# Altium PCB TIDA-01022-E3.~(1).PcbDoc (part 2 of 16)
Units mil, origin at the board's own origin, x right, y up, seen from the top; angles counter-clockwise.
Board outline 6929.13 x 11614.17 mil, 12 copper layers (L1_Top Layer, L2_GND, L3_GND, L4_Signal Layer 1, L5_GND, L6_PWR, L7_GND/PWR, L8_PWR, L9_GND/PWR, L10_Signal Layer 2, L11_GND, L12_Bottom Layer), stack 64.6 mil thick; 1733 components, 993 nets, 5987 pads, 3555 vias.

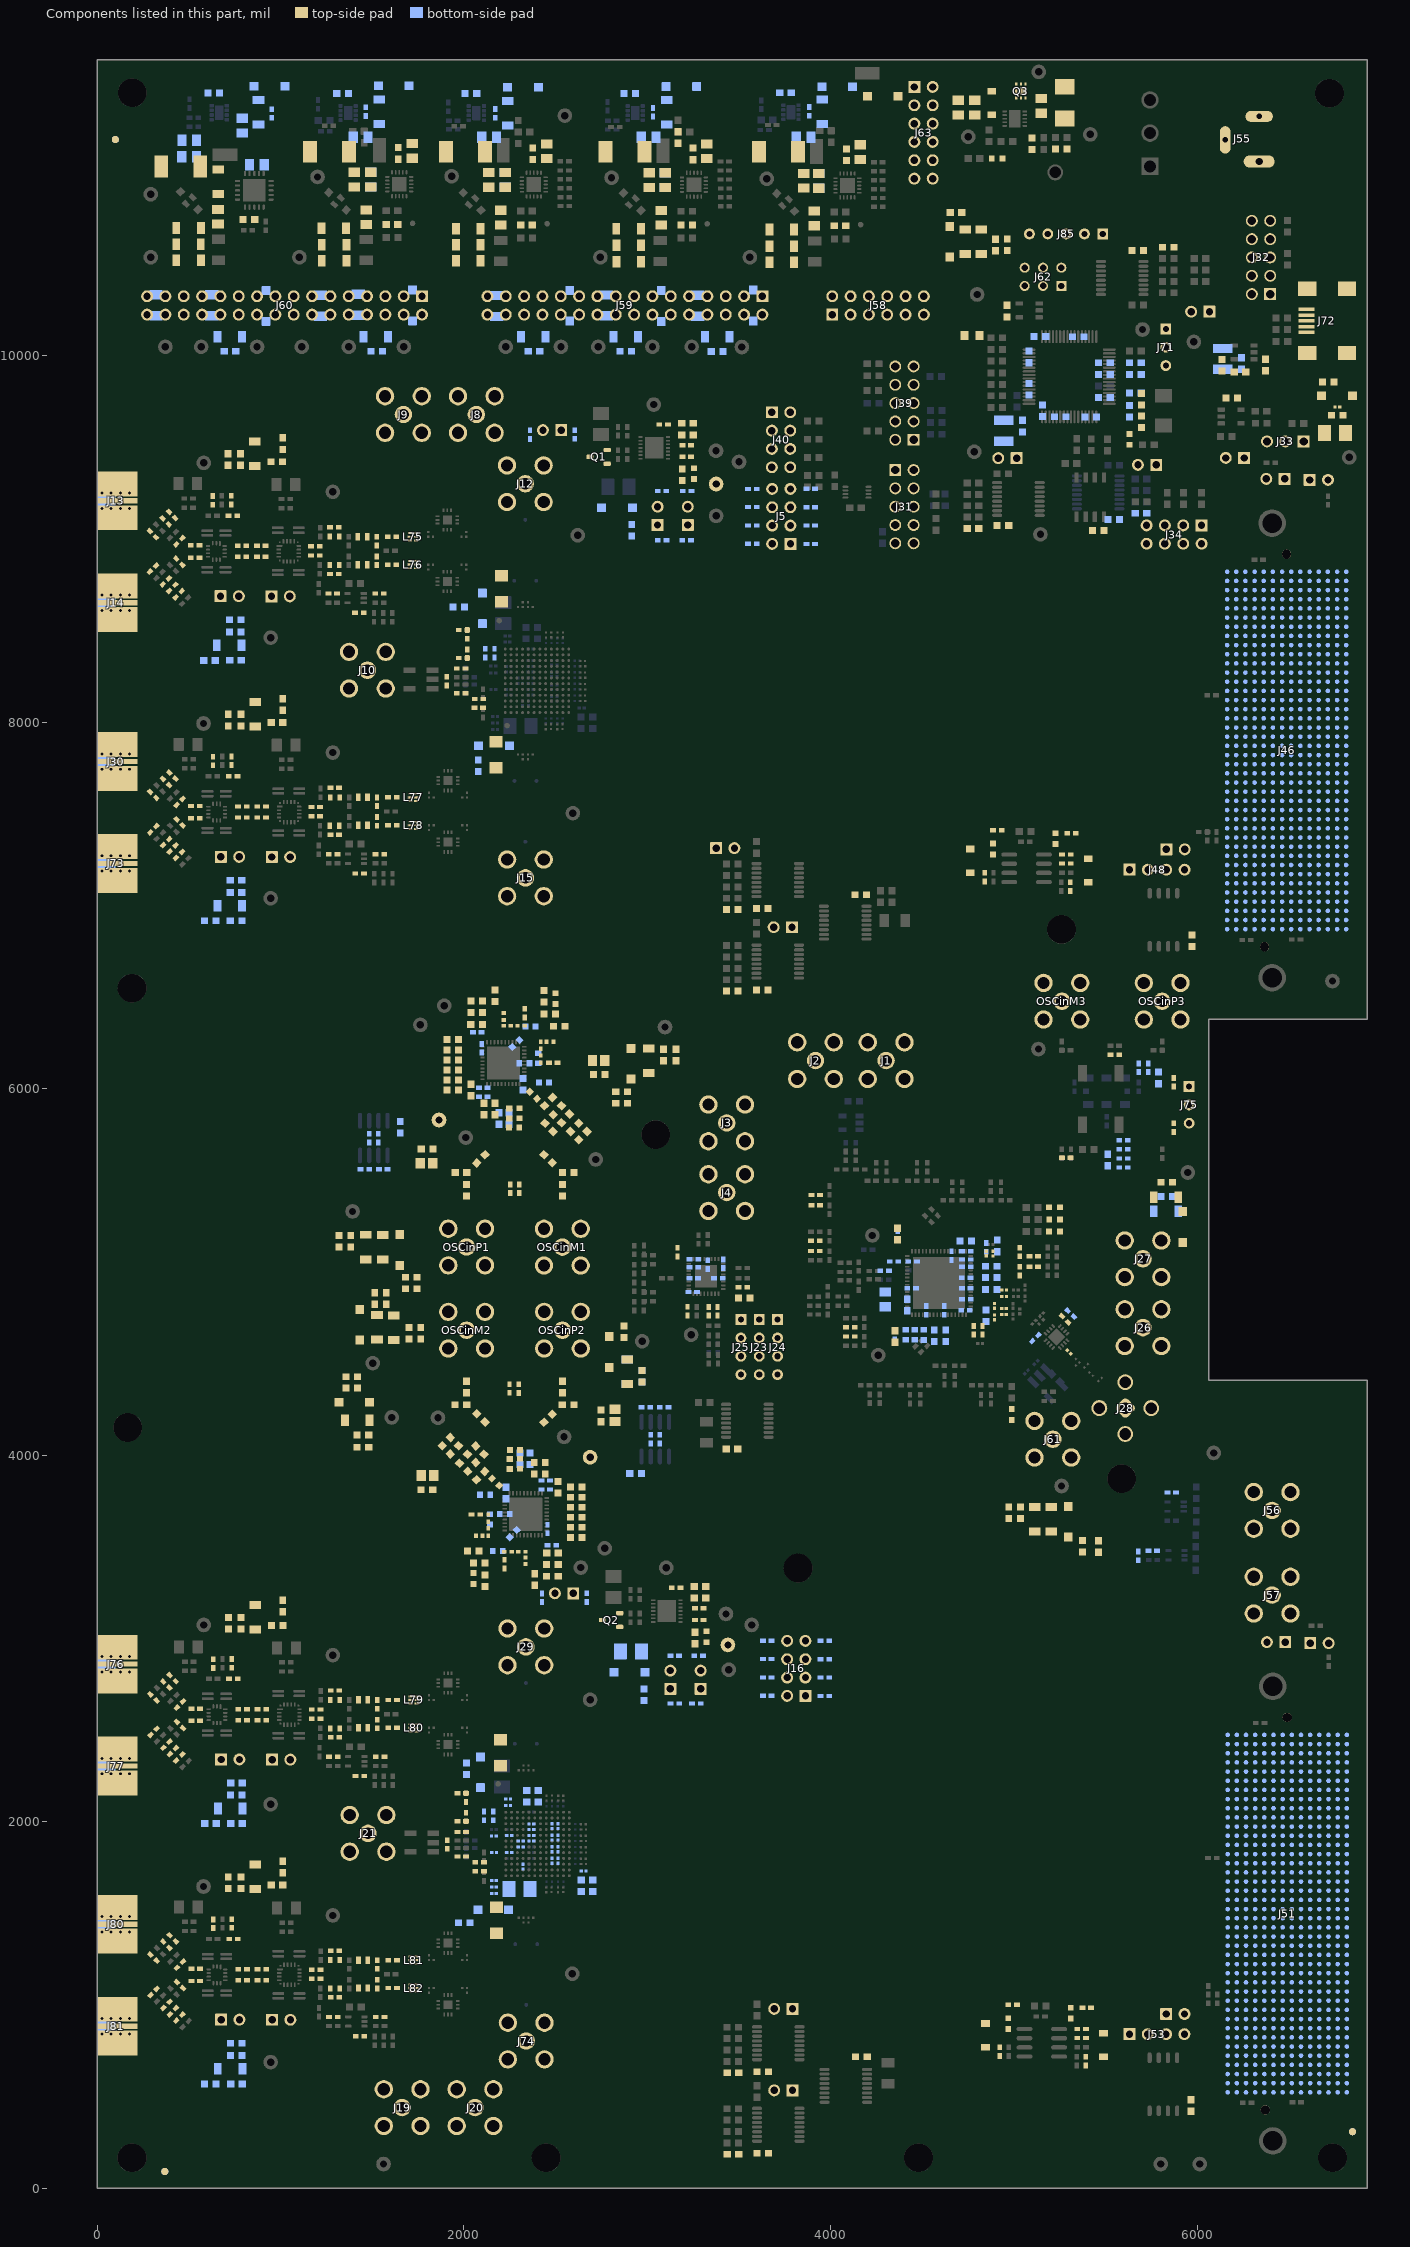
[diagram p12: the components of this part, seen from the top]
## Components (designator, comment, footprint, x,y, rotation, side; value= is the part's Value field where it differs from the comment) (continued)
C288 "GRM033C71A104KE14D" 0201#1 2367.24,1894.85 r0 bottom
C289 "GRM033C71A104KE14D" 0201#1 2367.24,1926.34 r0 bottom
C290 "GRM033C71A104KE14D" 0201#1 2367.24,1957.84 r0 bottom
C291 "GRM033C71A104KE14D" 0201#1 2367.24,1989.33 r0 bottom
C292 "C1608X5R1A105K080AC" 0603 2373.6,2108.56 r0 bottom
C293 "C1608X5R1A105K080AC" 0603 2373.6,2170.56 r0 bottom
C294 "293D106X0010B2TE3" 3528-21 2302.86,1632.5 r0 bottom
C295 "GRM033C71A104KE14D" 0201#1 2322.76,1755.87 r270 bottom
C296 "GRM033C71A104KE14D" 0201#1 2246.77,1926.34 r180 bottom
C297 "GRM033C71A104KE14D" 0201#1 2246.77,1831.85 r180 bottom
C298 "GRM033C71A104KE14D" 0201#1 2309.76,1894.85 r180 bottom
C299 "GRM033C71A104KE14D" 0201#1 2309.76,1863.35 r180 bottom
C300 "GRM033C71A104KE14D" 0201#1 2240.6,2124.56 r180 bottom
C301 "GRM033C71A104KE14D" 0201#1 2164.15,1831.8 r180 bottom
C302 "GRM033C71A104KE14D" 0201#1 2163.15,1921.8 r180 bottom
C303 "GRM033C71A104KE14D" 0201#1 2163.6,1680.56 r180 bottom
C304 "GRM033C71A104KE14D" 0201#1 2163.6,1644.56 r180 bottom
C305 "GRM033C71A104KE14D" 0201#1 2163.6,1609.56 r180 bottom
C306 "GRM033C71A104KE14D" 0201#1 2240.6,2089.56 r180 bottom
C307 "GRM033R60J104KE19D" 0201_033 5301,4563 r135 top
C308 "C1005X7R1E104M050BB" 0402#1 5310.3,4772.7 r135 bottom
C309 "293D106X0010B2TE3" 3528-21 2910.79,2930.24 r0 bottom
C310 "GRM033C71A104KE14D" 0201#1 2511.73,1787.37 r90 bottom
C311 "GRM033C71A104KE14D" 0201#1 2480.24,1787.37 r90 bottom
C312 "GRM033C71A104KE14D" 0201#1 2480.24,1850.36 r90 bottom
C313 "GRM033C71A104KE14D" 0201#1 2511.73,1850.36 r90 bottom
C314 "GRM033C71A104KE14D" 0201#1 2652.77,1731.37 r0 bottom
C315 "GRM033C71A104KE14D" 0201#1 2480.24,1913.35 r270 bottom
C316 "GRM033C71A104KE14D" 0201#1 2511.73,1913.35 r270 bottom
C317 "GRM033C71A104KE14D" 0201#1 2480.24,1976.34 r270 bottom
C318 "GRM033C71A104KE14D" 0201#1 2511.73,1976.34 r270 bottom
C319 "C1608X5R1A105K080AC" 0603 2671.54,1682.24 r0 bottom
C320 "C1608X5R1A105K080AC" 0603 2671.54,1619.24 r0 bottom
C321 "C1005X7R1E104M050BB" 0402#1 2081.89,8126.19 r0 top
C322 "520L103KT16T" 0402_065 2331.07,6411.77 r270 top
C323 "C1608X7R1C105K080AC" 0603 2191.16,5836.72 r90 bottom
C324 "C1608X7R1C105K080AC" 0603L 2378.66,5963.82 r135 top
C325 "C1005X7R1E104M050BB" 0402#1 2080.51,8077.19 r0 top
C326 "C1608X7R1C105K080AC" 0603L 2329.56,6138.82 r180 bottom
C327 "0603YC104JAT2A" 0603L 2283.06,6246.02 r45 bottom
C328 "0603YC104JAT2A" 0603 1798.77,5670.52 r0 top
C329 "C0805C106K8PACTU" 0805 1795.77,5592.72 r0 top
C330 "C0805C106K8PACTU" 0805 2734.77,6153.85 r0 top
C331 "0603YC104JAT2A" 0603 2737.77,6078.05 r0 top
C332 "C1608X7R1C105K080AC" 0603 2069.28,6414.92 r0 top
C333 "C1608X7R1C105K080AC" 0603 1938.66,6047.12 r0 top
C334 "C1005X7R1E104M050BB" 0402#1 2085.22,1780.19 r0 top
C335 "GRM1885C1H182JA01D" 0603 1938.66,6156.42 r0 top
C336 "GRM1885C2A301JA01D" 0603 2603.66,5743.82 r315 top
C337 "C0603C563J4RACTU" 0603 2553.66,5883.82 r315 top
C338 "520L103KT16T" 0402_065 2486.81,6141.72 r180 top
C339 "06031C152JAT2A" 0603 2460.85,5928.95 r225 top
C340 "C1608X7R1C105K080AC" 0603 2322,6024.32 r270 bottom
C341 "C1005X7R1E104M050BB" 0402#1 2085.22,1731.19 r0 top
C342 "C1608X5R1A106M080AC" 0603 1938.66,6102.02 r180 top
C343 "C1608X7R1C105K080AC" 0603 2038.16,5992.72 r90 top
C344 "C1608X5R1A106M080AC" 0603 1938.66,6267.52 r180 top
C345 "C1608X5R1A106M080AC" 0603 2168.66,5888.82 r270 top
C346 "C1608X5R1A106M080AC" 0603 2068.87,6350.82 r0 top
C347 "C1608X5R1A106M080AC" 0603 1938.66,6211.12 r0 top
C348 "0603YC104JAT2A" 0603L 2246.86,5864.22 r90 top
C349 "0603YC104JAT2A" 0603L 2302.04,5865.92 r90 top
C350 "0603YC104JAT2A" 0603 1651.97,5788.77 r90 bottom
C351 "GRM033R60J104KE19D" 0201_033 4894.89,4752 r90 top
C352 "520L103KT16T" 0402_065 2220.55,3406.2 r90 top
C353 "C1608X7R1C105K080AC" 0603 2360.46,3981.26 r270 bottom
C354 "C1608X7R1C105K080AC" 0603L 2172.96,3854.16 r315 top
C355 "GRM1555C1H471JA01D" 0402#1 3031,11327 r270 bottom
C356 "C1608X7R1C105K080AC" 0603L 2222.06,3679.16 r0 bottom
C357 "0603YC104JAT2A" 0603L 2268.56,3571.96 r225 bottom
C358 "0603YC104JAT2A" 0603 1797.65,3811.53 r180 top
C359 "C0805C106K8PACTU" 0805 1800.65,3889.33 r180 top
C360 "C0805C106K8PACTU" 0805 2824.18,4217.68 r270 top
C361 "0603YC104JAT2A" 0603 2748.38,4214.68 r270 top
C362 "C1608X7R1C105K080AC" 0603 2482.34,3403.06 r180 top
C363 "C1608X7R1C105K080AC" 0603 2612.96,3770.86 r180 top
C364 "GRM1555C1H471JA01D" 0402#1 2170.76,11320.39 r270 bottom
C365 "GRM1885C1H182JA01D" 0603 2612.96,3661.56 r180 top
C366 "GRM1885C2A301JA01D" 0603 1947.96,4074.16 r135 top
C367 "C0603C563J4RACTU" 0603 1997.96,3934.16 r135 top
C368 "520L103KT16T" 0402_065 2064.8,3676.26 r0 top
C369 "06031C152JAT2A" 0603 2090.76,3889.03 r45 top
C370 "C1608X7R1C105K080AC" 0603 2229.61,3793.65 r90 bottom
C371 "GRM1555C1H471JA01D" 0402#1 3883,11332 r270 bottom
C372 "C1608X5R1A106M080AC" 0603 2612.96,3715.96 r0 top
C373 "C1608X7R1C105K080AC" 0603 2513.46,3825.26 r270 top
C374 "C1608X5R1A106M080AC" 0603 2612.96,3550.46 r0 top
C375 "C1608X5R1A106M080AC" 0603 2382.96,3929.16 r90 top
C376 "C1608X5R1A106M080AC" 0603 2482.75,3467.16 r180 top
C377 "C1608X5R1A106M080AC" 0603 2612.96,3606.86 r180 top
C378 "0603YC104JAT2A" 0603L 2304.76,3953.76 r270 top
C379 "0603YC104JAT2A" 0603L 2249.58,3952.06 r270 top
C380 "0603YC104JAT2A" 0603 2936.3,3899.45 r0 bottom
C381 "EMK107BBJ106MA-T" 0603 3529.5,4857.79 r180 top
C382 "C1005X7S1A105K050BC" 0402#1 3521.5,4916.29 r180 top
C383 "GRM155R71C104KA88D" 0402#1 3219,4786 r90 top
C384 "GRM155R71E103KA01D" 0402#1 3254.5,5025.29 r0 bottom
C385 "GRM155R71E103KA01D" 0402#1 3247.88,4890.67 r0 bottom
C386 "GRM155R71E103KA01D" 0402#1 3253.5,4965.29 r0 bottom
C387 "GRM155R71E103KA01D" 0402#1 3330.5,5040.29 r90 bottom
C388 "GRM155R71E103KA01D" 0402#1 3387.5,4965.29 r180 bottom
C389 "GRM155R71E103KA01D" 0402#1 3414.78,5044.67 r90 bottom
C390 "GRM155R71E103KA01D" 0402#1 3254.5,5069.79 r180 bottom
C391 "C1005X7R1E104M050BB" 0402#1 3335.5,4785.29 r90 top
C392 "C1005X7R1E104M050BB" 0402#1 3383.5,4785.29 r90 top
C393 "0201ZD392KAT2A" 0201#1 4886.47,5099.94 r90 top
C394 "C1005X7R1E104M050BB" 0402#1 3917.47,5169.44 r180 top
C395 "GRM0335C1E470JA01D" 0201_033 4849.35,5100.47 r90 top
C396 "C1005X7R1E104M050BB" 0402#1 3917.47,5114.44 r180 top
C397 "GRM033R60J104KE19D" 0201_033 4946.41,4866.77 r180 top
C398 "C1005X5R1A684K050BB" 0402#1 4828.97,4682.02 r90 top
C399 "C1005X7R1E104M050BB" 0402#1 4780.97,4682.02 r90 top
C400 "GRM033R60J104KE19D" 0201_033 4946.41,4900.77 r180 top
C401 "C1005X7R1E104M050BB" 0402#1 4108.01,4698.08 r180 top
C402 "C1005X7R1E104M050BB" 0402#1 4108.01,4648.08 r180 top
C403 "GRM033R60J104KE19D" 0201_033 4945.97,4769.02 r180 top
C404 "GRM033R60J104KE19D" 0201_033 4945.97,4801.02 r180 top
C405 "GRM033R60J104KE19D" 0201_033 4894.89,4815 r270 top
C406 "C1005X7R1E104M050BB" 0402#1 5031.66,5004.8 r90 top
C407 "C1005X7R1E104M050BB" 0402#1 5108.66,5028.8 r0 top
C408 "C1005X7R1E104M050BB" 0402#1 5108.66,5085.8 r0 top
C409 "C0402C120J3GACAUTO" 0402#1 5031.66,5108.8 r270 top
C410 "C1005X7R1E104M050BB" 0402#1 5285.7,5622.27 r180 top
C411 "C1005X5R0J475M050BC" 0402#1 5733.97,6113.84 r270 bottom
C412 "GRM155R71E103KA01D" 0402#1 5680.97,6113.84 r270 bottom
C413 "C1005X7R1E104M050BB" 0402#1 3919.28,5419.5 r180 top
C414 "GRM1555C1H100JA01D" 0402#1 5598.08,5669.02 r180 bottom
C415 "C1005X7R1E104M050BB" 0402#1 3919.28,5364.5 r180 top
C416 "GRM155R71E222KA01D" 0402#1 5598.08,5619.02 r180 bottom
C417 "C1005X7R1E104M050BB" 0402#1 5550.66,6185.09 r0 top
C418 "04025A101FAT2A" 0402#1 5598.08,5719.02 r180 bottom
C419 "C1005X7R1E104M050BB" 0402#1 5598.08,5570.02 r180 bottom
C420 "C1005X7S1A105K050BC" 0402#1 4441.66,4910.2 r0 bottom
C421 "GRM155R71C104KA88D" 0402#1 4740.87,4851.14 r180 bottom
C422 "GRM155R71E103KA01D" 0402#1 4735.97,4791.02 r180 bottom
C423 "C1005X7R1E104M050BB" 0402#1 4447.89,5057 r180 bottom
C424 "C1005X7R1E104M050BB" 0402#1 4294.47,5006.94 r0 bottom
C425 "C0603C330J5GACTU" 0603L 4507.97,4656.95 r90 bottom
C426 "C0603C330J5GACTU" 0603L 4458.97,4657.46 r90 bottom
C427 "C0603C330J5GACTU" 0603L 4409.97,4657.02 r90 bottom
C428 "C1005X7S1A105K050BC" 0402#1 4620.79,4790.12 r90 bottom
C429 "C1005X7S1A105K050BC" 0402#1 4522.36,4790.12 r90 bottom
C430 "C1005X7S1A105K050BC" 0402#1 4350.97,4655.89 r270 bottom
C431 "C0603C104J3RACTU" 0603 4418.03,4819.65 r270 bottom
C432 "C0805C106K8PACTU" 0805_HV 4298.97,4850.02 r270 bottom
C433 "C1005X7S1A105K050BC" 0402#1 4848.97,5134.02 r90 bottom
C434 "GRM155R71C104KA88D" 0402#1 4741.35,5112.02 r180 bottom
C435 "GRM155R71E103KA01D" 0402#1 4740.87,5067.68 r180 bottom
C436 "C1005X7R1E104M050BB" 0402#1 4740.87,5028.31 r0 bottom
C437 "C1005X7R1E104M050BB" 0402#1 4739.47,4967.94 r0 bottom
C438 "C1005X7R1E104M050BB" 0402#1 4740.47,4910.94 r0 bottom
C439 "C1005X7S1A105K050BC" 0402#1 4365.97,5199.14 r90 bottom
C440 "C1005X7S1A105K050BC" 0402#1 4660.16,5089.33 r270 bottom
C441 "C0603C104J3RACTU" 0603 5675.72,10572.95 r0 top
C442 "C0603C104J3RACTU" 0603 5841.84,10590.12 r180 top
C443 "C0603C104J3RACTU" 0603 4777.32,9056.2 r0 top
C444 "C0603C104J3RACTU" 0603 4940.2,9072.76 r180 top
C445 "C0603C104J3RACTU" 0603 6189.08,9767.75 r0 top
C446 "C1005X7S1A105K050BC" 0402#1 5117,4639 r225 bottom
C447 "C0603C104J3RACTU" 0603 5544.82,9105 r0 bottom
C448 "C0603C104J3RACTU" 0603 5693.31,9139.2 r180 bottom
C449 "C0603C104J3RACTU" 0603 3627.07,6537.73 r180 top
C450 "C0603C104J3RACTU" 0603 3463.97,6532.22 r0 top
C451 "C0603C104J3RACTU" 0603 3630.4,191.73 r180 top
C452 "C0603C104J3RACTU" 0603 3467.31,186.22 r0 top
C453 "C0603C104J3RACTU" 0603 3626.82,6982.68 r180 top
C454 "C0603C104J3RACTU" 0603 3463.97,6976.93 r0 top
C455 "C0603C104J3RACTU" 0603 3629.91,636.44 r180 top
C456 "C0603C104J3RACTU" 0603 3467.31,630.93 r0 top
C457 "GRM188R61A106ME69D" 0603 5662.88,9794.97 r0 bottom
C458 "C0603C104J3RACTU" 0603 5493.88,9770.97 r0 bottom
C459 "C0603C104J3RACTU" 0603 5418.88,9663.97 r0 bottom
C460 "C0603C104J3RACTU" 0603 5493.88,9959.97 r0 bottom
C461 "C0603C104J3RACTU" 0603 5083.38,9992.24 r270 bottom
C462 "C0603C104J3RACTU" 0603 5141.88,10102.97 r0 bottom
C463 "C0603C104J3RACTU" 0603 5083.38,9815.07 r90 bottom
C464 "C0603C104J3RACTU" 0603 5351.1,10102.47 r0 bottom
C465 "C0603C104J3RACTU" 0603 5252.67,9665.47 r0 bottom
C466 "GRM188R61A106ME69D" 0603 5662.88,9895.97 r0 bottom
C467 "C0603C104J3RACTU" 0603 5493.88,9895.97 r0 bottom
C468 "C0603C104J3RACTU" 0603 4962.88,10241.97 r270 top
C469 "C0603C104J3RACTU" 0603 5156.87,9697.98 r270 bottom
C470 "C1608X7R1C105K080AC" 0603 6233.59,9910.27 r0 top
C471 "GRM32ER61A107ME20L" 1210_270 6139,9981 r90 bottom
C472 "C0603C104J3RACTU" 0603 6242,9956 r270 bottom
C473 "C1608X7R1C105K080AC" 0603 6372.57,9947.69 r270 top
C474 "GRM32ER61A107ME20L" 1210_270 4944.87,9588.47 r270 bottom
C475 "C1608X5R1A105K080AC" 0603 5972.09,6807.18 r90 top
C476 "C1608X5R1A105K080AC" 0603 5966.26,452.43 r90 top
C477 "08053D105KAT2A" 0805_HV 4785.82,11352.8 r90 top
C478 "08053D105KAT2A" 0805_HV 4695.82,11352.8 r90 top
C479 "08053D105KAT2A" 0805_HV 5149.32,11361.73 r90 top
C480 "06031C102MAT2A" 0603 5258.82,11125.8 r0 top
C481 "06031C102MAT2A" 0603 5099.82,11154.8 r270 top
C482 "293D106X0010B2TE3" 3528-21 6752.11,9576.8 r180 top
C483 "GRM033C71A104KE14D" 0201#1 6765.11,9719.8 r180 top
C484 "C1608X5R1A105K080AC" 0603 6764.11,9673.8 r180 top
C485 "CGA3E2X7R1H104K080AA" 0603 2970.44,4430.98 r270 top
C486 "C3216X5R1E336M160AC" 1206_180 2890,4456 r270 top
C487 "C3216X7R1E106M160AE" 1206_190 2890,4456 r90 bottom
C488 "GCM188R71H103KA37D" 0603 2970.44,4430.98 r270 bottom
C489 "C0603C104J3RACTU" 0603 3462.18,4033.15 r180 top
C490 "GRM155R71C104JA88D" 0402#1 407.5,9129.97 r135 top
C491 "GRM155R71C104JA88D" 0402#1 408.3,8732.3 r45 top
C492 "GRM155R71E103KA01D" 0402#1 443.3,8697.3 r45 top
C493 "GRM155R71C104JA88D" 0402#1 409.3,7707.84 r135 top
C494 "C3216X7R1E106M160AE" 1206_190 3105,11328 r270 bottom
C495 "JMK212BJ226MG-T" 0805_HV 3007,11191 r0 bottom
C496 "C3216X7R1E106M160AE" 1206_190 2897.74,10690.12 r0 top
C497 "C3216X7R1E106M160AE" 1206_190 2898.74,10601.12 r0 top
C498 "C3216X7R1E106M160AE" 1206_190 2898.74,10512.12 r0 top
C499 "GRM155R71C104JA88D" 0402#1 410.09,7310.17 r45 top
C500 "GRM155R71E103KA01D" 0402#1 445.09,7275.17 r45 top
C501 "GRM1885C1H332JA01D" 0603 2904.66,11429.33 r180 bottom
C502 "GRM155R71C104JA88D" 0402#1 410.82,2783.61 r135 top
C503 "GRM155R71C104JA88D" 0402#1 411.61,2385.93 r45 top
C504 "GRM155R71E103KA01D" 0402#1 446.61,2350.93 r45 top
C505 "GRM155R71C104JA88D" 0402#1 410.9,1364.27 r135 top
C506 "GRM155R71C104JA88D" 0402#1 411.69,966.6 r45 top
C507 "GRM155R71E103KA01D" 0402#1 446.69,931.6 r45 top
C508 "GRM155R71C104KA88D" 0402#1 5861.47,3797.1 r0 bottom
C509 "GRM1555C1H471JA01D" 0402#1 1464,11330 r270 bottom
C510 "GRM1555C1H471JA01D" 0402#1 952,11319.92 r270 bottom
C511 "GRM155R71C104KA88D" 0402#1 5757.86,3478.92 r180 bottom
C512 "GRM155R71E103KA01D" 0402#1 5279.3,4741.7 r135 top
C513 "GRM1555C1HR50WA01" 0402#1 1293,9063 r180 top
C514 "GRM1555C1HR50WA01" 0402#1 1293,8808 r180 top
C515 "GRM1555C1HR50WA01" 0402#1 1294.8,7640.87 r180 top
C516 "GRM21BR61C106KE15L" 0805_HV 3097.92,10956.68 r270 top
C517 "GRM21BR61C106KE15L" 0805_HV 3097.92,10956.68 r270 bottom
C518 "GRM219R60G476ME44D" 0805_HV 3009.92,10956.68 r270 top
C519 "GRM219R60G476ME44D" 0805_HV 3075.05,10750.99 r90 top
C520 "GRM1555C1HR50WA01" 0402#1 1294.8,7385.87 r180 top
C521 "GRM1555C1HR50WA01" 0402#1 1296.32,2716.64 r180 top
C522 "GRM188R71H103KA01D" 0603 3214.86,10711.68 r0 top
C523 "GRM21BR61C106KE15L" 0805_HV 3324.92,11113.68 r90 top
C524 "GRM188R71H103KA01D" 0603 3248.92,11099.68 r90 top
C525 "GRM1555C1HR50WA01" 0402#1 1296.32,2461.64 r180 top
C526 "GRM1555C1HR50WA01" 0402#1 1296.39,1297.3 r180 top
C527 "GRM1555C1HR50WA01" 0402#1 1296.39,1042.3 r180 top
C528 "50V, 100nF" "0603_1.6x0.8x0.8mm_Reflow Soldering"#1 2169,6507 r90 top
C529 "50V, 100nF" "0603_1.6x0.8x0.8mm_Reflow Soldering"#1 2520,6340 r0 top
C530 "50V, 100nF" "0603_1.6x0.8x0.8mm_Reflow Soldering"#1 2386,3322 r270 top
C531 "50V, 100nF" "0603_1.6x0.8x0.8mm_Reflow Soldering"#1 2051,3477 r180 top
C532 "50V, 100nF" "0603_1.6x0.8x0.8mm_Reflow Soldering"#2 6710.38,9856 r180 top
C533 "50V, 100nF" "0603_1.6x0.8x0.8mm_Reflow Soldering"#1 2077.75,7761 r90 bottom
C534 "50V, 100nF" "0603_1.6x0.8x0.8mm_Reflow Soldering"#1 2001,1449 r0 bottom
C535 "50V, 100nF" "0603_1.6x0.8x0.8mm_Reflow Soldering"#1 1971.26,8627 r0 bottom
C536 "50V, 100nF" "0603_1.6x0.8x0.8mm_Reflow Soldering"#1 2013,2289 r90 bottom
C537 "C3216X7R1E106M160AE" 1206_190 2238.76,11321.39 r270 bottom
C538 "JMK212BJ226MG-T" 0805_HV 2136.53,11191 r0 bottom
C539 "C3216X7R1E106M160AE" 1206_190 2023.92,10516.98 r0 top
C540 "C3216X7R1E106M160AE" 1206_190 2022.92,10603.98 r0 top
C541 "C3216X7R1E106M160AE" 1206_190 2023.92,10690.98 r0 top
C542 "50V, 100nF" "0603_1.6x0.8x0.8mm_Reflow Soldering"#1 2914.94,9046.26 r90 bottom
C543 "50V, 100nF" "0603_1.6x0.8x0.8mm_Reflow Soldering"#1 2982.7,2692.84 r90 bottom
C544 "GRM1885C1H332JA01D" 0603 2037.66,11429.28 r180 bottom
C545 "16V, 1uF" "0603_1.6x0.8x0.8mm_Reflow Soldering"#1 1712,4908 r0 top
C546 "50V, 100nF" "0603_1.6x0.8x0.8mm_Reflow Soldering"#1 1712,4971 r180 top
C547 "16V, 1uF" "0603_1.6x0.8x0.8mm_Reflow Soldering"#1 2860,5920 r180 top
C548 "50V, 100nF" "0603_1.6x0.8x0.8mm_Reflow Soldering"#1 2860,5983 r0 top
C549 "16V, 1uF" "0603_1.6x0.8x0.8mm_Reflow Soldering"#1 1576,4855 r270 top
C550 "50V, 100nF" "0603_1.6x0.8x0.8mm_Reflow Soldering"#1 1513,4855 r90 top
C551 "16V, 1uF" "0603_1.6x0.8x0.8mm_Reflow Soldering"#1 1387,4428 r0 top
C552 "50V, 100nF" "0603_1.6x0.8x0.8mm_Reflow Soldering"#1 1387,4366 r180 top
C553 "50V, 100nF" "0603_1.6x0.8x0.8mm_Reflow Soldering"#1 5374,3503 r90 top
C554 "50V, 100nF" "0603_1.6x0.8x0.8mm_Reflow Soldering"#1 5462,3502 r90 top
C555 "50V, 100nF" "0603_1.6x0.8x0.8mm_Reflow Soldering"#1 4684,10780 r180 top
C556 "50V, 100nF" "0603_1.6x0.8x0.8mm_Reflow Soldering"#1 2873,4674 r270 top
C561 "50V, 100nF" "0603_1.6x0.8x0.8mm_Reflow Soldering"#1 1011,9519 r270 top
C562 "50V, 100nF" "0603_1.6x0.8x0.8mm_Reflow Soldering"#1 1011,3177 r270 top
C563 "50V, 100nF" "0603_1.6x0.8x0.8mm_Reflow Soldering"#1 1011,8096 r270 top
C564 "50V, 100nF" "0603_1.6x0.8x0.8mm_Reflow Soldering"#1 1011,1753.42 r270 top
C566 "50V, 100nF" "0603_1.6x0.8x0.8mm_Reflow Soldering"#1 611.2,8336.13 r0 bottom
C567 "50V, 100nF" "0603_1.6x0.8x0.8mm_Reflow Soldering"#1 616,6916 r0 bottom
C570 "50V, 100nF" "0603_1.6x0.8x0.8mm_Reflow Soldering"#1 617.21,1991.05 r0 bottom
C572 "50V, 100nF" "0603_1.6x0.8x0.8mm_Reflow Soldering"#1 615.59,570.43 r0 bottom
C573 "25V, 10uF" 1206_3.2x1.6x1.6mm 721,10102 r0 bottom
C574 "50V, 100nF" "0603_1.6x0.8x0.8mm_Reflow Soldering"#1 723,10023 r0 bottom
C575 "25V, 10uF" 1206_3.2x1.6x1.6mm 1519,10102 r0 bottom
C576 "50V, 100nF" "0603_1.6x0.8x0.8mm_Reflow Soldering"#1 1524,10023 r0 bottom
C577 "25V, 10uF" 1206_3.2x1.6x1.6mm 2377,10102 r0 bottom
C578 "50V, 100nF" "0603_1.6x0.8x0.8mm_Reflow Soldering"#1 2382,10023 r0 bottom
C579 "25V, 10uF" 1206_3.2x1.6x1.6mm 3381,10102 r0 bottom
C580 "50V, 100nF" "0603_1.6x0.8x0.8mm_Reflow Soldering"#1 3381,10021 r0 bottom
C581 "25V, 10uF" 1206_3.2x1.6x1.6mm 2883,10102 r0 bottom
C582 "50V, 100nF" "0603_1.6x0.8x0.8mm_Reflow Soldering"#1 2883,10023 r0 bottom
C587 "GRM21BR61C106KE15L" 0805_HV 2136.09,10957.54 r270 top
C588 "GRM21BR61C106KE15L" 0805_HV 2224.09,10957.54 r270 bottom
C589 "GRM219R60G476ME44D" 0805_HV 2224.09,10957.54 r270 top
C590 "GRM219R60G476ME44D" 0805_HV 2201.22,10751.85 r90 top
C593 "GRM188R71H103KA01D" 0603 2341.03,10712.54 r0 top
C594 "GRM21BR61C106KE15L" 0805_HV 2451.09,11114.54 r90 top
C595 "GRM188R71H103KA01D" 0603 2375.09,11100.54 r90 top
C596 "CGA3E2X7R1H104K080AA" 0603 1382.17,5166.8 r270 top
C597 "C3216X5R1E336M160AC" 1206_180 1556.17,5134.8 r270 top
C598 "C3216X7R1E106M160AE" 1206_190 1465.17,5135.8 r90 top
C599 "GCM188R71H103KA37D" 0603 1317.17,5166.8 r270 top
C600 "C3216X7R1E106M160AE" 1206_190 3954,11330 r270 bottom
C601 "JMK212BJ226MG-T" 0805_HV 3853,11191 r0 bottom
C602 "C3216X7R1E106M160AE" 1206_190 3733.7,10687.14 r0 top
C603 "C3216X7R1E106M160AE" 1206_190 3733.86,10596.67 r0 top
C604 "C3216X7R1E106M160AE" 1206_190 3733.86,10509.36 r0 top
C605 "CGA3E2X7R1H104K080AA" 0603 3088.8,6183.28 r270 top
C606 "C3216X7R1E106M160AE" 1206_190 3007.8,6152.28 r90 top
C607 "GCM188R71H103KA37D" 0603 3155.8,6183.28 r270 top
C608 "GRM1885C1H332JA01D" 0603 3753.67,11433.46 r180 bottom
C609 "CGA3E2X7R1H104K080AA" 0603 1699.34,4665.4 r90 top
C610 "C3216X5R1E336M160AC" 1206_180 1616.34,4696.4 r90 top
C611 "C3216X7R1E106M160AE" 1206_190 1525.34,4697.4 r270 top
C612 "GCM188R71H103KA37D" 0603 1764.34,4665.4 r90 top
C613 "GRM21BR61C106KE15L" 0805_HV 3853,10953 r270 top
C614 "GRM21BR61C106KE15L" 0805_HV 3934.9,10952.67 r270 top
C615 "GRM219R60G476ME44D" 0805_HV 3934.9,10952.67 r270 bottom
C616 "GRM219R60G476ME44D" 0805_HV 3911,10748 r90 top
C619 "GRM188R71H103KA01D" 0603 4051.83,10707.67 r0 top
C620 "GRM21BR61C106KE15L" 0805_HV 4161.9,11109.67 r90 top
C621 "GRM188R71H103KA01D" 0603 4085.9,11095.67 r90 top
C622 "CGA3E2X7R1H104K080AA" 0603 1448.43,4110.16 r180 top
C623 "C3216X7R1E106M160AE" 1206_190 1417.43,4191.16 r0 top
C624 "GCM188R71H103KA37D" 0603 1448.43,4043.16 r180 top
C625 "CGA3E2X7R1H104K080AA" 0603 4972.23,3686.01 r270 top
C626 "C3216X5R1E336M160AC" 1206_180 5113.35,3651.01 r270 top
C627 "C3216X7R1E106M160AE" 1206_190 5203.35,3651.01 r90 top
C628 "GCM188R71H103KA37D" 0603 5036.23,3686.01 r270 top
C629 "CGA3E2X7R1H104K080AA" 0603 5834.43,5489.23 r180 top
C630 "C3216X5R1E336M160AC" 1206_180 5830,5407 r180 top
C631 "C3216X7R1E106M160AE" 1206_190 5830,5330 r0 bottom
C632 "GCM188R71H103KA37D" 0603 5834.43,5412.23 r180 bottom
C633 "CGA3E2X7R1H104K080AA" 0603 4900.47,10602.82 r90 top
C634 "C3216X5R1E336M160AC" 1206_180 4735.85,10620.25 r90 top
C635 "C3216X7R1E106M160AE" 1206_190 4820.84,10620.25 r270 top
C636 "GCM188R71H103KA37D" 0603 4963.47,10603.82 r90 top
C643 "C3216X7R1E106M160AE" 1206_190 1538,11330 r270 bottom
C644 "C3216X7R1E106M160AE" 1206_190 1290.04,10692.85 r0 top
C645 "C3216X7R1E106M160AE" 1206_190 1291.04,10604.85 r0 top
C646 "C3216X7R1E106M160AE" 1206_190 1291.04,10516.85 r0 top
C647 "JMK212BJ226MG-T" 0805_HV 1436,11191 r0 bottom
C654 "GRM1885C1H332JA01D" 0603 1337.87,11429.5 r180 bottom
C655 "GRM21BR61C106KE15L" 0805_HV 1402.22,10959.4 r270 top
C656 "GRM21BR61C106KE15L" 0805_HV 1490.22,10959.4 r270 top
C657 "GRM219R60G476ME44D" 0805_HV 1490.22,10959.4 r270 bottom
C658 "CGA3E2X7R1H104K080AA" 0603 780.91,9432.79 r90 top
C659 "CGA3E2X7R1H104K080AA" 0603 783.81,3083.36 r90 top
C660 "GRM219R60G476ME44D" 0805_HV 1467.35,10753.71 r90 top
C663 "C3216X7R1E106M160AE" 1206_190 858.91,9464.79 r270 top
C664 "GCM188R71H103KA37D" 0603 711.91,9432.79 r90 top
C665 "C3216X7R1E106M160AE" 1206_190 861.81,3115.36 r270 top
C666 "GCM188R71H103KA37D" 0603 714.81,3083.36 r90 top
C667 "GRM188R71H103KA01D" 0603 1607.16,10714.4 r0 top
C668 "GRM21BR61C106KE15L" 0805_HV 1717.22,11116.4 r90 top
C669 "GRM188R71H103KA01D" 0603 1641.22,11102.4 r90 top
C670 "CGA3E2X7R1H104K080AA" 0603 782.71,8010.66 r90 top
C671 "CGA3E2X7R1H104K080AA" 0603 782.88,1668.08 r90 top
C672 "C3216X7R1E106M160AE" 1206_190 860.71,8042.66 r270 top
C673 "GCM188R71H103KA37D" 0603 713.71,8010.66 r90 top
C674 "C3216X7R1E106M160AE" 1206_190 860.88,1700.08 r270 top
C675 "GCM188R71H103KA37D" 0603 713.88,1668.08 r90 top
C689 "CGA3E2X7R1H104K080AA" 0603 752.11,8492.11 r180 bottom
C690 "C3216X7R1E106M160AE" 1206_190 879,11325.92 r270 bottom
C693 "C3216X7R1E106M160AE" 1206_190 718.11,8418.11 r0 bottom
C694 "GCM188R71H103KA37D" 0603 752.61,8558.11 r180 bottom
C695 "JMK212BJ226MG-T" 0805_HV 789.8,11254.36 r90 bottom
C696 "JMK212BJ226MG-T" 0805_HV 500,11084.92 r180 bottom
C697 "JMK212BJ226MG-T" 0805_HV 501,11173.92 r180 bottom
C698 "GRM1885C1H332JA01D" 0603 634.55,11431.32 r180 bottom
C700 "CGA3E2X7R1H104K080AA" 0603 755.71,7070.86 r180 bottom
C703 "C3216X7R1E106M160AE" 1206_190 721.71,6996.86 r0 bottom
C704 "GCM188R71H103KA37D" 0603 756.2,7136.86 r180 bottom
C705 "C3216X7R1E106M160AE" 1206_190 497.07,10695.4 r0 top
C706 "C3216X7R1E106M160AE" 1206_190 496.96,10607.1 r0 top
C707 "C3216X7R1E106M160AE" 1206_190 497.07,10519.4 r0 top
C709 "CGA3E2X7R1H104K080AA" 0603 758.02,2146.61 r180 bottom
C712 "C3216X7R1E106M160AE" 1206_190 724.02,2072.61 r0 bottom
C713 "GCM188R71H103KA37D" 0603 758.52,2212.61 r180 bottom
C714 "GRM219R60G476ME44D" 0805_HV 658,10757 r90 top
C715 "C3216X7R1E106M160AE" 1206_190 658.62,10947.81 r90 top
C716 "GRM188R71H103KA01D" 0603 826.5,10742.57 r0 top
C718 "CGA3E2X7R1H104K080AA" 0603 757.48,725.65 r180 bottom
C721 "C3216X7R1E106M160AE" 1206_190 723.48,651.65 r0 bottom
C722 "GCM188R71H103KA37D" 0603 757.97,791.65 r180 bottom
C723 "08053D105KAT2A" 0805_HV 870.42,11041.57 r0 bottom
C736 "GRM188R61A106ME69D" 0603 5047.87,9614.47 r270 bottom
C737 "C0603C104J3RACTU" 0603 4164.82,7057.51 r0 top
C738 "C0603C104J3RACTU" 0603 5460.88,9044.97 r0 top
C739 "GRM1885C2A160JA01D" 0603 5695.88,9638.97 r270 top
C740 "GRM1885C2A160JA01D" 0603 5695.88,9760.97 r90 top
C741 "C0603C104J3RACTU" 0603 4168.15,718.52 r0 top
CALSAT1 "5002" Keystone5002 3375.44,9298.69 r180 top
CALSAT2 "5002" Keystone5002 3440,2965 r180 top
CE_TP1 "5002" Keystone5002 1863.66,5828.82 r135 top
CE_TP2 "5002" Keystone5002 2687.96,3989.16 r45 top
D1 "LTST-C190KFKT" LED_LTST-C190 4886.21,7307.18 r90 top
D2 "1N4148W-7-F" SOD-123 4762.2,7243.18 r90 top
D3 "LTST-C190KFKT" LED_LTST-C190 5227.21,7364.18 r90 top
D4 "1N4148W-7-F" SOD-123 5406.21,7190.18 r90 top
D5 "LTST-C190GKT" LED_LTST-C190 3255.1,9355.55 r270 top
D6 "LTST-C190KFKT" LED_LTST-C190 4969.3,899.25 r90 top
D7 "1N4148W-7-F" SOD-123 4845.3,835.26 r90 top
D8 "LTST-C190KFKT" LED_LTST-C190 5310.3,956.25 r90 top
D9 "1N4148W-7-F" SOD-123 5489.3,782.26 r90 top
D10 "LTST-C190GKT" LED_LTST-C190 3323.43,3009.79 r270 top
D11 "LTST-C191TGKT" LTST-C191_Green 2499.81,6490.72 r90 top
D12 "LTST-C191TGKT" LTST-C191_Green 2051.8,3327.26 r270 top
D13 "LTST-C191TGKT" LTST-C191_Green 5221.49,5353.39 r0 top
D14 "LTST-C191TGKT" LTST-C191_Green 5222.03,5286.39 r0 top
D15 "LTST-C191TGKT" LTST-C191_Green 4988.39,4221.97 r270 top
D16 "LTST-C191TGKT" LTST-C191_Green 5221.47,5220.14 r0 top
D17 "LTST-C191TGKT" LTST-C191_Green 5630.88,9541.97 r270 top
D18 "150080GS75000" WL-SMCW_Green_0805 4772,10109 r0 top
D19 "SMBJ15CA" SMB-Bi 5277.82,11379.8 r270 top
D20 "MBR130T1G" SOD-123 4878.82,11376.8 r90 top
D21 "LTST-C191TGKT" LTST-C191_Green 4908.82,11074.8 r0 top
FID1 "Fiducial" Fiducial10-20 98,11178 r90 top
FID2 "Fiducial" Fiducial10-20 367.56,92 r90 top
FID3 "Fiducial" Fiducial10-20 6847.12,309.47 r90 top
FID4 "Fiducial" Fiducial10-20 98,11178 r90 bottom
FID5 "Fiducial" Fiducial10-20 367.56,92 r90 bottom
FID6 "Fiducial" Fiducial10-20 6847.12,309.47 r90 bottom
J1 "142-0701-201" Johnson_142-0701-20x 4302.89,6153 r0 top
J2 "142-0701-201" Johnson_142-0701-20x 3917.7,6153.02 r0 top
J3 "142-0701-201" Johnson_142-0701-20x 3433.47,5813.02 r0 top
J4 "142-0701-201" Johnson_142-0701-20x 3433.47,5433.02 r0 top
J5 "TSW-104-07-G-D" TSW-104-07-G-D 3731.08,9121.88 r90 top
J6 "TSW-102-07-G-S" TSW-102-07-G-S 3056.08,9124.99 r90 top
J7 "TSW-102-07-G-S" TSW-102-07-G-S 3221.08,9124.99 r90 top
J8 "142-0701-201" Johnson_142-0701-20x 2067.22,9677.9 r90 top
J9 "142-0701-201" Johnson_142-0701-20x 1669.62,9677.9 r90 top
J10 "142-0701-201" Johnson_142-0701-20x 1473.08,8282.9 r270 top
J11 "TSW-102-07-G-S" TSW-102-07-G-S 2480.82,9592.56 r180 top
J12 "142-0701-201" Johnson_142-0701-20x 2334.48,9300.21 r270 top
J13 "142-0771-831" JOHNSON_142-0771-831 0,9206.79 r90 top locked
J14 "142-0771-831" JOHNSON_142-0771-831 0,8650.69 r90 top locked
J15 "142-0701-201" Johnson_142-0701-20x 2335.24,7149.98 r90 top
J16 "TSW-104-07-G-D" TSW-104-07-G-D 3812.72,2836.99 r90 top
J17 "TSW-102-07-G-S" TSW-102-07-G-S 3126.01,2775.21 r90 top
J18 "TSW-102-07-G-S" TSW-102-07-G-S 3291.01,2775.21 r90 top
J19 "142-0701-201" Johnson_142-0701-20x 1662.64,440.91 r270 top
J20 "142-0701-201" Johnson_142-0701-20x 2060.24,440.91 r270 top
J21 "142-0701-201" Johnson_142-0701-20x 1476.41,1936.9 r270 top
J22 "TSW-102-07-G-S" TSW-102-07-G-S 2546.15,3246.57 r180 top
J23 "800-10-004-10-001000" Mill-Max_800-10-004-10-001000 3610.74,4589.66 r270 top
J24 "800-10-004-10-001000" Mill-Max_800-10-004-10-001000 3710.74,4589.66 r270 top
J25 "800-10-004-10-001000" Mill-Max_800-10-004-10-001000 3510.74,4589.66 r270 top
J26 "142-0701-201" Johnson_142-0701-20x 5704.79,4696.07 r180 top
J27 "142-0701-201" Johnson_142-0701-20x 5704.79,5071.8 r180 top
J28 "32K101-400L5" Rosenberger_32K101-400L5 5607.84,4257.16 r315 top
J29 "142-0701-201" Johnson_142-0701-20x 2337.48,2954.59 r0 top
J30 "142-0771-831" JOHNSON_142-0771-831 0,7784.66 r90 top locked
J31 "61301021121" WURTH_61301021121 4403,9175 r270 top
J32 "61301021121" WURTH_61301021121 6348.35,10534.59 r90 top
J33 "61300311121" WURTH_61300311121 6481,9531 r180 top
J34 "TSW-104-07-G-D" TSW-104-07-G-D 5874,9023 r180 top
J35 "TSW-102-07-G-S" TSW-102-07-G-S 6017,10239 r180 top
J36 "TSW-102-07-G-S" TSW-102-07-G-S 4964.82,9440 r180 top
J37 "TSW-102-07-G-S" TSW-102-07-G-S 6206,9441 r180 top
J38 "TSW-102-07-G-S" TSW-102-07-G-S 5727,9403 r180 top
J39 "61301021121" WURTH_61301021121 4403,9740 r90 top
J40 "TSW-104-07-G-D" TSW-104-07-G-D 3729.92,9540 r270 top
J41 "TSW-102-07-G-S" TSW-102-07-G-S 3739.07,6880.73 r180 top
J42 "TSW-102-07-G-S" TSW-102-07-G-S 3742.4,534.73 r180 top
J43 "TSW-102-07-G-S" TSW-102-07-G-S 3425.43,7312.26 r0 top
J44 "TSW-102-07-G-S" TSW-102-07-G-S 3742.4,979.44 r180 top
J45 "TSW-102-07-G-S" TSW-102-07-G-S 6427.4,9326.54 r180 top
J46 "ASP-184330-01" ASP-184330-01#1 6488.11,7845.01 r90 bottom
J47 "TSW-102-07-G-S" TSW-102-07-G-S 5882.09,7305.18 r0 top
J48 "5-146278-4" TE_5-146278-4 5781.21,7194.68 r0 top
J49 "TSW-102-07-G-S" TSW-102-07-G-S 6663.79,9320.76 r0 top
J50 "TSW-102-07-G-S" TSW-102-07-G-S 6430.73,2980.54 r180 top
J51 "ASP-184330-01" ASP-184330-01#2 6491.44,1499.01 r90 bottom
J52 "TSW-102-07-G-S" TSW-102-07-G-S 5880.85,951.48 r0 top
J53 "5-146278-4" TE_5-146278-4 5780.4,841.39 r0 top
J54 "TSW-102-07-G-S" TSW-102-07-G-S 6667.12,2974.77 r0 top
J55 "RAPC722X" CONN_RAPC722X 6338,11599.07 r90 top
J56 "142-0701-201" Johnson_142-0701-20x 6408.9,3698.82 r270 top
J57 "142-0701-201" Johnson_142-0701-20x 6408.9,3236.82 r270 top
J58 "PEC06DAAN" CONN_PEC06DAAN 4259,10273 r0 top
J59 "TSW-116-07-G-D" TSW-116-07-G-D 2878,10273 r180 top
J60 "TSW-116-07-G-D" TSW-116-07-G-D 1021,10273 r180 top
J61 "142-0701-201" Johnson_142-0701-20x 5212.88,4087.24 r0 top
J62 "802-10-006-10-001000" Mill-Max_802-10-006-10-001000 5159,10429 r180 top
J63 "PEC06DAAN" CONN_PEC06DAAN 4507,11215 r270 top
J64 "TSW-102-07-G-S" TSW-102-07-G-S 999.68,8685.66 r0 top
J67 "TSW-102-07-G-S" TSW-102-07-G-S 721.68,8686.66 r0 top
J68 "TSW-102-07-G-S" TSW-102-07-G-S 1001.47,7263.53 r0 top
J71 "800-10-003-10-001000" Mill-Max_800-10-003-10-001000 5829,10045 r270 top
J72 "651305142821" 651305142821 6706.77,10188.8 r90 top
J73 "142-0771-831" JOHNSON_142-0771-831 0,7228.57 r90 top locked
J74 "142-0701-201" Johnson_142-0701-20x 2339.42,804.02 r90 top
J75 "800-10-003-10-001000" Mill-Max_800-10-003-10-001000 5956.31,5911.36 r270 top
J76 "142-0771-831" JOHNSON_142-0771-831 0,2860.42 r90 top locked
J77 "142-0771-831" JOHNSON_142-0771-831 0,2304.33 r90 top locked
J78 "TSW-102-07-G-S" TSW-102-07-G-S 723.47,7264.53 r0 top
J79 "TSW-102-07-G-S" TSW-102-07-G-S 1002.99,2339.29 r0 top
J80 "142-0771-831" JOHNSON_142-0771-831 0,1441.09 r90 top locked
J81 "142-0771-831" JOHNSON_142-0771-831 0,885 r90 top locked
J82 "TSW-102-07-G-S" TSW-102-07-G-S 724.99,2340.29 r0 top
J83 "TSW-102-07-G-S" TSW-102-07-G-S 1003.07,919.96 r0 top
J84 "TSW-102-07-G-S" TSW-102-07-G-S 725.07,920.96 r0 top
J85 "800-10-005-10-001000" Mill-Max_800-10-005-10-001000 5285,10663 r180 top
L1 "LQW18AN5N6D10D" LQW18A 1293.38,9011.41 r0 top
L2 "0603HC-3N9XJLU" 0603HC 1446.38,9011.41 r0 top
L3 "LQW18AN5N6D10D" LQW18A 1292.38,8856.43 r0 top
L4 "0603HC-3N9XJLU" 0603HC 1446.38,8859.02 r0 top
L5 "LQW18AN5N6D10D" LQW18A 1295.18,7589.29 r0 top
L6 "0603HC-3N9XJLU" 0603HC 1448.18,7589.29 r0 top
L7 "LQW18AN5N6D10D" LQW18A 1294.18,7434.3 r0 top
L8 "0603HC-3N9XJLU" 0603HC 1448.18,7436.9 r0 top
L9 "LQW18AN5N6D10D" LQW18A 1296.69,2665.05 r0 top
L10 "0603HC-3N9XJLU" 0603HC 1449.69,2665.05 r0 top
L11 "LQW18AN5N6D10D" LQW18A 1295.69,2510.07 r0 top
L12 "0603HC-3N9XJLU" 0603HC 1449.69,2512.66 r0 top
L13 "LQW18AN5N6D10D" LQW18A 1296.77,1245.72 r0 top
L14 "0603HC-3N9XJLU" 0603HC 1449.77,1245.72 r0 top
L15 "LQW18AN5N6D10D" LQW18A 1295.77,1090.73 r0 top
L16 "0603HC-3N9XJLU" 0603HC 1449.77,1093.33 r0 top
L17 "LQG15HS18NJ02D" IND_LQG15H 2216.07,6393.77 r270 top
L18 "LQG15HS18NJ02D" IND_LQG15H 2468.81,6256.72 r180 top
L19 "LQG15HS18NJ02D" IND_LQG15H 2335.55,3424.2 r90 top
L20 "LQG15HS18NJ02D" IND_LQG15H 2083.09,3561.55 r0 top
L21 "BLM18SG121TN1D" 0603 5512.38,5611.02 r90 bottom
L22 "BLM18AG121SN1D" 0603 4846.97,4761.02 r90 bottom
L23 "BLM18AG121SN1D" 0603 4350.97,4648.02 r90 top
L24 "BLM18AG121SN1D" 0603 4565.97,4652.02 r90 bottom
L25 "BLM18AG121SN1D" 0603 4627.97,4652.02 r90 bottom
L26 "BLM18AG121SN1D" 0603 4876.97,4904.02 r180 bottom
L27 "BLM18AG121SN1D" 0603 4876.97,4969.02 r180 bottom
L28 "BLM18AG121SN1D" 0603 4876.97,5031.02 r180 bottom
L29 "BLM18AG121SN1D" 0603 4908.97,5142.02 r270 bottom
L30 "BLM18AG121SN1D" 0603 4737.55,5168.44 r180 bottom
L31 "BLM18AG121SN1D" 0603 4365.97,5207.02 r270 top
L32 "BLM18SG260TN1D" 0603 5630.88,9695.97 r90 bottom
L33 "BLM18SG260TN1D" 0603 5662.88,9959.97 r180 bottom
L34 "BLM18SG260TN1D" 0603 6134.57,9947.19 r270 top
L35 "BLM41PG102SN1L" 1806_HIGHSPEED 2164.06,7870.63 r0 bottom
L36 "BLM41PG102SN1L" 1806_HIGHSPEED 2160,1520 r0 bottom
L37 "BLM41PG102SN1L" 1806_HIGHSPEED 2100.63,8620.28 r270 bottom
L38 "BLM41PG102SN1L" 1806_HIGHSPEED 2090,2270 r270 bottom
L39 "BLM41PG102SN1L" 1806_HIGHSPEED 2835.03,9168.65 r180 bottom
L40 "BLM41PG102SN1L" 1806_HIGHSPEED 2902.79,2815.24 r180 bottom
L41 "BLM41PG102SN1L" 1806_HIGHSPEED 1650.17,5119.8 r90 top
L42 "BLM41PG102SN1L" 1806_HIGHSPEED 2910.8,6136.28 r90 top
L43 "BLM41PG102SN1L" 1806_HIGHSPEED 1431.34,4712.4 r270 top
L44 "BLM41PG102SN1L" 1806_HIGHSPEED 1401.43,4288.16 r0 top
L45 "BLM41PG102SN1L" 1806_HIGHSPEED 5297.23,3637.01 r90 top
L46 "BLM41PG102SN1L" 1806_HIGHSPEED 5921,5245 r90 top
L47 "BLM41PG102SN1L" 1806_HIGHSPEED 4649.85,10620.25 r270 top
L52 "BLM18SG121TN1D" 0603 977.91,9419.79 r180 top
L53 "BLM18SG121TN1D" 0603 981,3070.36 r180 top
L54 "BLM18SG121TN1D" 0603 979.71,7997.66 r180 top
L55 "BLM18SG121TN1D" 0603 979.88,1655.08 r180 top
L56 "BLM18SG121TN1D" 0603 5788.35,6058.72 r90 bottom
L57 "880Ω" "WE-CBF_1812_High Current" 2878,11112 r180 top
L58 "880Ω" "WE-CBF_1812_High Current" 2008,11112 r180 top
L59 "880Ω" "WE-CBF_1812_High Current" 3716,11112 r180 top
L61 "BLM18SG121TN1D" 0603 753.11,8336.91 r0 bottom
L63 "BLM18SG121TN1D" 0603 756.71,6915.66 r0 bottom
L65 "BLM18SG121TN1D" 0603 759.02,1991.41 r0 bottom
L67 "BLM18SG121TN1D" 0603 758.48,570.45 r0 bottom
L68 "880Ω" "WE-CBF_1812_High Current" 1266.7,11112 r180 top
L69 "880Ω" "WE-CBF_1812_High Current" 454,11031 r180 top
L72 "BLM41PG102SN1L" 1806_HIGHSPEED 6763.11,9780.8 r0 top
L73 "BLM41PG102SN1L" 1806_HIGHSPEED 2792,4563 r270 top
L74 "BLM41PG102SN1L" 1806_HighSpeed 3578,10273 r90 bottom
L75 "WE-LPF, 748112024" WE-LPF_0603 1721.38,9011 r90 top
L76 "WE-LPF, 748112024" WE-LPF_0603 1721.38,8859 r90 top
L77 "WE-LPF, 748112024" WE-LPF_0603 1723.18,7588.87 r90 top
L78 "WE-LPF, 748112024" WE-LPF_0603 1723.18,7436.87 r90 top
L79 "WE-LPF, 748112024" WE-LPF_0603 1724.69,2664.64 r90 top
L80 "WE-LPF, 748112024" WE-LPF_0603 1724.69,2512.64 r90 top
L81 "WE-LPF, 748112024" WE-LPF_0603 1724.77,1245.3 r90 top
L82 "WE-LPF, 748112024" WE-LPF_0603 1724.77,1093.3 r90 top
L83 "BLM41PG102SN1L" 1806_HighSpeed 3077,10270 r90 bottom
L84 "BLM41PG102SN1L" 1806_HighSpeed 2577,10272 r90 bottom
L85 "BLM41PG102SN1L" 1806_HighSpeed 1719,10273 r90 bottom
L86 "BLM41PG102SN1L" 1806_HighSpeed 920,10270 r90 bottom
L87 "BLM41PG102SN1L" 1806_HighSpeed 3186,11467 r0 bottom
L88 "BLM41PG102SN1L" 1806_HighSpeed 2322,11464 r0 bottom
L89 "BLM41PG102SN1L" 1806_HighSpeed 4036,11466.92 r0 bottom
L90 "BLM41PG102SN1L" 1806_HighSpeed 1616,11471 r0 bottom
L91 "BLM41PG102SN1L" 1806_HighSpeed 939,11467.92 r180 bottom
L92 "BLM41PG102SN1L" 1806_HighSpeed 4285,11415 r180 top
L93 "30Ω" "WE-CBF_1210_High Current" 2204.76,8726.19 r270 top
L94 "30Ω" "WE-CBF_1210_High Current" 2199,2376.87 r270 top
L95 "30Ω" "WE-CBF_1210_High Current" 2175,7821 r90 top
L96 "30Ω" "WE-CBF_1210_High Current" 2178,1463 r90 top
LBL1 "Size: 0.65\" x 0.20 \"" Label_650x200 662,4053 r180 top
Logo1 "ESD Susceptible" ESD_Overlay_Large 4996.03,3038.52 r0 top
Logo2 "Pb-Free Symbol" Pb-Free_Overlay_Small 600.6,3619 r0 top
Logo3 "FCC disclaimer" FCC_disclaimer 4085,798 r90 top
Logo4 "EU RoHS Exempt Logo" EURoHS_Exempt_60mil 7277.6,3778 r90 top
Logo5 "CAUTION.  READ USER GUIDE BEFORE USE" IEC_Caution_Medium 2948.36,345 r0 top
LOGO6 "CAUTION HOT SURFACE" IEC_HotSurface_small 2640.04,11486.92 r0 top
LOGO7 "CAUTION HOT SURFACE" IEC_HotSurface_small 299,8326 r0 top
LOGO8 "CAUTION HOT SURFACE" IEC_HotSurface_small 353.79,2002 r0 top
LOGO9 "CAUTION HOT SURFACE" IEC_HotSurface_small 617.04,11477.92 r0 top
OSCinM1 "142-0701-201" JOHNSON_142-0701-20X 2536.66,5135.32 r90 top
OSCinM2 "142-0701-201" Johnson_142-0701-20x 2014.46,4682.16 r270 top
OSCinM3 "142-0701-201" Johnson_142-0701-20x 5262.06,6476.85 r0 top
OSCinP1 "142-0701-201" JOHNSON_142-0701-20X 2014.46,5135.82 r90 top
OSCinP2 "142-0701-201" Johnson_142-0701-20x 2537.16,4682.16 r270 top
OSCinP3 "142-0701-201" Johnson_142-0701-20x 5809.06,6476.85 r0 top
Q1 "MMBT3904" SOT-23 2734.1,9446.65 r180 top
Q2 "MMBT3904" SOT-23 2802.43,3100.88 r180 top
Q3 "CSD15571Q2" DQK0006C 5038.41,11442.42 r270 top
R1 "CRCW04022K00FKED" 0402#1 729.91,9210.79 r90 top
R2 "CRCW04020000Z0ED" 0402#1 738.91,9125.99 r0 top
R3 "CRCW04022K00FKED" 0402#1 628.91,9209.61 r270 top
R4 "CRCW04024R99FKED" 0402#1 1607.38,9011 r0 top
R5 "ERJ-2RKF1001X" 0402#1 446.92,8986.28 r225 top
R6 "CRCW0402127RFKED" 0402#1 533,8964 r0 top
R7 "CRCW04021K21FKED" 0402#1 1523.38,8987.42 r90 top
R8 "CRCW040222R6FKED" 0402#1 372.5,9094.97 r315 top
R9 "CRCW04020000Z0ED" 0402#1 788.91,8960.99 r0 top
R10 "CRCW04020000Z0ED" 0402#1 894.09,8961.26 r180 top
R11 "CRCW040240R2FKED" 0402#1 1189.62,8959 r180 top
R12 "CRCW040222R6FKED" 0402#1 373.3,8767.3 r45 top
R13 "CRCW04020000Z0ED" 0402#1 788.91,8900.99 r0 top
R14 "CRCW04020000Z0ED" 0402#1 894.09,8901.26 r180 top
R15 "CRCW040240R2FKED" 0402#1 1189.62,8909 r180 top
R16 "CRCW0402127RFKED" 0402#1 533,8897 r0 top
R17 "CRCW04021K21FKED" 0402#1 1523.38,8880.02 r270 top
R18 "CRCW04024R99FKED" 0402#1 1607.38,8859.02 r0 top
R19 "ERJ-2RKF1001X" 0402#1 446.92,8874.7 r315 top
R20 "CRCW0402365RFKED" 0402#1 302.5,9024.97 r315 top
R21 "CRCW0402365RFKED" 0402#1 303.3,8837.3 r45 top
R22 "CRCW040210K0FKED" 0402#1 1539.09,8701.26 r0 top
R23 "CRCW04020000Z0ED" 0402#1 1284.09,8701.26 r180 top
R24 "CRCW04020000Z0ED" 0402#1 1429.09,8596.26 r180 top
R25 "CRCW04022K00FKED" 0402#1 731.71,7788.66 r90 top
R26 "CRCW04020000Z0ED" 0402#1 740.71,7703.86 r0 top
R27 "CRCW04022K00FKED" 0402#1 630.71,7787.48 r270 top
R28 "CRCW04024R99FKED" 0402#1 1609.18,7588.87 r0 top
R29 "ERJ-2RKF1001X" 0402#1 448.72,7564.15 r225 top
R30 "CRCW0402127RFKED" 0402#1 534.8,7541.87 r0 top
R31 "CRCW04021K21FKED" 0402#1 1525.18,7565.3 r90 top
R32 "CRCW040222R6FKED" 0402#1 374.3,7672.84 r315 top
R33 "CRCW04020000Z0ED" 0402#1 790.71,7538.86 r0 top
R34 "CRCW04020000Z0ED" 0402#1 895.89,7539.13 r180 top
R35 "CRCW040240R2FKED" 0402#1 1191.42,7536.87 r180 top
R36 "CRCW040222R6FKED" 0402#1 375.09,7345.17 r45 top
R37 "CRCW04020000Z0ED" 0402#1 790.71,7478.86 r0 top
R38 "CRCW04020000Z0ED" 0402#1 895.89,7479.13 r180 top
R39 "CRCW040240R2FKED" 0402#1 1191.42,7486.87 r180 top
R40 "CRCW0402127RFKED" 0402#1 534.8,7474.87 r0 top
R41 "CRCW04021K21FKED" 0402#1 1525.18,7457.9 r270 top
R42 "CRCW04024R99FKED" 0402#1 1609.18,7436.9 r0 top
R43 "ERJ-2RKF1001X" 0402#1 448.72,7452.58 r315 top
R44 "CRCW0402365RFKED" 0402#1 304.3,7602.84 r315 top
R45 "CRCW0402365RFKED" 0402#1 305.09,7415.17 r45 top
R46 "CRCW040210K0FKED" 0402#1 1540.89,7279.13 r0 top
R47 "CRCW04020000Z0ED" 0402#1 1285.89,7279.13 r180 top
R48 "CRCW04020000Z0ED" 0402#1 1430.89,7174.13 r180 top
R49 "CRCW04028K06FKED" 0402#1 5286.21,7277.18 r0 top
R50 "CRCW04021K20JNED" 0402#1 4910.21,7409.18 r180 top
R51 "ERJ-2RKF1004X" 0402#1 4840.21,7154.18 r90 top
R52 "ERJ-2RKF1002X" 0402#1 3573.08,9271.88 r180 bottom
R53 "ERJ-2RKF1002X" 0402#1 3573.08,9172.88 r180 bottom
R54 "ERJ-2RKF1001X" 0402#1 3891.8,9271.99 r180 bottom
R55 "ERJ-2RKF1001X" 0402#1 3891.8,9171.99 r180 bottom
R56 "ERJ-2RKF1001X" 0402#1 3891.8,9071.99 r180 bottom
R57 "ERJ-2RKF1001X" 0402#1 3891.8,8970.99 r180 bottom
R58 "ERJ-2RKF1002X" 0402#1 3573.08,9071.88 r180 bottom
R59 "ERJ-2RKF1002X" 0402#1 3573.08,8971.88 r180 bottom
R60 "CRCW04021K33FKED" 0402#1 5286.21,7228.18 r180 top
R61 "CRCW04021K20JNED" 0402#1 5314.21,7394.18 r180 top
R62 "ERJ-2RKF1004X" 0402#1 5308.21,7102.18 r90 top
R63 "ERJ-2RKF1001X" 0402#1 3080.3,9260.91 r0 bottom
R64 "ERJ-2RKF1001X" 0402#1 3217.3,9260.91 r180 bottom
R65 "ERJ-2RKF1002X" 0402#1 3081.3,8991.91 r180 bottom
R66 "ERJ-2RKF1002X" 0402#1 3214.3,8991.91 r0 bottom
R67 "CRCW04020000Z0ED" 0402#1 1994.48,8502.3 r0 top
R68 "CRCW04020000Z0ED" 0402#1 2018.1,8478.68 r90 top
R69 "CRCW04020000Z0ED" 0402#1 2018.1,8372.92 r270 top
R70 "CRCW04020000Z0ED" 0402#1 1994.48,8349.3 r0 top
R71 "ERJ-2RKF1001X" 0402#1 2116.17,8376.09 r90 bottom
R72 "CRCW04022K10FKED" 0402#1 2166.17,8376.09 r270 bottom
R73 "CRCW0402100RFKED" 0402#1 1906.17,8223.5 r90 top
R74 "ERJ-2RKF1002X" 0402#1 3215.1,9447.03 r0 top
R75 "ERJ-2RKF1002X" 0402#1 3215.1,9510.03 r0 top
R76 "ERJ-2RKF1002X" 0402#1 3089.1,9623.03 r180 top
R77 "CRCW0603750RJNEA" 0603 3191.1,9349.03 r270 top
R78 "CRCW04020000Z0ED" 0402#1 2603.93,9568.94 r90 bottom
R79 "CRCW04020000Z0ED" 0402#1 2360.16,9568.55 r90 bottom
R80 "RC0603JR-071K3L" 0603 3219.1,9567.03 r0 top
R81 "RC0603JR-071K3L" 0603 3219.1,9630.03 r0 top
R82 "CRCW04022K00FKED" 0402#1 733.23,2864.42 r90 top
R83 "CRCW04020000Z0ED" 0402#1 742.23,2779.63 r0 top
R84 "CRCW04022K00FKED" 0402#1 632.23,2863.25 r270 top
R85 "CRCW04024R99FKED" 0402#1 1610.69,2664.64 r0 top
R86 "ERJ-2RKF1001X" 0402#1 450.24,2639.91 r225 top
R87 "CRCW0402127RFKED" 0402#1 536.32,2617.64 r0 top
R88 "CRCW04021K21FKED" 0402#1 1526.69,2641.06 r90 top
R89 "CRCW040222R6FKED" 0402#1 375.82,2748.61 r315 top
R90 "CRCW04020000Z0ED" 0402#1 792.23,2614.63 r0 top
R91 "CRCW04020000Z0ED" 0402#1 897.41,2614.9 r180 top
R92 "CRCW040240R2FKED" 0402#1 1192.94,2612.64 r180 top
R93 "CRCW040222R6FKED" 0402#1 376.61,2420.93 r45 top
R94 "CRCW04020000Z0ED" 0402#1 792.23,2554.63 r0 top
R95 "CRCW04020000Z0ED" 0402#1 897.41,2554.9 r180 top
R96 "CRCW040240R2FKED" 0402#1 1192.94,2562.64 r180 top
R97 "CRCW0402127RFKED" 0402#1 536.32,2550.64 r0 top
R98 "CRCW04021K21FKED" 0402#1 1526.69,2533.66 r270 top
R99 "CRCW04024R99FKED" 0402#1 1610.69,2512.66 r0 top
R100 "ERJ-2RKF1001X" 0402#1 450.24,2528.34 r315 top
R101 "CRCW0402365RFKED" 0402#1 305.82,2678.61 r315 top
R102 "CRCW0402365RFKED" 0402#1 306.61,2490.93 r45 top
R103 "CRCW040210K0FKED" 0402#1 1542.41,2354.9 r0 top
R104 "CRCW04020000Z0ED" 0402#1 1287.41,2354.9 r180 top
R105 "CRCW04020000Z0ED" 0402#1 1432.41,2249.9 r180 top
R106 "CRCW04022K00FKED" 0402#1 733.3,1445.09 r90 top
R107 "CRCW04020000Z0ED" 0402#1 742.3,1360.29 r0 top
R108 "CRCW04022K00FKED" 0402#1 632.3,1443.91 r270 top
R109 "CRCW04024R99FKED" 0402#1 1610.77,1245.3 r0 top
R110 "ERJ-2RKF1001X" 0402#1 450.31,1220.58 r225 top
R111 "CRCW0402127RFKED" 0402#1 536.39,1198.3 r0 top
R112 "CRCW04021K21FKED" 0402#1 1526.77,1221.73 r90 top
R113 "CRCW040222R6FKED" 0402#1 375.9,1329.27 r315 top
R114 "CRCW04020000Z0ED" 0402#1 792.3,1195.29 r0 top
R115 "CRCW04020000Z0ED" 0402#1 897.48,1195.56 r180 top
R116 "CRCW040240R2FKED" 0402#1 1193.01,1193.3 r180 top
R117 "CRCW040222R6FKED" 0402#1 376.69,1001.6 r45 top
R118 "CRCW04020000Z0ED" 0402#1 792.3,1135.29 r0 top
R119 "CRCW04020000Z0ED" 0402#1 897.48,1135.56 r180 top
R120 "CRCW040240R2FKED" 0402#1 1193.01,1143.3 r180 top
R121 "CRCW0402127RFKED" 0402#1 536.39,1131.3 r0 top
R122 "CRCW04021K21FKED" 0402#1 1526.77,1114.33 r270 top
R123 "CRCW04024R99FKED" 0402#1 1610.77,1093.33 r0 top
R124 "ERJ-2RKF1001X" 0402#1 450.31,1109.01 r315 top
R125 "CRCW0402365RFKED" 0402#1 305.9,1259.27 r315 top
R126 "CRCW0402365RFKED" 0402#1 306.69,1071.6 r45 top
R127 "CRCW040210K0FKED" 0402#1 1542.48,935.56 r0 top
R128 "CRCW04020000Z0ED" 0402#1 1287.48,935.56 r180 top
R129 "CRCW04020000Z0ED" 0402#1 1432.48,830.56 r180 top
R130 "CRCW04028K06FKED" 0402#1 5369.3,869.25 r0 top
R131 "CRCW04021K20JNED" 0402#1 4993.3,1001.25 r180 top
R132 "ERJ-2RKF1004X" 0402#1 4923.3,746.25 r90 top
R133 "ERJ-2RKF1002X" 0402#1 3654.72,2986.99 r180 bottom
R134 "ERJ-2RKF1002X" 0402#1 3654.72,2887.99 r180 bottom
R135 "ERJ-2RKF1001X" 0402#1 3968.72,2986.99 r180 bottom
R136 "ERJ-2RKF1001X" 0402#1 3968.72,2886.99 r180 bottom
R137 "ERJ-2RKF1001X" 0402#1 3968.72,2786.99 r180 bottom
R138 "ERJ-2RKF1001X" 0402#1 3968.72,2685.99 r180 bottom
R139 "ERJ-2RKF1002X" 0402#1 3654.72,2786.99 r180 bottom
R140 "ERJ-2RKF1002X" 0402#1 3654.72,2686.99 r180 bottom
R141 "CRCW04021K33FKED" 0402#1 5369.3,820.25 r180 top
R142 "CRCW04021K20JNED" 0402#1 5397.3,986.25 r180 top
R143 "ERJ-2RKF1004X" 0402#1 5391.3,694.25 r90 top
R144 "ERJ-2RKF1001X" 0402#1 3149.99,2905.76 r0 bottom
R145 "ERJ-2RKF1001X" 0402#1 3280.28,2906.49 r180 bottom
R146 "ERJ-2RKF1002X" 0402#1 3150.28,2645.49 r180 bottom
R147 "ERJ-2RKF1002X" 0402#1 3268.28,2645.49 r0 bottom
R148 "CRCW04020000Z0ED" 0402#1 1987.5,2155.51 r0 top
R149 "CRCW04020000Z0ED" 0402#1 2011.12,2131.88 r90 top
R150 "CRCW04020000Z0ED" 0402#1 2011.12,2026.13 r270 top
R151 "CRCW04020000Z0ED" 0402#1 1987.5,2002.51 r0 top
R152 "ERJ-2RKF1001X" 0402#1 2109.5,2032.1 r90 bottom
R153 "CRCW04022K10FKED" 0402#1 2159.5,2032.1 r270 bottom
R154 "CRCW0402100RFKED" 0402#1 1909.5,1876.1 r90 top
R155 "ERJ-2RKF1002X" 0402#1 3283.43,3101.26 r0 top
R156 "ERJ-2RKF1002X" 0402#1 3283.43,3164.26 r0 top
R157 "ERJ-2RKF1002X" 0402#1 3157.43,3277.26 r180 top
R158 "CRCW0603750RJNEA" 0603 3259.43,3003.26 r270 top
R159 "CRCW04020000Z0ED" 0402#1 2669.26,3222.95 r90 bottom
R160 "CRCW04020000Z0ED" 0402#1 2425.49,3222.55 r90 bottom
R161 "RC0603JR-071K3L" 0603 3287.43,3221.26 r0 top
R162 "RC0603JR-071K3L" 0603 3287.43,3284.26 r0 top
R163 "CRCW04021K50JNED" 0402#1 5872.89,6034.98 r90 top
R164 "FC0402E50R0BST1" 0402L 2236.04,6343.87 r180 top
R165 "CRCW06030000Z0EA" 0603 2245.1,5836.81 r90 bottom
R166 "CRCW04021K50JNED" 0402#1 5872.89,5787.73 r90 top
R167 "CRCW06030000Z0EA" 0603L 2436.28,6033.92 r180 bottom
R168 "FC0402E50R0BST1" 0402L 2311.5,6343.55 r0 top
R169 "CRCW06030000Z0EA" 0603L 2362.81,6338.72 r180 bottom
R170 "CRCW06030000Z0EA" 0603L 2404.81,6165.72 r270 bottom
R171 "CRCW06030000Z0EA" 0603 2069.93,6477.29 r180 top
R172 "CRCW0603100KJNEA" 0603 2108.66,5888.82 r90 top
R173 "CRCW06030000Z0EA" 0603 1938.66,5991.92 r180 top
R174 "CRCW12060000Z0EA" 1206 2775.51,10273 r270 bottom
R175 "FC0402E50R0BST1" 0402L 2418.59,6161.28 r90 top
R176 "RC0603JR-07270RL" 0603 2463.66,5788.82 r315 top
R177 "CRCW06030000Z0EA" 0603 2509.66,5835.72 r315 top
R178 "CRCW04020000Z0ED" 0402#1 2105.31,6004.52 r180 bottom
R179 "RT0603DRE07120RL" 0603 2648.28,5788.92 r315 top
R180 "FC0402E50R0BST1" 0402L 2418.91,6236.74 r90 top
R181 "CRCW12060000Z0EA" 1206 2178.67,10269.76 r270 bottom
R182 "CRCW040210K0DHEDP" 0402#1 2105.31,5955.52 r180 bottom
R183 "CRCW040210K0DHEDP" 0402#1 2072.31,6308.52 r180 bottom
R184 "CRCW04020000Z0ED" 0402#1 2096.31,6220.52 r270 bottom
R185 "CRCW04020000Z0ED" 0402#1 2252.86,5453.63 r270 top
R186 "CRCW12060000Z0EA" 1206 3275.55,10271.77 r270 bottom
R187 "CRCW0603100RFKEA" 0603 2435.81,6503.72 r90 top
R188 "CRCW12060000Z0EA" 1206 319.56,10274.76 r270 bottom
R189 "CRCW060351R0JNEA" 0603 1983.66,5542.82 r180 top
R190 "RC0603JR-07330RL" 0603 2467.81,6406.72 r180 top
R191 "CRCW06030000Z0EA" 0603 2014.46,5445.82 r90 top
R192 "CRCW06030000Z0EA" 0603 2092.26,5616.42 r45 top
R193 "CRCW04020000Z0ED" 0402#1 1532.81,5730.14 r270 bottom
R194 "CRCW0402100RJNED" 0402#1 1559.66,5559.32 r180 bottom
R195 "CRCW04020000Z0ED" 0402#1 1984.54,8292.24 r180 top
R196 "CRCW0603100RFKEA" 0603L 2273.66,5788.82 r180 top
R197 "CRCW04020000Z0ED" 0402#1 1984.54,8157.76 r180 top
R198 "CRCW06030000Z0EA" 0603 2537.16,5445.82 r90 top
R199 "CRCW06030000Z0EA" 0603 2459.26,5617.42 r315 top
R200 "CRCW04020000Z0ED" 0402#1 1482.81,5730.52 r90 bottom
R201 "CRCW0402100RJNED" 0402#1 1459.66,5559.32 r180 bottom
R202 "CRCW060351R0JNEA" 0603 2568.66,5542.82 r180 top
R203 "CRCW04020000Z0ED" 0402#1 2301.86,5453.63 r90 top
R204 "CRCW12060000Z0EA" 1206 1423.01,10276.14 r270 bottom
R205 "FC0402E50R0BST1" 0402L 2315.57,3474.1 r0 top
R206 "CRCW06030000Z0EA" 0603 2306.51,3981.17 r270 bottom
R207 "CRCW12060000Z0EA" 1206 1217.04,10271.76 r270 bottom
R208 "CRCW06030000Z0EA" 0603L 2115.34,3784.06 r0 bottom
R209 "FC0402E50R0BST1" 0402L 2240.11,3474.42 r180 top
R210 "CRCW06030000Z0EA" 0603L 2183.88,3477.61 r0 bottom
R211 "CRCW06030000Z0EA" 0603L 2142.48,3650.01 r90 bottom
R212 "CRCW06030000Z0EA" 0603 2482.39,3339.98 r0 top
R213 "CRCW0603100KJNEA" 0603 2442.96,3929.16 r270 top
R214 "CRCW06030000Z0EA" 0603 2612.96,3826.06 r0 top
R215 "CRCW12060000Z0EA" 1206 623.55,10273.97 r270 bottom
R216 "FC0402E50R0BST1" 0402L 2133.02,3656.69 r270 top
R217 "CRCW06030000Z0EA" 0603 2041.96,3983.16 r135 top
R218 "RC0603JR-07270RL" 0603 2086.6,4027.8 r135 top
R219 "CRCW04020000Z0ED" 0402#1 2446.3,3813.45 r0 bottom
R220 "RT0603DRE07120RL" 0603 1903.34,4029.06 r135 top
R221 "FC0402E50R0BST1" 0402L 2132.7,3581.23 r270 top
R222 "CRCW06030000Z0EA" 0603 3168,11189 r90 top
R223 "CRCW040210K0DHEDP" 0402#1 2446.3,3862.45 r0 bottom
R224 "CRCW040210K0DHEDP" 0402#1 2479.3,3509.45 r0 bottom
R225 "CRCW04020000Z0ED" 0402#1 2455.3,3597.45 r90 bottom
R226 "CRCW04020000Z0ED" 0402#1 2299.16,4363.73 r90 top
R227 "CRCW0603100RFKEA" 0603 2115.3,3314.76 r270 top
R228 "ERJ-2RKF1002X" 0402#1 4345.89,5057 r0 bottom
R229 "CRCW04020000Z0ED" 0402#1 5679,3451 r270 bottom
R230 "CRCW060351R0JNEA" 0603 2567.96,4275.16 r0 top
R231 "RC0603JR-07330RL" 0603 2083.8,3411.26 r0 top
R232 "CRCW06030000Z0EA" 0603 2537.16,4372.16 r270 top
R233 "CRCW06030000Z0EA" 0603 2459.36,4201.56 r225 top
R234 "CRCW04020000Z0ED" 0402#1 3018.8,4087.83 r90 bottom
R235 "CRCW0402100RJNED" 0402#1 2992.46,4261.16 r0 bottom
R236 "CRCW04020000Z0ED" 0402#1 1987.88,1944.84 r180 top
R237 "CRCW0603100RFKEA" 0603L 2277.96,4029.16 r0 top
R238 "CRCW04020000Z0ED" 0402#1 1987.88,1810.35 r180 top
R239 "CRCW04020000Z0ED" 0402#1 3067.83,4087.94 r270 bottom
R240 "CRCW0402100RJNED" 0402#1 3091.46,4261.16 r0 bottom
R241 "CRCW06030000Z0EA" 0603 2014.46,4372.16 r270 top
R242 "CRCW06030000Z0EA" 0603 2092.36,4204.05 r135 top
R243 "CRCW060351R0JNEA" 0603 1982.96,4275.16 r0 top
R244 "CRCW04020000Z0ED" 0402#1 2248.66,4364.22 r270 top
R245 "CRCW04020000Z0ED" 0402#1 3164.5,5107.79 r90 top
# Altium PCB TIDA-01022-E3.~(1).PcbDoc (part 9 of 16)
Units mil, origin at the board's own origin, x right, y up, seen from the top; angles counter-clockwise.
Board outline 6929.13 x 11614.17 mil, 12 copper layers (L1_Top Layer, L2_GND, L3_GND, L4_Signal Layer 1, L5_GND, L6_PWR, L7_GND/PWR, L8_PWR, L9_GND/PWR, L10_Signal Layer 2, L11_GND, L12_Bottom Layer), stack 64.6 mil thick; 1733 components, 993 nets, 5987 pads, 3555 vias.

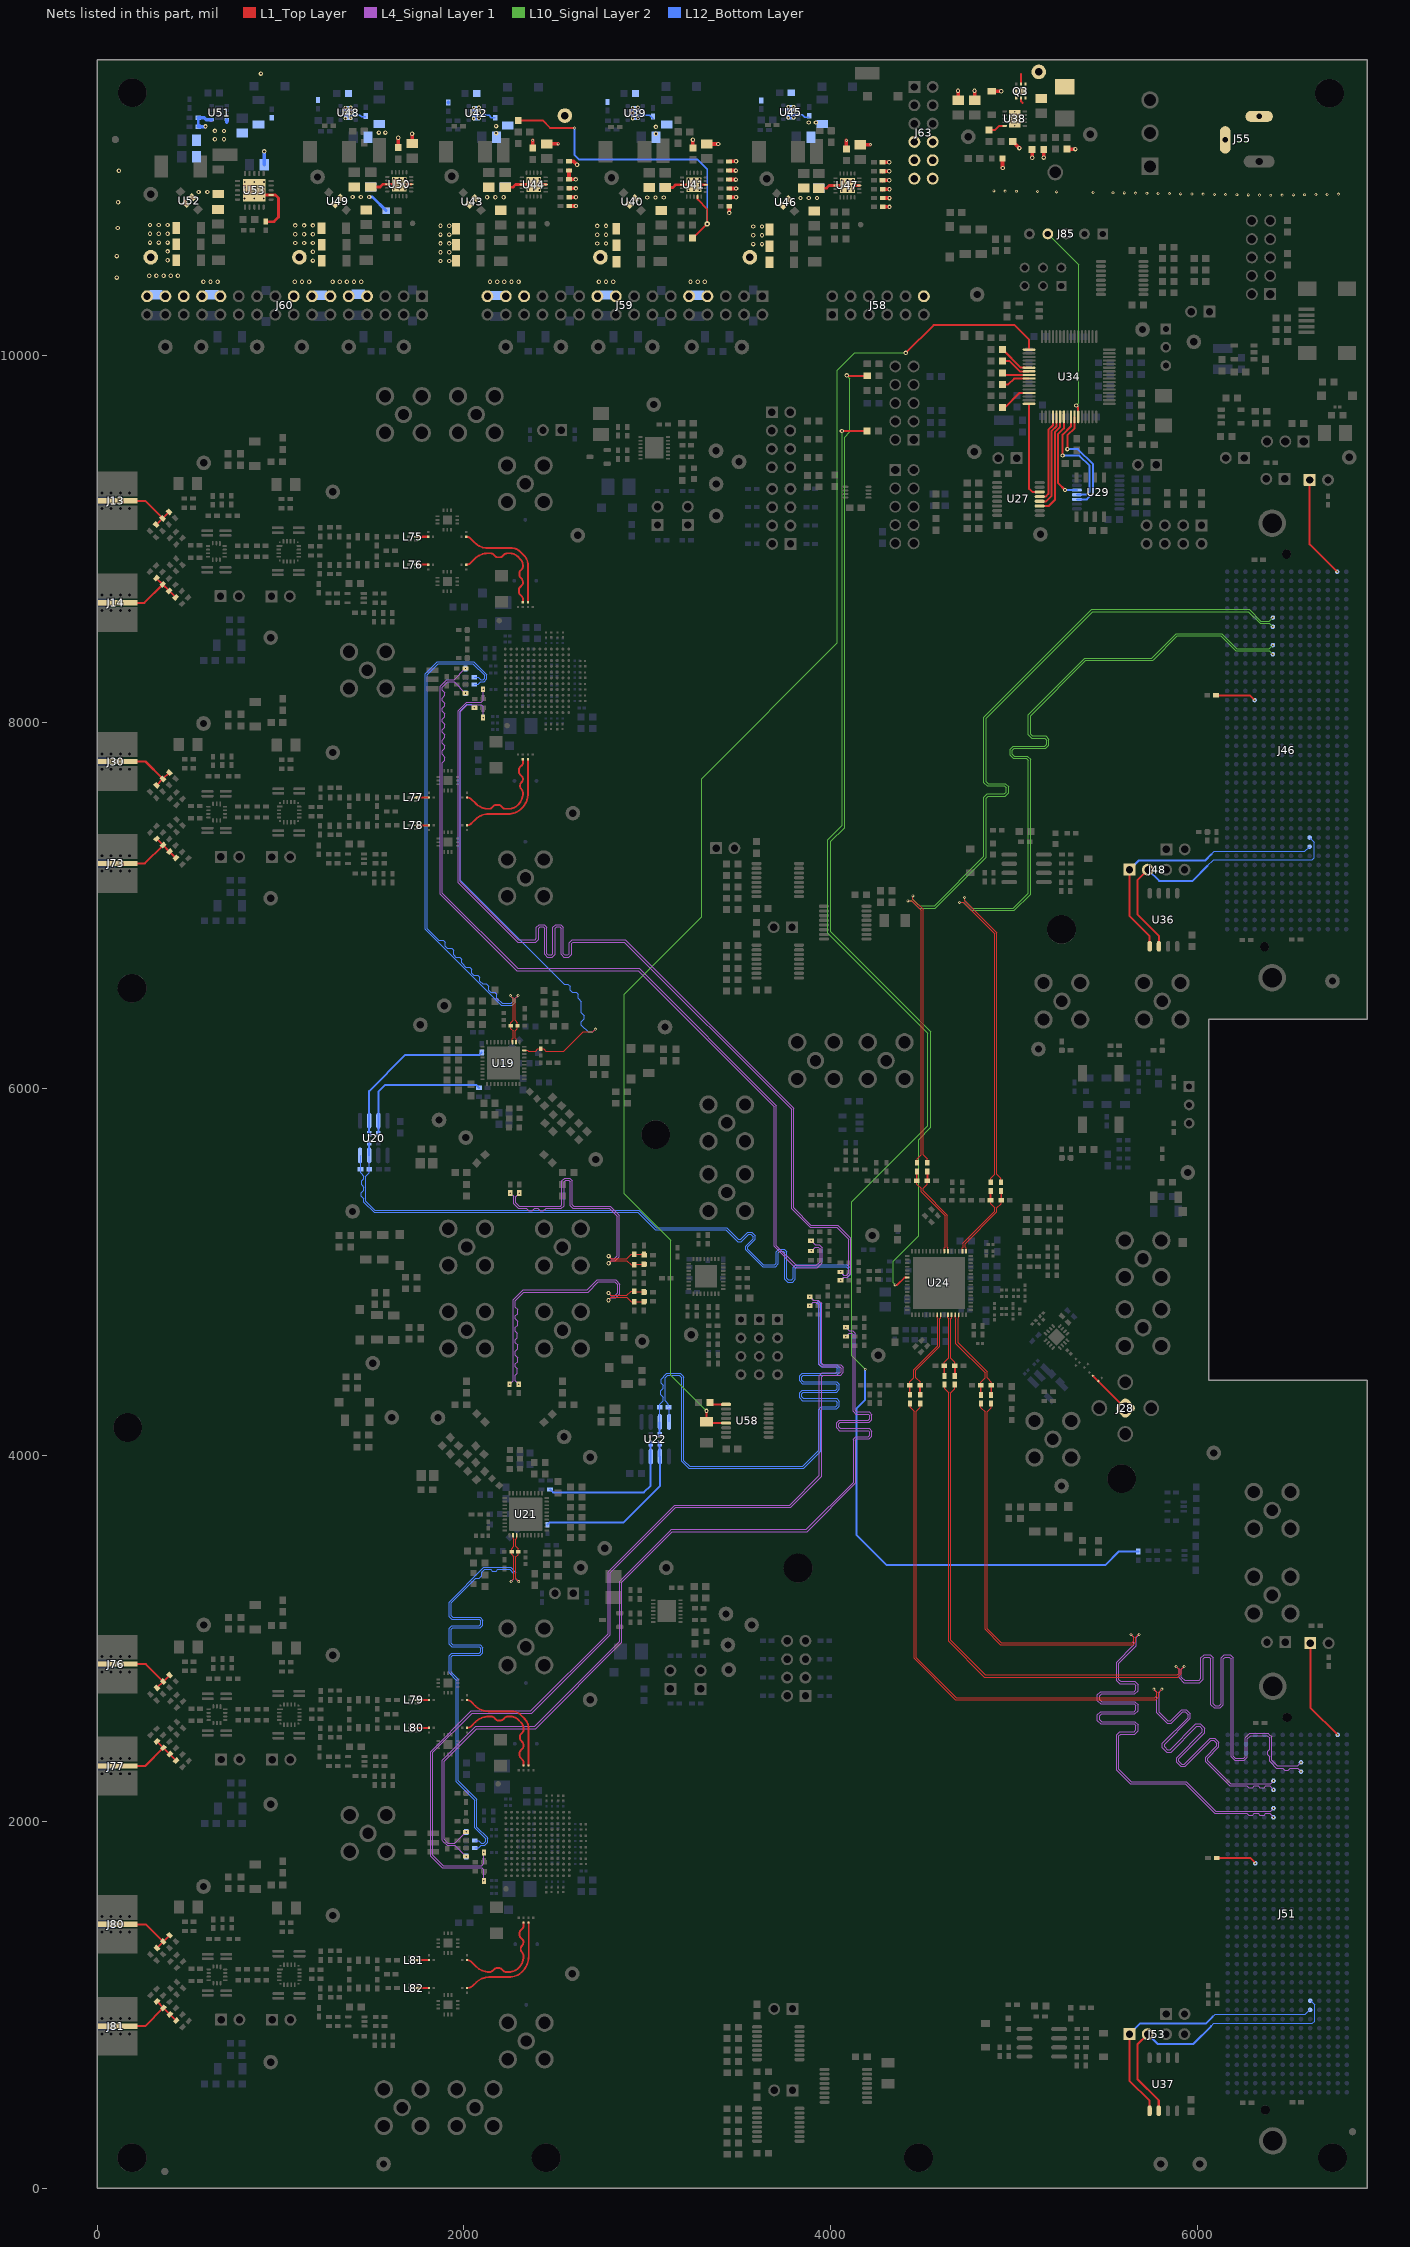
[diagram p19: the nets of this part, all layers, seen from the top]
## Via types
v1: diameter 16, hole 8, L1_Top Layer to L12_Bottom Layer, tented both sides, 1686 vias
v2: diameter 24, hole 12, L1_Top Layer to L12_Bottom Layer, tented both sides, 1590 vias
v3: diameter 20, hole 10, L1_Top Layer to L12_Bottom Layer, 279 vias

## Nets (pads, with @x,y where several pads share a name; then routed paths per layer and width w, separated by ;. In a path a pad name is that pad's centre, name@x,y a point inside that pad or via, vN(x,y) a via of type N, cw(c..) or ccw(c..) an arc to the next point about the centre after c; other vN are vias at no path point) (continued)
F_CORECLK2+: R310.1 R337.2 U24.27 | length 344.5
  L1_Top Layer w6: R337.2@4620.25,4488.95 4620.25,4506.76 4644.82,4531.32 4644.82,4744.34 4640.47,4748.69 U24.27@4640.47,4766.5
  L1_Top Layer w10: R310.1@4620.25,4433.95 R337.2@4620.25,4488.95
F_CORECLK2-: R313.1 R336.2 U24.28 | length 343.5
  L1_Top Layer w6: U24.28@4660.16,4766.5 4660.16,4748.69 4655.82,4744.34 4655.82,4528.95 4678.01,4506.76 R336.2@4678.01,4488.95
  L1_Top Layer w10: R313.1@4678.01,4433.95 R336.2@4678.01,4488.95
F_CORECLK2_N: J51.D5 R313.2 | length 5004.6
  L1_Top Layer w6: R313.2@4676.63,4385.32 4676.63,4363.58 4654.63,4341.58 4654.63,2990.37 4844,2801 5891,2801 5901,2811 5901,2831 v1(5885,2847)
  L4_Signal Layer 1 w4.9: v1(5885,2847) 5901,2831 5901,2785.03 5926.03,2760 6015.21,2760 6032.45,2777.24 6032.45,2888.79 6042.66,2899 6065.14,2899 6075.35,2888.79 6075.35,2638.24 6092.59,2621 6125.01,2621 6142.25,2638.24 6142.25,2888.79 6152.46,2899 6174.94,2899 6185.15,2888.79 6185.15,2353.88 6204.03,2335 6257.97,2335 6274,2351.03 6274,2453 6291,2470 6383,2470 6395,2458 6395,2396.81 6384,2385.81 6384,2366 6395,2355 6395,2330.03 6432.02,2293.01 6466.19,2293.01 6478.2,2281 6495.99,2281 6508,2293.01 6547.44,2293.01 v1(6566.44,2274.01)
F_CORECLK2_P: J51.D4 R310.2 | length 5003.1
  L1_Top Layer w6: R310.2@4621.63,4385.32 4621.63,4363.58 4643.63,4341.58 4643.63,2985.81 4839.44,2790 5895.56,2790 5896.56,2791 5908.78,2803.22 5912,2806.44 5912,2831 5928,2847 v1(5929,2847)
  L4_Signal Layer 1 w4.9: v1(5929,2847) 5913,2831 5913,2790 5931,2772 6010.24,2772 6020.45,2782.21 6020.45,2893.76 6037.69,2911 6070.11,2911 6087.35,2893.76 6087.35,2643.21 6097.56,2633 6120.04,2633 6130.25,2643.21 6130.25,2893.76 6147.49,2911 6179.91,2911 6197.15,2893.76 6197.15,2358.85 6209,2347 6253,2347 6262,2356 6262,2457.97 6286.03,2482 6387.97,2482 6391.49,2478.49 6407,2462.97 6407,2335 6436.99,2305.01 6547.44,2305.01 v1(6566.44,2324.01)
F_IN1N: L76.5 R639.2 R650.1 R652.1 | length 60.6
  L1_Top Layer w11: R639.2@1745,8859 1745.3,8858.7 R650.1@1805.01,8858.7 R650.1@1804.71,8859
F_IN1P: L75.5 R638.2 R646.1 R648.1 | length 68
  L1_Top Layer w9: L75.5@1737.13,9011 R638.2@1745,9011 ; R646.1@1804.69,9011 R646.1@1805.01,9010.68
  L1_Top Layer w11: R638.2@1745,9011 R646.1@1804.69,9011
F_IN2N: L78.5 R641.2 R658.1 R660.1 | length 60.6
  L1_Top Layer w11: R641.2@1746.8,7436.87 1747.1,7436.57 R660.1@1806.81,7436.57 ; R660.1@1808.33,7436.92 R660.1@1808.63,7436.62
F_IN2P: L77.5 R640.2 R655.1 R656.1 | length 67.6
  L1_Top Layer w9: L77.5@1738.92,7588.87 R640.2@1746.8,7588.87
  L1_Top Layer w11: R640.2@1746.8,7588.87 R656.1@1806.49,7588.87
F_IN3N: L80.5 R643.2 R666.1 R668.1 | length 60.6
  L1_Top Layer w11: R643.2@1748.32,2512.64 1748.62,2512.34 R668.1@1808.32,2512.34 ; R668.1@1808.33,2513.32 R668.1@1808.63,2513.02
F_IN3P: L79.5 R642.2 R663.1 R664.1 | length 67.6
  L1_Top Layer w9: L79.5@1740.44,2664.64 R642.2@1748.32,2664.64
  L1_Top Layer w11: R642.2@1748.32,2664.64 R664.1@1808,2664.64
F_IN4N: L82.5 R645.2 R674.1 R676.1 | length 60.6
  L1_Top Layer w11: R645.2@1748.39,1093.3 1748.69,1093 R676.1@1808.4,1093 ; R676.1@1808.33,1094.22 R676.1@1808.63,1093.92
F_IN4P: L81.5 R644.2 R671.1 R672.1 | length 67.6
  L1_Top Layer w9: L81.5@1740.52,1245.3 R644.2@1748.39,1245.3
  L1_Top Layer w11: R644.2@1748.39,1245.3 R672.1@1808.08,1245.3
F_OUT1N: R604.1 R651.1 R653.2 | length 607.8
  L1_Top Layer w10: R651.1@2012.83,8858.7 ccw(c2012.83,8892.5) 2036.73,8868.6 2059.54,8891.4 cw(c2130.25,8820.69) 2130.25,8920.69 2146.5,8920.69 cw(c2146.5,8900.85) 2160.53,8914.88 2165.57,8909.84 ; 2165.57,8909.83 2170.94,8904.46 ccw(c2184.17,8917.69) 2184.17,8898.98 2195.34,8898.98 ccw(c2195.34,8920.9) 2210.84,8905.4 2215.27,8909.83 ; 2215.27,8909.84 2220.27,8914.84 ; 2220.27,8914.84 cw(c2234.39,8900.72) 2234.39,8920.69 2251.5,8920.69 cw(c2251.5,8863.21) 2292.15,8903.85 2307.77,8888.24 cw(c2275.33,8855.8) 2321.2,8855.8 2321.2,8845.29 cw(c2301.46,8847.28) 2315.49,8833.25 2306.25,8824.01 ccw(c2315.06,8815.2) 2302.6,8815.2 2302.6,8800.1 ccw(c2316.12,8800.1) 2306.55,8790.55 2313.05,8784.05 cw(c2293.13,8764.13) 2321.3,8764.13 2321.3,8759.19 cw(c2301.46,8759.19) 2315.49,8745.16 2310.45,8740.12 2305.07,8734.75 ccw(c2318.3,8721.52) 2299.59,8721.52 2299.59,8710.35 ccw(c2321.51,8710.35) 2306.01,8694.85 2310.44,8690.42 2315.45,8685.42 cw(c2301.33,8671.3) 2321.2,8673.29 ; R604.1@2320.77,8653.3 ccw(c2319.72,8654.34) 2321.2,8654.34 2321.2,8673.29 ; 2321.3,8671.3 ccw(c2301.33,8671.3) 2321.2,8673.29
F_OUT1P: R592.1 R647.1 R649.2 | length 608.6
  L1_Top Layer w10: R647.1@2012.83,9010.68 cw(c2012.83,8976.88) 2036.73,9000.78 2059.54,8977.98 ccw(c2130.25,9048.69) 2130.25,8948.69 2263.1,8948.69 cw(c2263.1,8891.21) 2303.74,8931.85 2327.56,8908.03 cw(c2275.33,8855.8) 2349.2,8855.8 2349.2,8831 ; 2349.2,8830.06 R592.1@2349.27,8653.29 R592.1@2349.27,8653.29
F_OUT2N: R606.1 R659.1 R661.2 | length 604
  L1_Top Layer w10: R661.2@2016.45,7436.62 ccw(c2016.45,7470.42) 2040.35,7446.52 2063.15,7469.32 cw(c2133.86,7398.61) 2133.86,7498.61 2241.87,7498.61 ccw(c2241.87,7602.03) 2315,7528.9 ccw(c2231.46,7612.44) 2349.6,7612.44 2349.6,7793.24 ccw(c2347.82,7793.24) 2349.08,7794.5 R606.1@2349.08,7796.9
F_OUT2P: R605.1 R654.1 R657.2 | length 603
  L1_Top Layer w10: R657.2@2016.45,7588.6 cw(c2016.45,7554.8) 2040.35,7578.7 2063.15,7555.9 ccw(c2133.86,7626.61) 2133.86,7526.61 2137.73,7526.61 ccw(c2137.73,7546.58) 2151.85,7532.46 2156.85,7537.46 2161.28,7541.9 cw(c2176.78,7526.4) 2176.78,7548.32 2187.95,7548.32 cw(c2187.95,7529.61) 2201.18,7542.84 2206.55,7537.47 2211.59,7532.42 ccw(c2225.62,7546.45) 2225.62,7526.61 2241.87,7526.61 ccw(c2241.87,7602.03) 2295.2,7548.7 ccw(c2231.47,7612.44) 2321.6,7612.44 ccw(c2288.85,7612.44) 2319.23,7624.67 ccw(c2288.85,7612.44) 2312.01,7635.59 2311.8,7635.8 cw(c2324.84,7648.84) 2306.4,7648.84 2306.4,7655.58 cw(c2325.52,7655.58) 2312,7669.1 2313.68,7670.78 ccw(c2294.56,7689.9) 2321.6,7689.9 ccw(c2301.7,7689.9) 2315.77,7703.97 2310.77,7708.97 ; 2310.76,7708.97 2306.33,7713.4 cw(c2321.83,7728.9) 2299.91,7728.9 2299.91,7740.07 cw(c2318.62,7740.07) 2305.39,7753.3 2310.76,7758.67 ; 2310.77,7758.67 2315.81,7763.71 ccw(c2301.78,7777.74) 2321.62,7777.74 R605.1@2321.62,7796.9 ; R605.1@2320.53,7796.9 cw(c2317.95,7794.32) 2321.6,7794.32 ccw(c2317.95,7794.32) R605.1@2320.53,7796.9
F_OUT3N: R608.1 R667.1 R669.2 | length 607.8
  L1_Top Layer w10: R669.2@2016.15,2512.34 ccw(c2016.15,2546.14) 2040.05,2522.24 2062.85,2545.04 cw(c2133.56,2474.33) 2133.56,2574.33 2149.82,2574.33 cw(c2149.82,2554.49) 2163.85,2568.52 2168.89,2563.48 2174.26,2558.1 ccw(c2187.49,2571.33) 2187.49,2552.62 2198.66,2552.62 ccw(c2198.66,2574.54) 2214.16,2559.04 2218.59,2563.47 2223.59,2568.48 cw(c2237.71,2554.36) 2237.71,2574.33 2254.82,2574.33 cw(c2254.82,2516.85) 2295.46,2557.49 2311.08,2541.87 cw(c2278.65,2509.44) 2324.52,2509.44 2324.52,2498.93 cw(c2304.78,2500.92) 2318.81,2486.89 ; 2309.87,2444.19 cw(c2319.44,2453.74) 2305.92,2453.74 2305.92,2468.84 cw(c2318.37,2468.84) 2309.57,2477.65 2318.79,2486.88 ; 2309.88,2444.18 2316.37,2437.69 cw(c2296.45,2417.77) 2324.62,2417.77 2324.62,2412.83 cw(c2304.78,2412.83) 2318.81,2398.8 2313.77,2393.76 2308.39,2388.39 ccw(c2321.62,2375.16) 2302.91,2375.16 2302.91,2363.99 ccw(c2324.83,2363.99) 2309.33,2348.49 2313.76,2344.06 2318.77,2339.06 cw(c2304.65,2324.94) 2324.52,2326.93 ; R608.1@2324.08,2306.94 ccw(c2323.04,2307.98) 2324.52,2307.98 2324.52,2326.93 ; 2324.62,2324.94 ccw(c2304.65,2324.94) 2324.52,2326.93
F_OUT3P: R607.1 R662.1 R665.2 | length 608.6
  L1_Top Layer w10: R665.2@2016.15,2664.32 cw(c2016.15,2630.52) 2040.05,2654.42 2062.85,2631.62 ccw(c2133.56,2702.33) 2133.56,2602.33 2266.41,2602.33 cw(c2266.41,2544.85) 2307.06,2585.49 2330.88,2561.67 cw(c2278.65,2509.44) 2352.52,2509.44 2352.52,2484.64 ; 2352.52,2483.69 2352.52,2307 R607.1@2352.58,2306.93
F_OUT4N: R610.1 R675.1 R677.2 | length 605.4
  L1_Top Layer w10: R677.2@2016.45,1093.92 2017.78,1093.92 ccw(c2017.78,1140.22) 2050.52,1107.48 2066.48,1123.45 cw(c2137.19,1052.74) 2137.19,1152.74 2245.2,1152.74 ccw(c2245.2,1256.16) 2318.33,1183.03 ccw(c2234.8,1266.56) 2352.93,1266.56 2352.93,1447.37 ccw(c2351.15,1447.37) 2352.41,1448.63 R610.1@2352.41,1451.03
F_OUT4P: R609.1 R670.1 R673.2 | length 607.7
  L1_Top Layer w10: R673.2@2016.45,1245.9 cw(c2016.45,1211.72) 2040.62,1235.89 2066.48,1210.02 ccw(c2137.19,1280.74) 2137.19,1180.74 2141.06,1180.74 ccw(c2141.06,1200.71) 2155.18,1186.58 2160.18,1191.59 2164.61,1196.03 cw(c2180.11,1180.53) 2180.11,1202.45 2191.28,1202.45 cw(c2191.28,1183.74) 2204.51,1196.97 2209.88,1191.6 2214.92,1186.55 ccw(c2228.95,1200.58) 2228.95,1180.74 2245.2,1180.74 ccw(c2245.2,1256.16) 2298.53,1202.83 ccw(c2234.8,1266.56) 2324.93,1266.56 ccw(c2292.18,1266.56) 2322.56,1278.8 ccw(c2292.18,1266.56) 2315.34,1289.72 2315.13,1289.93 cw(c2328.17,1302.96) 2309.73,1302.96 2309.73,1309.71 cw(c2328.85,1309.71) 2315.33,1323.23 2317.01,1324.91 ccw(c2297.89,1344.03) 2324.93,1344.03 ccw(c2305.03,1344.03) 2319.1,1358.1 2314.1,1363.1 2309.66,1367.53 cw(c2325.16,1383.03) 2303.24,1383.03 2303.24,1394.2 cw(c2321.95,1394.2) 2308.72,1407.43 2314.09,1412.8 2319.14,1417.84 ccw(c2305.11,1431.87) 2324.95,1431.87 2324.95,1450 R609.1@2324.95,1451.03 ; R609.1@2323.86,1451.03 cw(c2321.28,1448.45) 2324.93,1448.45 ccw(c2321.28,1448.45) R609.1@2323.86,1451.03
F_REFCLK1+: R322.1 R329.2 U24.54 | length 500.2
  L1_Top Layer w6: R329.2@4528,5497.16 4528,5479.35 4504.62,5455.97 4504.62,5441.82 4636.13,5310.31 4636.13,5135.11 4640.47,5130.76 U24.54@4640.47,5112.95
  L1_Top Layer w10: R329.2@4528,5497.16 R322.1@4528,5547.16
F_REFCLK1-: R325.1 R328.2 U24.55 | length 500.2
  L1_Top Layer w6: R328.2@4470.25,5497.16 4470.25,5479.35 4493.62,5455.97 4493.62,5437.27 4625.13,5305.76 4625.13,5135.11 4620.79,5130.76 U24.55@4620.79,5112.95
  L1_Top Layer w10: R328.2@4470.25,5497.16 R325.1@4470.25,5547.16
F_REFCLK1_N: J46.G7 R325.2 | length 4849.6
  L1_Top Layer w6: v1(4421.23,7024.43) 4442.41,7024.43 4493.62,6973.22 4493.62,5639.53 4471.62,5617.53 R325.2@4471.62,5595.78
  L10_Signal Layer 2 w5.5: v1(4421.23,7024.43) 4440.32,7024.43 4479.75,6985 4571.97,6985 4849,7262.03 4849,7585.39 4859.36,7595.75 4953.61,7595.75 4971,7613.14 4971,7645.86 4953.61,7663.25 4859.36,7663.25 4849,7673.61 4849,8022 5430,8603 6279.03,8603 6343.02,8539.01 6394.11,8539.01 v1(6413.11,8520.01)
F_REFCLK1_P: J46.G6 R322.2 | length 4848
  L1_Top Layer w6: v1(4448.81,7052) 4448.81,7033.59 4504.62,6977.77 4504.62,5639.53 4526.62,5617.53 R322.2@4526.62,5595.78
  L10_Signal Layer 2 w5.5: v1(4448.81,7052) 4448.81,7032.91 4484.72,6997 4567,6997 4837,7267 4837,7590.36 4854.39,7607.75 4948.64,7607.75 4959,7618.11 4959,7640.89 4948.64,7651.25 4854.39,7651.25 4837,7668.64 4837,8026.97 5425.03,8615 6284,8615 6347.99,8551.01 6394.11,8551.01 v1(6413.11,8570.01)
F_REFCLK2+: R304.1 R339.2 U24.24 | length 500.6
  L1_Top Layer w6: R339.2@4432.25,4382.29 4432.25,4400.1 4454.94,4422.79 4454.94,4467.61 4585.76,4598.43 4585.76,4744.34 4581.42,4748.69 U24.24@4581.42,4766.5
  L1_Top Layer w10: R304.1@4432.25,4331.29 R339.2@4432.25,4382.29
F_REFCLK2-: R306.1 R338.2 U24.25 | length 502
  L1_Top Layer w6: R338.2@4488.63,4382.29 4488.63,4400.1 4465.94,4422.79 4465.94,4463.05 4596.76,4593.87 4596.76,4744.34 4601.1,4748.69 U24.25@4601.1,4766.5
  L1_Top Layer w10: R306.1@4488.63,4329.91 R338.2@4488.63,4382.29
F_REFCLK2_N: J51.G7 R306.2 | length 4847.8
  L1_Top Layer w6: R306.2@4488.63,4282.67 4488.63,4260.92 4466.63,4238.92 4466.63,2896.37 4686,2677 5769,2677 5780,2688 5780,2708 v1(5764,2724)
  L4_Signal Layer 1 w4.9: v1(5764,2724) 5780,2708 5780,2594.03 5835.48,2538.55 5859.86,2538.55 5920.7,2599.4 5935.14,2599.4 5951.04,2583.5 5951.04,2569.06 5809.94,2427.96 5809.94,2403.58 5832.86,2380.66 5857.24,2380.66 5998.34,2521.76 6012.78,2521.76 6028.68,2505.86 6028.68,2491.42 5887.58,2350.32 5887.58,2325.94 5910.5,2303.02 5934.88,2303.01 6075.98,2444.12 6090.42,2444.12 6106.32,2428.22 6106.32,2413.78 6045.47,2352.94 6045.47,2328.56 6165.53,2208.5 6178.22,2195.81 6271.19,2195.81 6281,2186 6302.19,2186 6312,2195.81 6333.19,2195.81 6342,2187 6366.19,2187 6375,2195.81 6394.64,2195.81 v1(6416.44,2174.01)
F_REFCLK2_P: J51.G6 R304.2 | length 4849.8
  L1_Top Layer w6: R304.2@4433.63,4282.67 4433.63,4260.92 4455.63,4238.92 4455.63,2891.81 4681.44,2666 5773.56,2666 5779.56,2672 5787.78,2680.22 5791,2683.44 5791,2708 5807,2724 v1(5808,2724)
  L4_Signal Layer 1 w4.9: v1(5808,2724) 5792,2708 5792,2599 5840.45,2550.55 5854.89,2550.55 5915.73,2611.4 5940.11,2611.4 5963.04,2588.47 5963.04,2564.09 5821.94,2422.99 5821.94,2408.55 5837.83,2392.66 5852.27,2392.66 5993.37,2533.76 6017.75,2533.76 6040.68,2510.83 6040.68,2486.45 5899.58,2345.35 5899.58,2330.91 5915.47,2315.02 5929.91,2315.01 6071.01,2456.12 6095.39,2456.12 6118.32,2433.19 6118.32,2408.81 6057.47,2347.97 6057.47,2333.53 6170.5,2220.5 6183.19,2207.81 6400.24,2207.81 v1(6416.44,2224.01) ; v1@6415.19,2225.26 v1@6416.75,2226.81
F_SYSREF1+: R318.1 R331.2 U24.49 | length 410.4
  L1_Top Layer w6: U24.49@4738.9,5112.95 4738.9,5130.76 4734.56,5135.11 4734.56,5155 4907.41,5327.86 4907.41,5349.07 4930.79,5372.45 R331.2@4930.79,5390.26
  L1_Top Layer w10: R331.2@4930.79,5390.26 R318.1@4930.79,5440.26
F_SYSREF1-: R320.1 R330.2 U24.50 | length 410.4
  L1_Top Layer w6: U24.50@4719.22,5112.95 4719.22,5130.76 4723.56,5135.11 4723.56,5154.56 4723.56,5159.56 4852,5288 4896.41,5332.41 4896.41,5349.07 4873.03,5372.45 R330.2@4873.03,5390.26
  L1_Top Layer w10: R330.2@4873.03,5390.26 R320.1@4873.03,5440.26
F_SYSREF1_N: J46.G10 R320.2 | length 4939.6
  L1_Top Layer w6: v1(4703.81,7016) 4725,7016 4896.41,6844.59 4896.41,5532.63 4874.41,5510.63 R320.2@4874.41,5488.88
  L10_Signal Layer 2 w5.5: v1(4703.81,7016) 4722.91,7016 4766.91,6972 5001.97,6972 5091,7061.03 5091,7795.86 5073.61,7813.25 5001.36,7813.25 4991,7823.61 4991,7846.39 5001.36,7856.75 5173.61,7856.75 5191,7874.14 5191,7906.86 5173.61,7924.25 5101.36,7924.25 5091,7934.61 5091,8035.03 5392.46,8336.49 5758.49,8336.49 5762,8340 5892,8470 6129.03,8470 6210.02,8389.01 6394.11,8389.01 v1(6413.11,8370.01)
F_SYSREF1_P: J46.G9 R318.2 | length 4938
  L1_Top Layer w6: v1(4731.39,7043.58) 4731.39,7025.16 4907.41,6849.14 4907.41,5532.63 4929.41,5510.63 R318.2@4929.41,5488.88
  L10_Signal Layer 2 w5.5: v1(4731.39,7043.58) 4731.39,7024.49 4771.88,6984 4997,6984 5079,7066 5079,7790.89 5068.64,7801.25 4996.39,7801.25 4979,7818.64 4979,7851.36 4996.39,7868.75 5168.64,7868.75 5179,7879.11 5179,7901.89 5168.64,7912.25 5096.39,7912.25 5079,7929.64 5079,8040 5387.49,8348.49 5753.51,8348.49 5887.03,8482 6134,8482 6214.99,8401.01 6394.11,8401.01 v1(6413.11,8420.01)
F_SYSREF2+: R314.1 R335.2 U24.29 | length 513.2
  L1_Top Layer w6: U24.29@4679.84,4766.5 4679.84,4748.69 4684.19,4744.34 4684.19,4608.29 4842.48,4450 4842.48,4422.38 4819.1,4399 R335.2@4819.1,4381.19
  L1_Top Layer w10: R314.1@4819.1,4330.31 R335.2@4819.1,4381.19
F_SYSREF2-: R315.1 R334.2 U24.30 | length 513.2
  L1_Top Layer w6: U24.30@4699.53,4766.5 4699.53,4748.69 4695.19,4744.34 4695.19,4612.85 4853.48,4454.56 4853.48,4422.38 4876.86,4399 R334.2@4876.86,4381.19
  L1_Top Layer w10: R315.1@4876.86,4330.32 R334.2@4876.86,4381.19
F_SYSREF2_N: J51.G10 R315.2 | length 4835.1
  L1_Top Layer w6: R315.2@4875.47,4281.69 4875.47,4259.95 4853.47,4237.95 4853.47,3054.53 4931,2977 5645,2977 5655,2987 5655,3007 v1(5639,3023)
  L4_Signal Layer 1 w4.9: v1(5639,3023) 5655,3007 5655,2964.97 5561,2870.97 5561,2770.79 5578.24,2753.55 5655.79,2753.55 5666,2743.34 5666,2720.86 5655.79,2710.65 5473.24,2710.65 5456,2693.41 5456,2660.99 5473.24,2643.75 5655.79,2643.75 5666,2633.54 5666,2611.06 5655.79,2600.85 5473.24,2600.85 5456,2583.61 5456,2551.19 5473.24,2533.95 5655.79,2533.95 5666,2523.74 5666,2501.26 5655.79,2491.05 5578.24,2491.05 5561,2473.81 5561,2281.03 5635.03,2207 5936.03,2207 6097.22,2045.81 6271.19,2045.81 6281,2036 6302.19,2036 6312,2045.81 6333.19,2045.81 6342,2037 6366.19,2037 6375,2045.81 6394.64,2045.81 v1(6416.44,2024.01)
F_SYSREF2_P: J51.G9 R314.2 | length 4834.9
  L1_Top Layer w6: R314.2@4820.47,4281.69 4820.47,4259.95 4842.47,4237.95 4842.47,3049.97 4926.44,2966 5649.56,2966 5650.56,2967 5662.78,2979.22 5666,2982.44 5666,3007 5682,3023 v1(5683,3023)
  L4_Signal Layer 1 w4.9: v1(5683,3023) 5667,3007 5667,2960 5573,2866 5573,2775.76 5583.21,2765.55 5660.76,2765.55 5678,2748.31 5678,2715.89 5660.76,2698.65 5478.21,2698.65 5468,2688.44 5468,2665.96 5478.21,2655.75 5660.76,2655.75 5678,2638.51 5678,2606.09 5660.76,2588.85 5478.21,2588.85 5468,2578.64 5468,2556.16 5478.21,2545.95 5660.76,2545.95 5678,2528.71 5678,2496.29 5660.76,2479.05 5583.21,2479.05 5573,2468.84 5573,2286 5640,2219 5941,2219 6102.19,2057.81 6400.24,2057.81 v1(6416.44,2074.01)
FMC_SCL_1: J46.C30 J48.2 U36.6 | length 1594.7
  L1_Top Layer w11: J48.2@5731.21,7194.68 5675.21,7138.68 5675.21,6949.68 5791.21,6833.68 U36.6@5791.21,6776.68
  L12_Bottom Layer w5: 6056.23,7215.03 6089.21,7248.01 6627.11,7248.01 6638.11,7259.01 6638.11,7345.01 J46.C30@6613.11,7370.01
  L12_Bottom Layer w11: J48.2@5731.21,7194.68 5792.21,7133.68 5974.88,7133.68 6056.23,7215.03
FMC_SCL_2: J51.C30 J53.2 U37.6 | length 1600.7
  L1_Top Layer w11: J53.2@5730.4,841.39 5674.4,785.39 5674.4,596.39 5790.4,480.39 U37.6@5790.4,423.39
  L12_Bottom Layer w5: 6076.04,885.52 6090.34,899.81 6628.24,899.81 6641.44,913.01 6641.44,1002.12 J51.C30@6616.75,1026.81
  L12_Bottom Layer w11: J53.2@5730.4,841.39 5784.1,787.69 5978.21,787.69 6076.04,885.52 ; J53.2@5734.54,848.69 J53.2@5736.12,847.11
FMC_SDA_1: J46.C31 J48.1 U36.5 | length 1497.4
  L1_Top Layer w11: J48.1@5631.21,7194.68 5631.21,6940.68 5741.21,6830.68 U36.5@5741.21,6776.68
  L12_Bottom Layer w5: 6076.98,7278.28 6092.71,7294.01 6587.11,7294.01 J46.C31@6613.11,7320.01
  L12_Bottom Layer w11: J48.1@5631.21,7194.68 5681.21,7244.68 6043.38,7244.68 6076.98,7278.28
FMC_SDA_2: J51.C31 J53.1 U37.5 | length 1506
  L1_Top Layer w11: J53.1@5630.4,841.39 5630.4,587.39 5740.4,477.39 U37.5@5740.4,423.39
  L12_Bottom Layer w5: 6084.79,936.77 6097.84,949.81 6589.75,949.81 J51.C31@6616.75,976.81
  L12_Bottom Layer w11: J53.1@5630.4,841.39 5687.69,898.69 6046.71,898.69 6084.79,936.77
FREQ_DIV_RESET: R403.2 U58.9 | length 91.6
  L1_Top Layer w11: R403.2@3342.79,4288.29 3353.36,4277.72 U58.9@3430.04,4277.72
GND: C355.2 C364.2 C371.2 C477.2 C478.2 C480.2 C481.2 C494.2 C495.2 C496.1 C497.1 C498.1 C501.1 C509.2 C510.2 C516.2 C517.2 C518.2 C519.2 C523.2 C524.2 C537.2 C538.2 C539.1 C540.1 C541.1 C544.1 C587.2 C588.2 C589.2 C590.2 C594.2 C595.2 C600.2 C601.2 C602.1 C603.1 C604.1 C608.1 C613.2 C614.2 C615.2 C616.2 C620.2 C621.2 C643.2 C644.1 C645.1 C646.1 C647.2 C654.1 C655.2 C656.2 C657.2 C660.2 C668.2 C669.2 C690.2 C695.1 C696.1 C697.1 C705.1 C706.1 C707.1 C714.2 C715.1 C723.2 D20.2 D21.2 J58.12 J59.7 J59.9 J59.17 J59.19 J59.27 J59.29 J59.31 J60.7 J60.9 J60.11 J60.13 J60.15 J60.23 J60.25 J60.27 J60.29 J60.31 J63.7 J63.8 J63.9 J63.10 J63.11 J63.12 Q3.4 Q3.7 R174.1 R181.1 R186.1 R188.1 R204.1 R207.1 R215.1 R486.1 R488.1 R492.1 R495.1 R496.1 R497.1 R498.1 R499.1 R500.1 R504.1 R507.1 R508.1 R509.1 R510.1 R511.1 R512.1 R516.1 R519.1 R520.1 R521.1 R522.1 R523.1 R524.1 R528.1 R532.1 R533.2 R534.2 R537.1 TP87.1 TP88.1 TP89.1 TP90.1 TP91.1 U38.11@5004.7,11291.8 U39.3 U39.9 U40.2 U41.8 U41.18 U41.21 U42.3 U42.9 U43.2 U44.8 U44.18 U44.21 U45.3 U45.9 U46.2 U47.8 U47.18 U47.21 U48.3 U48.9 U49.2 U50.8 U50.18 U50.21 U51.4 U51.5 U52.2 U53.7 U53.21 | length 3653.4
  L1_Top Layer w8: U53.21@855.91,10901.1 863.41,10893.6 U53.21@881.5,10875.51 ; v3(3254.55,10931.64) v3(3285.06,10931.64) ; v3(4061.01,10927.63) v3(4091.53,10927.63) v3(4122.04,10927.63)
  L1_Top Layer w15: U53.21@881.5,10875.51 U53.7@947.45,10875.51 970.7,10875.51 987.55,10858.67 987.55,10754.6 963.14,10730.19 R537.1@918.5,10730.19 ; C656.2@1490.22,10919.4 1542.82,10919.4 1557.78,10934.36 U50.18@1581.89,10934.36 v3(1616.34,10934.36) v3(1646.85,10934.36) v3(1677.36,10934.36) U50.8@1711.81,10934.36 ; C589.2@2224.09,10917.54 2266.67,10917.54 2281.63,10932.5 U44.18@2315.76,10932.5 v3(2350.21,10932.5) v3(2380.72,10932.5) v3(2411.24,10932.5) U44.8@2445.69,10932.5 ; C516.2@3097.92,10916.68 3140.5,10916.68 3155.46,10931.64 U41.18@3189.59,10931.64 v3(3224.04,10931.64) v3(3254.55,10931.64) ; v3(3285.06,10931.64) U41.8@3319.51,10931.64 ; C614.2@3934.9,10912.67 3977.47,10912.67 3992.43,10927.63 U47.18@4026.56,10927.63 v3(4061.01,10927.63) ; v3(4122.04,10927.63) U47.8@4156.49,10927.63
  L1_Top Layer w20: v2(1641.14,11187.4) 1641.22,11187.32 C669.2@1641.22,11133.9 ; v2(1717.14,11209.91) 1717.22,11209.83 C668.2@1717.22,11156.4 ; v1(2375,11174) 2375,11132.13 C595.2@2375.09,11132.03 ; C594.2@2451.09,11154.54 2513.52,11154.54 v1(2513.59,11154.46) ; R508.1@2572.72,11009.54 R509.1@2572.72,10960.54 v2(2609.67,10960.54) ; R507.1@2572.72,11059.54 2573.64,11060.46 2596.6,11060.46 v2(2616.87,11040.19) ; R512.1@2572.8,10814.61 R512.1@2573.72,10815.54 v2(2610.67,10815.54) ; R511.1@2572.8,10862.61 R511.1@2573.72,10863.54 v2(2610.67,10863.54) ; R510.1@2572.8,10910.61 R510.1@2573.72,10911.54 v2(2610.67,10911.54) ; C524.2@3248.92,11131.17 v2(3248.92,11177.1) ; C523.2@3324.92,11153.68 v2@3387.34,11153.68 ; R497.1@3445.62,10958.76 R497.1@3446.54,10959.68 v2(3483.5,10959.68) ; R496.1@3445.62,11007.76 R496.1@3446.54,11008.68 v2(3483.5,11008.68) ; R495.1@3446.54,11058.68 3447.46,11059.6 v2(3484.42,11059.6) ; R500.1@3446.62,10815.6 R500.1@3447.54,10814.68 v2(3447.54,10777.72) ; R499.1@3446.62,10861.76 R499.1@3447.54,10862.68 v2(3484.5,10862.68) ; R498.1@3446.62,10909.76 R498.1@3447.54,10910.68 v2(3484.5,10910.68) ; C621.2@4085.9,11127.17 v1(4085.9,11173.09) ; C620.2@4161.9,11149.67 v1@4217,11149.67 ; R521.1@4282.6,10954.75 R521.1@4283.52,10955.67 v2(4320.47,10955.67) ; R520.1@4282.6,11003.75 R520.1@4283.52,11004.67 v2(4320.47,11004.67) ; R519.1@4283.52,11054.67 v2(4319.7,11054.67) ; R524.1@4283.6,10809.75 R524.1@4284.52,10810.67 v2(4321.47,10810.67) ; R523.1@4283.6,10857.75 R523.1@4284.52,10858.67 v2(4321.47,10858.67) ; R522.1@4283.6,10905.75 R522.1@4284.52,10906.67 v2(4321.47,10906.67) ; v2(4695.32,11444.73) 4695.82,11444.23 C478.2@4695.82,11392.8 ; v2(4785.32,11444.73) 4785.82,11444.23 C477.2@4785.82,11392.8 ; D20.2@4878.82,11441.27 4930.24,11441.27 v2(4930.74,11441.77) ; D21.2@4938.35,11074.8 4938.35,11023.38 v2(4938.84,11022.88) ; R488.1@4993.32,11167.8 5029.68,11131.44 v2(5030.38,11131.44) ; v2(5099.82,11078.23) C481.2@5099.82,11123.31 ; v2(5162.82,11079.23) R486.1@5162.82,11124.31 ; C480.2@5290.31,11125.8 v2(5335.39,11125.8)
  L12_Bottom Layer w8: U48.9@1380.67,11310.03 U48.3@1409.21,11310.03 1432.56,11310.03 1441.58,11301.01 C509.2@1463.76,11301.01 ; U42.9@2081.49,11309.82 2082.66,11309.82 U42.3@2109,11309.82 2136.73,11309.82 2149.78,11296.76 C364.2@2170.76,11296.76 ; U39.9@2948.49,11309.86 U39.3@2976,11309.86 3013.16,11309.86 C355.2@3031.45,11291.58 ; U45.9@3797.49,11313.99 3798.67,11313.99 U45.3@3825.01,11313.99 3844.4,11313.99 3858.11,11300.28 3883,11300.28 C371.2@3883.49,11300.28
  L12_Bottom Layer w15: R533.2@549.62,11247.92 R534.2@549.62,11296.92 ; v2@588,11247.92 v2(590,11249.92) ; v2(1482.35,10864.71) 1500.35,10864.71 R532.1@1575.66,10789.4
  L12_Bottom Layer w20: R533.2@549.62,11247.92 v2@588,11247.92 ; R534.2@549.62,11296.92 582.76,11296.92 593.42,11286.26 U51.5@623.22,11286.26 ; 705.89,11273.1 U51.4@705.89,11286.26 ; C723.2@910.42,11041.57 v2(910.42,11113.57) ; R504.1@1913.41,11379.93 R504.1@1913.41,11382.04 ; U42.9@2067.66,11322.61 2067.66,11295.99 U42.9@2081.49,11309.82 ; U39.9@2934.66,11322.66 2934.66,11296.04 U39.9@2948.49,11309.86 ; U45.9@3783.67,11326.79 3783.67,11300.17 U45.9@3797.49,11313.99
  other v1: 6401.48,10874.01 6340,10875 6462.97,10875 6278.52,10875.99 6524.45,10875.99 6217.03,10876.98 6585.93,10876.98 6155.55,10877.98 6647.42,10877.98 6094.07,10878.97 6708.9,10878.97 6032.58,10879.96 6770.38,10879.96 5971.1,10880.95 5909.62,10881.95 5848.13,10882.94 5786.65,10883.93 5725.17,10884.92 5663.68,10885.92 5602.2,10886.91 5540.72,10887.9 5432,10890 5233.3,10892.86 5129,10895 5013.85,10895.84 4952.37,10896.83 4890.88,10897.82 4217,11150 5004.7,11254.4 4982.06,11291.8 5027.34,11291.8 5004.7,11329.21
  other v2: 578,10402 617,10402 656,10402 1077,10402 1116,10402 1155,10402 1283,10402 1322,10402 1361,10402 1400,10402 1439,10402 2142,10402 2181,10402 2220,10402 2259,10402 2298,10402 2736,10402 2775,10402 2814,10402 3236,10402 3275,10402 3314,10402 106,10424.84 283,10435 322,10435 361,10435 400,10435 439,10435 1871.77,10515.58 1919.77,10515.58 1175.9,10517.44 382.93,10520 106,10542 1871.77,10563.58 1919.77,10563.58 1175.9,10565.44 382.93,10568 3577.7,10607.73 3625.7,10607.73 2726.74,10610.72 2774.74,10610.72 1871.77,10611.58 1919.77,10611.58 1079.9,10613.44 1127.9,10613.44 1175.9,10613.44 286.93,10616 334.93,10616 382.93,10616 3577.7,10655.73 3625.7,10655.73 2726.74,10658.72 2774.74,10658.72 1871.77,10659.58 1919.77,10659.58 1079.9,10661.44 1127.9,10661.44 1175.9,10661.44 286.93,10664 334.93,10664 382.93,10664 111,10695.61 3577.7,10703.73 3625.7,10703.73 2726.74,10706.72 2774.74,10706.72 1871.77,10707.58 1919.77,10707.58 1079.9,10709.44 1127.9,10709.44 1175.9,10709.44 286.93,10712 334.93,10712 382.93,10712 113,10836 3836,10859 3881,10859 3926,10859 3000.05,10861.99 3045.05,10861.99 3090.05,10861.99 2126.22,10862.85 2171.22,10862.85 2216.22,10862.85 1392.35,10864.71 1437.35,10864.71 552.34,10892 600.34,10892 117,11008 3387.42,11153.6 641,11179.92 690.9,11179.87 3047,11210 2175,11213 1536,11216 1571,11215.9 641,11224.92 690.9,11224.87 3047,11247 2174.91,11251.39 3880.56,11271.08 3920,11271 892,11538
  other v3: 803.25,10855.61 855.41,10855.61 907.58,10855.61 803.41,10885.77 855.58,10885.77 907.75,10885.77 4061.01,10897.12 4091.53,10897.12 4122.04,10897.12 3224.04,10901.13 3254.55,10901.13 3285.06,10901.13 2350.21,10901.98 2380.72,10901.98 2411.24,10901.98 1616.34,10903.85 1646.85,10903.85 1677.36,10903.85 803.58,10915.94 855.75,10915.94 907.91,10915.94 803.75,10946.1 855.91,10946.1 908.08,10946.1 4061.01,10958.14 4091.53,10958.14 4122.04,10958.14 3224.04,10962.15 3254.55,10962.15 3285.06,10962.15 2350.21,10963.01 2380.72,10963.01 2411.24,10963.01 1616.34,10964.87 1646.85,10964.87 1677.36,10964.87 1353.87,11293.3 2053.66,11293.09 2920.66,11293.13 1381.87,11293.77 2081.66,11293.56 2948.66,11293.6 3769.67,11297.26 3797.67,11297.73 1353.87,11322.83 1381.87,11323.3 2053.66,11322.61 2081.66,11323.09 2920.66,11322.66 2948.66,11323.13 3769.67,11326.79 3797.67,11327.26 2053.66,11352.14 2920.66,11352.19 1353.87,11352.36 1381.87,11352.83 2081.66,11352.61 2948.66,11352.66 3769.67,11356.32 3797.67,11356.79
GND1: C479.2 D19.1 J55.2 J55.3 Q3.1 Q3.2 Q3.5 Q3.6 Q3.8 TP20.1 | length 85.8
  L1_Top Layer w11: Q3.5@5038.41,11404.03 5038.41,11387.23 5048.02,11377.62 ; Q3.2@5038.41,11480.8 5038.41,11536.23
HSPC_PRSNT_M2C_L_1: J46.Z1 J49.1 | length 562.6
  L1_Top Layer w11: J49.1@6613.79,9320.76 6613.79,8969.33 v1(6763.11,8820.01)
HSPC_PRSNT_M2C_L_2: J51.Z1 J54.1 | length 562.6
  L1_Top Layer w11: J54.1@6617.12,2974.77 6617.12,2623.33 v1(6766.44,2474.01)
ILIM: R487.2 U38.10 | length 94.9
  L1_Top Layer w10: R487.2@4863.82,11230.3 4897.9,11230.3 4920.03,11252.43 U38.10@4949.58,11252.43
IN1_N: C13.1 C490.2 J13.1 R8.1 | length 392.9
  L1_Top Layer w11: J13.1@101.27,9206.79 J13.1@109,9206.79 260.69,9206.79 R8.1@355.8,9111.67 ; C13.1@320.8,9076.67 R8.1@355.8,9111.67 ; C490.2@390.8,9146.67 R8.1@355.8,9111.67
IN1_P: C14.1 C491.1 C492.1 J14.1 R12.1 | length 446.3
  L1_Top Layer w11: J14.1@100.12,8650.69 J14.1@109,8650.69 256.69,8650.69 R12.1@356.59,8750.59 ; C14.1@321.59,8785.59 R12.1@356.59,8750.59 ; C492.1@426.59,8680.59 C491.1@391.59,8715.59 R12.1@356.59,8750.59
IN2_N: C47.1 C493.2 J30.1 R32.1 | length 390.3
  L1_Top Layer w10: J30.1@103.92,7784.66 J30.1@105.07,7784.66
  L1_Top Layer w11: J30.1@105.07,7784.66 J30.1@109,7784.66 ; J30.1@110.8,7784.66 262.49,7784.66 R32.1@357.6,7689.55 ; C47.1@322.6,7654.55 R32.1@357.6,7689.55 ; C493.2@392.6,7724.55 R32.1@357.6,7689.55
IN2_P: C48.1 C499.1 C500.1 J73.1 R36.1 | length 444.5
  L1_Top Layer w10: J73.1@101.92,7228.57 J73.1@105.07,7228.57
  L1_Top Layer w11: J73.1@105.07,7228.57 J73.1@109,7228.57 ; J73.1@110.8,7228.57 258.49,7228.57 R36.1@358.39,7328.47 ; C48.1@323.39,7363.47 R36.1@358.39,7328.47 ; C500.1@428.39,7258.47 C499.1@393.39,7293.47 R36.1@358.39,7328.47
IN3_N: C173.1 C502.2 J76.1 R89.1 | length 388.8
  L1_Top Layer w11: J76.1@105.36,2860.42 J76.1@109,2860.42 ; J76.1@112.32,2860.42 264.01,2860.42 R89.1@359.12,2765.31 ; C173.1@324.12,2730.31 R89.1@359.12,2765.31 ; C502.2@394.12,2800.31 R89.1@359.12,2765.31
IN3_P: C174.1 C503.1 C504.1 J77.1 R93.1 | length 441.1
  L1_Top Layer w11: J77.1@105.36,2304.33 J77.1@109,2304.33 ; J77.1@112.32,2304.33 260.01,2304.33 R93.1@359.91,2404.23 ; C174.1@324.91,2439.23 R93.1@359.91,2404.23 ; C504.1@429.91,2334.23 C503.1@394.91,2369.23 R93.1@359.91,2404.23
IN4_N: C207.1 C505.2 J80.1 R113.1 | length 385.2
  L1_Top Layer w11: J80.1@112.39,1441.09 264.08,1441.09 R113.1@359.19,1345.98 ; C207.1@324.19,1310.98 R113.1@359.19,1345.98 ; C505.2@394.19,1380.98 R113.1@359.19,1345.98
IN4_P: C208.1 C506.1 C507.1 J81.1 R117.1 | length 437.5
  L1_Top Layer w11: J81.1@112.39,885 260.09,885 R117.1@359.98,984.9 ; C208.1@324.98,1019.9 R117.1@359.98,984.9 ; C507.1@429.98,914.9 C506.1@394.98,949.9 R117.1@359.98,984.9
IOVLVL: R597.2 U24.7 | length 5528.1
  L1_Top Layer w10: v1(4352,4929) 4363,4929 4403.25,4969.25 U24.7@4418.03,4969.25
  L1_Top Layer w11: v2(4088,9891) 4090,9889 R597.2@4200.5,9889
  L10_Signal Layer 2 w6.5: v2(4088,9891) 4105,9874 4105,9583 4076,9554 4076,7424 4001,7349 4001,6856 4546,6311 4546,5788 4480,5722 4480,5198.12 4341,5059.12 4341,4939.89 4351.89,4929 v1(4352,4929) 4355.28,4929 v1@4356.28,4928
LDO_PG_1P9V: R389.1 R493.2 TP81.1 U41.4 | length 1809
  L1_Top Layer w10: R389.1@2296,11282.49 2428.51,11282.49 2470,11241 v1(2603,11241) ; R493.2@3246.95,10640.06 3249.08,10640.06 v2(3327.03,10718.01) 3327.03,10798.69 3274.24,10851.48 U41.4@3274.24,10866.68
  L12_Bottom Layer w10: v1(2603,11241) 2602.15,11240.15 2602.15,11093.85 2626,11070 3271.86,11070 3327.03,11014.84 v2(3327.03,10718.01)
LMH_CLK: U27.6 U34.48 | length 528.3
  L1_Top Layer w11: U34.48@5083.38,9736.33 5083.38,9272.62 5100.41,9255.59 U27.6@5140.96,9255.59
LMH_CS1: U27.3 U34.54 | length 561.5
  L1_Top Layer w11: U27.3@5140.96,9178.81 5189.81,9178.81 5225,9214 5225,9583.12 5252.67,9610.8 U34.54@5252.67,9665.47
LMH_CS2: U29.5 U34.55 | length 492.1
  L1_Top Layer w11: U34.55@5272.36,9665.47 5272.36,9602.36 5242,9572 5242,9303 v2(5279,9266)
  L12_Bottom Layer w11: v2(5279,9266) 5279.2,9265.8 U29.5@5343.68,9265.8
LMH_CS3: U29.4 U34.57 | length 617.3
  L1_Top Layer w11: v2(5266,9454) 5266,9568 5311.73,9613.73 U34.57@5311.73,9665.47
  L12_Bottom Layer w11: v2(5266,9454) 5357,9454 5413,9398 5413,9258 5395.2,9240.2 U29.4@5343.68,9240.2
LMH_CS4: U29.3 U34.58 | length 628.3
  L1_Top Layer w11: v2(5292,9489) 5292,9564 5331.41,9603.41 U34.58@5331.41,9665.47
  L4_Signal Layer 1 w5.5: v2(5292,9489) v2@5292,9490
  L12_Bottom Layer w11: v2(5292,9489) 5349,9489 5432,9406 5432,9248 5398.61,9214.61 U29.3@5343.68,9214.61
LMH_CSX1: J85.4 U34.59 | length 1077.8
  L1_Top Layer w11: v2(5340.19,9726.93) 5351.1,9716.03 U34.59@5351.1,9665.47
  L10_Signal Layer 2 w6.5: J85.4@5185,10663 5354,10494 5354,9740.74 v2(5340.19,9726.93)
LMH_SDI: U27.5 U34.52 | length 484.2
  L1_Top Layer w11: U27.5@5140.96,9230 5173,9230 5188,9245 5188,9594.21 5213.3,9619.51 U34.52@5213.3,9665.47
LMH_SDO: U27.4 U34.53 | length 519.9
  L1_Top Layer w11: U27.4@5140.96,9204.4 5176.4,9204.4 5205,9233 5205,9587.17 5232.99,9615.15 U34.53@5232.99,9665.47
LMK00304_STS: R550.1 U34.33 U58.13 | length 7748.9
  L1_Top Layer w11: v2(3323,4242) 3323.18,4241.82 R550.1@3323.18,4183.24 3331.06,4175.36 U58.13@3430.04,4175.36 ; v2(4410,10014) 4411,10014 4562,10165 5004,10165 5083.38,10085.62 U34.33@5083.38,10031.61
  L10_Signal Layer 2 w6.5: v2(3323,4242) 3128.5,4436.5 3128.5,5172.5 2874.68,5426.32 2874.68,6515.68 3296,6937 3296,7692 4036,8432 4036,9919 4131,10014 v2(4410,10014)
LMK04828_SYNC1: J46.J15 R586.2 | length 221.1
  L1_Top Layer w11: R586.2@6102.73,8146.01 6287.11,8146.01 v1(6313.11,8120.01)
LMK04828_SYNC2: J51.J15 R590.1 | length 221.1
  L1_Top Layer w11: R590.1@6106.37,1802.81 6290.75,1802.81 v1@6316.75,1776.81
  other v1: 6316.44,1774.01
LMK_ADC1_DCLKM: C99.2 C396.2 R197.1 | length 4856.9
  L4_Signal Layer 1 w4.9: v1(2008.17,8157.76) 1946.92,8219 1910.97,8219 1882,8190.03 1882,8173 1896,8159 1896,8145 1882,8131 1882,8116 1896,8102 1896,8088 1882,8074 1882,8058 1895,8045 1895,8029 1882,8016 1882,8001 1895,7988 1895,7972 1882,7959 1882,7944 1896,7930 1896,7916 1882,7902 1882,7885 1896,7871 1896,7857 1882,7843 1882,7823 1896,7809 1896,7791 1882,7777 1882,7065.97 2291.97,6656 2954.97,6656 2957.97,6653 3704,5906.97 3704,5144 3812,5036 3923,5036 3943,5056 3943,5127 3934.06,5135.94 3915.35,5135.94 v1(3893.85,5114.44)
LMK_ADC1_DCLKP: C90.2 C394.2 R195.1 | length 4856.9
  L4_Signal Layer 1 w4.9: v1(2008.17,8292.24) 1946.92,8231 1906,8231 1870,8195 1870,7061 2287,6644 2950,6644 3692,5902 3692,5139.03 3807.03,5024 3927.97,5024 3955,5051.03 3955,5131.97 3939.03,5147.94 3915.35,5147.94 v1(3893.85,5169.44)
LMK_ADC1_SYSREF_M: C95.1 R200.1 R201.1 R280.2 U20.3 | length 8900.1
  L4_Signal Layer 1 w4.9: v1(2103.89,8024.57) 2103.89,8084.77 2092.97,8095.69 2018.66,8095.69 1979.97,8057 1979.97,7129 2296.97,6812 2387.74,6812 2395.45,6819.71 2395.45,6879.76 2410.19,6894.5 2437.61,6894.5 2452.35,6879.76 2452.35,6737.21 2460.06,6729.5 2477.54,6729.5 2485.25,6737.21 2485.25,6879.76 2499.99,6894.5 2527.41,6894.5 2542.15,6879.76 2542.15,6737.21 2549.86,6729.5 2567.34,6729.5 2575.05,6737.21 2575.05,6797.26 2589.79,6812 2879,6812 3799,5892 3799,5350 3893,5256 4038.97,5256 4042.49,5252.49 4111,5183.97 4111,4990.3 4091.97,4971.27 4071.29,4971.27 v1(4054.79,4954.77)
  L12_Bottom Layer w6: U20.3@1482.81,5636.03 1483.28,5635.57 R201.1@1483.28,5559.32 1483.28,5541.51 1465.16,5523.38 1465.16,5384.84 1514,5336 2953,5336 3048,5241 3433,5241 3497.02,5176.98 3508.73,5176.98 3549.03,5217.28 3569.85,5217.28 3589.34,5197.8 3589.34,5176.98 3549.03,5136.67 3549.03,5124.97 3634,5040 3696.22,5040 3704.5,5048.28 3704.5,5109.28 3719.22,5124 3746.78,5124 3761.5,5109.28 3761.5,4964.28 3769.78,4956 3788.22,4956 3796.5,4964.28 3796.5,5025.28 3811.22,5040 4089.56,5040 4106.51,5023.05 4109.73,5019.82 4109.73,4988.44 4106.51,4985.22 4093.06,4971.77 4071.79,4971.77 v1(4054.79,4954.77)
  L12_Bottom Layer w11: U20.3@1482.81,5636.03 R200.1@1482.81,5706.9
LMK_ADC1_SYSREF_P: C94.1 R201.2 R277.2 U20.4 | length 8834
  L4_Signal Layer 1 w4.9: v1(2103.89,8178.81) 2103.89,8118.61 2092.97,8107.69 2013.69,8107.69 1967.97,8061.97 1967.97,7124.03 2292,6800 2392.71,6800 2407.45,6814.74 2407.45,6874.79 2415.16,6882.5 2432.64,6882.5 2440.35,6874.79 2440.35,6732.24 2455.09,6717.5 2482.51,6717.5 2497.25,6732.24 2497.25,6874.79 2504.96,6882.5 2522.44,6882.5 2530.15,6874.79 2530.15,6732.24 2544.89,6717.5 2572.31,6717.5 2587.05,6732.24 2587.05,6792.29 2594.76,6800 2874.03,6800 3787,5887.03 3787,5345.03 3790.51,5341.51 3888.03,5244 4034,5244 4099,5179 4099,4995.27 4087,4983.27 4071.29,4983.27 v1(4054.79,4999.77)
  L12_Bottom Layer w6: U20.4@1432.81,5636.03 1436.04,5632.81 R201.2@1436.04,5559.32 1436.04,5541.51 1454.16,5523.38 1454.16,5509 1442,5496.84 1442,5475.16 1454.16,5463 1454.16,5447 1440,5432.84 1440,5414.16 1454.16,5400 1454.16,5380.29 1509.44,5325 2948.44,5325 3043.44,5230 3428.44,5230 3492.46,5165.98 3513.28,5165.98 3553.59,5206.28 3565.3,5206.28 3578.34,5193.24 3578.34,5181.54 3538.03,5141.23 3538.03,5120.41 3629.44,5029 3700.78,5029 3715.5,5043.72 3715.5,5104.72 3723.78,5113 3742.22,5113 3750.5,5104.72 3750.5,4959.72 3765.22,4945 3792.78,4945 3807.5,4959.72 3807.5,5020.72 3815.78,5029 4085,5029 4098.73,5015.27 4098.73,4993 4088.5,4982.77 4071.79,4982.77 v1(4054.79,4999.77)
LMK_ADC2_DCLKM: C259.2 C402.2 R238.1 | length 5018.4
  L4_Signal Layer 1 w4.9: v1(2011.5,1810.35) 1950.25,1871.6 1907.29,1871.6 1883.77,1895.11 1880.26,1898.63 1880.26,2336.26 2065,2521 2386,2521 2849,2984 2849,3311.97 3128.51,3591.49 3132.03,3595 3867.03,3595 4123,3850.97 4123,4087.11 4137.74,4101.85 4205.79,4101.85 4213.5,4109.56 4213.5,4127.04 4205.79,4134.75 4047.24,4134.75 4032.5,4149.49 4032.5,4176.91 4047.24,4191.65 4205.79,4191.65 4213.5,4199.36 4213.5,4216.84 4205.79,4224.55 4137.74,4224.55 4123,4239.29 4123,4660 4116.48,4666.52 4101.35,4666.52 v1(4082.35,4647.52)
LMK_ADC2_DCLKP: C250.2 C401.2 R236.1 | length 5018.4
  L4_Signal Layer 1 w4.9: v1(2011.5,1944.84) 1950.25,1883.6 1912.26,1883.6 1892.26,1903.6 1892.26,2331.29 2069.97,2509 2390.97,2509 2861,2979.03 2861,3307 3137,3583 3872,3583 4135,3846 4135,4082.14 4142.71,4089.85 4210.76,4089.85 4225.5,4104.59 4225.5,4132.01 4210.76,4146.75 4052.21,4146.75 4044.5,4154.46 4044.5,4171.94 4052.21,4179.65 4210.76,4179.65 4225.5,4194.39 4225.5,4221.81 4210.76,4236.55 4142.71,4236.55 4135,4244.26 4135,4664.97 4121.45,4678.52 4101.35,4678.52 v1(4082.35,4697.52)
LMK_ADC2_SYSREF_M: C255.1 R239.1 R240.1 R295.2 U22.3 | length 8615.4
  L4_Signal Layer 1 w4.9: v1(2108.76,1677.75) 2108.76,1737.5 2096.89,1749.37 2047,1749.37 1880.72,1749.37 1818.26,1811.83 1818.26,2383.23 2040.03,2605 2365,2605 2786,3026 2786,3362.97 3085.03,3662 3151.03,3728 3778.03,3728 3939.5,3889.47 3939.5,4433.91 3954.24,4448.65 4049.29,4448.65 4057,4456.36 4057,4473.84 4049.29,4481.55 3954.24,4481.55 3939.5,4496.29 3939.5,4822.92 3927.99,4834.44 3904.85,4834.44 v1(3885.85,4815.44)
  L12_Bottom Layer w6: R240.1@3067.84,4261.16 3067.84,4278.97 3085.96,4297.09 3085.96,4317.51 3073,4330.47 3073,4351.56 3085.96,4364.51 3085.96,4380.51 3075,4391.47 3075,4415.56 3104.22,4444.78 3107.44,4448 3178.56,4448 3181.78,4444.78 3196.78,4429.78 3200,4426.56 3200,3970.56 3230.78,3939.78 3847.78,3939.78 3934.14,4026.14 3934.14,4248.78 3948.86,4263.5 4028.36,4263.5 4036.64,4271.78 4036.64,4290.22 4028.36,4298.5 3846.36,4298.5 3831.64,4313.22 3831.64,4340.78 3846.36,4355.5 4028.36,4355.5 4036.64,4363.78 4036.64,4382.22 4028.36,4390.5 3846.36,4390.5 3831.64,4405.22 3831.64,4432.78 3846.36,4447.5 4028.36,4447.5 4036.64,4455.78 4036.64,4474.22 4028.36,4482.5 3948.86,4482.5 3934.14,4497.22 3934.14,4820.94 3920.14,4834.94 3905.35,4834.94 v1(3885.85,4815.44) ; U22.3@3068.8,4181.94 R240.1@3068.8,4260.19
  L12_Bottom Layer w11: R239.1@3067.83,4111.57 U22.3@3067.83,4180.97
LMK_ADC2_SYSREF_P: C254.1 R240.2 R293.2 U22.4 | length 8541.6
  L4_Signal Layer 1 w4.9: v1(2108.76,1833) 2108.76,1773.25 2096.89,1761.37 1996,1761.37 1885.69,1761.37 1830.26,1816.8 1830.26,2378.26 2045,2593 2369.97,2593 2798,3021.03 2798,3358 3156,3716 3783,3716 3951.5,3884.5 3951.5,4428.94 3959.21,4436.65 4054.26,4436.65 4069,4451.39 4069,4478.81 4054.26,4493.55 3959.21,4493.55 3951.5,4501.26 3951.5,4827.89 3932.96,4846.44 3904.85,4846.44 v1(3885.85,4865.44)
  L12_Bottom Layer w6: R240.2@3115.08,4261.16 3115.08,4278.97 3096.96,4297.09 3096.96,4421.96 3112,4437 3174,4437 3189,4422 3189,3966 3223,3932 3226.22,3928.78 3852.33,3928.78 3855.56,3932 3945.14,4021.58 3945.14,4244.22 3953.42,4252.5 4032.92,4252.5 4047.64,4267.22 4047.64,4294.78 4032.92,4309.5 3850.92,4309.5 3842.64,4317.78 3842.64,4336.22 3850.92,4344.5 4032.92,4344.5 4047.64,4359.22 4047.64,4386.78 4032.92,4401.5 3850.92,4401.5 3842.64,4409.78 3842.64,4428.22 3850.92,4436.5 4032.92,4436.5 4047.64,4451.22 4047.64,4478.78 4032.92,4493.5 3953.42,4493.5 3945.14,4501.78 3945.14,4825.5 3924.7,4845.94 3905.35,4845.94 v1(3885.85,4865.44) ; U22.4@3118.8,4181.94 R240.2@3118.8,4257.43
LMK_CLKIN: J28.1 R301.1 R307.2 | length 250
  L1_Top Layer w11: R301.1@5430.87,4433.5 5460.37,4404 R307.2@5461,4404 J28.1@5607.84,4257.16
LMK_CS: R451.1 U34.40 | length 152.6
  L1_Top Layer w11: R451.1@4935.38,9910.97 R451.1@4937.81,9910.97 ; R451.1@4937.81,9905 4949,9893.81 U34.40@5083.38,9893.81
LMK_EXT_SYNC: R229.1 R601.1 | length 8277.2
  L1_Top Layer w11: v2(4062,9588) R601.1@4199.01,9588
  L10_Signal Layer 2 w6.5: v2(4062,9588) 4063.5,9586.5 4063.5,7437.5 3984,7358 3984,6849 4530,6303 4530,5797 4116,5383 4116,4542 v1(4189,4469)
  L12_Bottom Layer w11: v1(4189,4469) 4189,4303 4142,4256 4142,3564 4305.34,3400.66 5497.75,3400.66 5571.71,3474.62 R229.1@5679,3474.62
LMK_LMX_SCK: R445.1 U34.38 | length 186.9
  L1_Top Layer w11: R445.1@4937.81,10033 5037.63,9933.18 U34.38@5083.38,9933.18
LMK_SDIO_LMX_SDI: R447.1 U34.39 | length 171
  L1_Top Layer w11: R447.1@4935.38,9974.97 R447.1@4937.81,9974.97 ; R447.1@4937.81,9969 4977,9969 5032.5,9913.5 U34.39@5083.38,9913.5
LMX1_CLKM: C93.2 R168.1 U19.22 | length 2878.9
  L1_Top Layer w6: U19.22@2283.76,6253.99 2283.76,6271.8 2279.41,6276.14 2279.41,6315.31 2291.82,6327.71 R168.1@2291.82,6343.55 2291.82,6359.39 2279.27,6371.94 2279.27,6492.09 v1(2294.77,6507.59)
  L12_Bottom Layer w6: C93.2@2055.41,8205 2077.16,8205 2091.66,8219.5 2109.56,8219.5 2125,8234.94 2125,8258.56 2053.56,8330 1855.44,8330 1788,8262.56 1788,6869 2203,6454 2262,6454 2279.27,6471.27 2279.27,6492.09 v1(2294.77,6507.59)
LMX1_CLKP: C92.2 R164.1 U19.23 | length 2878.7
  L1_Top Layer w6: v1(2252.77,6507.59) 2268.27,6492.09 2268.27,6372.26 2255.73,6359.71 R164.1@2255.73,6343.87 2255.73,6328.03 2268.41,6315.34 2268.41,6276.14 2264.07,6271.8 U19.23@2264.07,6253.99
  L12_Bottom Layer w6: C92.2@2055.41,8245 2077.16,8245 2091.66,8230.5 2105,8230.5 2114,8239.5 2114,8254 2049,8319 1860,8319 1799,8258 1799,6873.56 1862.56,6810 1887,6810 1897,6800 1897,6775.56 1907.56,6765 1932,6765 1943.16,6753.84 1943.16,6729.4 1954.47,6718.08 1975.69,6718.08 1987,6706.77 1987,6685.56 2008.93,6663.63 2030.14,6663.63 2042.16,6651.61 2042.16,6630.4 2053.47,6619.08 2074.69,6619.08 2086,6607.77 2086,6586.56 2101.48,6571.07 2122.69,6571.07 2134.72,6559.05 2134.72,6537.84 2146.03,6526.53 2167.24,6526.53 2178.56,6515.21 2178.56,6494 2207.56,6465 2257.44,6465 2268.27,6475.83 2268.27,6492.09 v1(2252.77,6507.59)
LMX1_CS: R452.1 U34.41 | length 158.9
  L1_Top Layer w11: R452.1@4937.81,9842 4969,9842 5001.13,9874.13 U34.41@5083.38,9874.13
LMX1_REFN: R203.1 R255.2 R256.1 R258.2 | length 1443.1
  L1_Top Layer w6: v2(2789.09,5047.33) 2804.04,5062.29 2888.81,5062.29 2911.69,5039.41 2920.59,5039.41 2923.76,5042.58 2929.5,5042.58 2981,5042.58 R255.2@2983.38,5042.58
  L4_Signal Layer 1 w4.9: v1(2301.31,5429.94) 2282.71,5411.34 2282.71,5377.29 2300.5,5359.5 2526.74,5359.5 2534.45,5367.21 2534.45,5496.76 2549.19,5511.5 2576.61,5511.5 2591.35,5496.76 2591.35,5367.21 2599.06,5359.5 2798.47,5359.5 2848,5309.97 2848,5083.11 2825.72,5060.83 2802.59,5060.83 v2(2789.09,5047.33)
LMX1_REFP: R185.2 R252.1 R254.2 R259.2 | length 1443.4
  L1_Top Layer w6: v2(2789.09,5086.33) 2802.13,5073.29 2888.81,5073.29 2911.69,5096.17 R259.2@2929.5,5096.17 2930,5096.67 R252.1@2982,5096.67
  L4_Signal Layer 1 w4.9: v1(2252.11,5430.25) 2270.71,5411.65 2270.71,5372.32 2292.01,5351.01 2295.53,5347.5 2339,5347.5 2352.5,5334 2372.5,5334 2386,5347.5 2402,5347.5 2416.5,5333 2433.5,5333 2448,5347.5 2531.71,5347.5 2546.45,5362.24 2546.45,5491.79 2554.16,5499.5 2571.64,5499.5 2579.35,5491.79 2579.35,5362.24 2594.09,5347.5 2793.5,5347.5 2836,5305 2836,5088.08 2820.75,5072.83 2802.59,5072.83 v2(2789.09,5086.33)
LMX1_SYNC: R178.2 R193.1 U20.7 | length 800.8
  L12_Bottom Layer w11: R193.1@1532.81,5753.77 U20.7@1532.81,5825.01 1532.81,5983.47 1570.16,6020.82 2065.39,6020.82 R178.2@2081.69,6004.52
LMX1_SYSREFREQ: R184.2 R200.2 U20.6 | length 933.2
  L12_Bottom Layer w11: R200.2@1482.81,5754.14 U20.6@1482.81,5825.01 1482.81,5986.87 1680.66,6184.72 2084.13,6184.72 R184.2@2096.31,6196.9
LMX2_CLKM: C253.2 R209.1 U21.22 | length 2893.9
  L1_Top Layer w6: v1(2256.84,3310.39) 2272.34,3325.89 2272.34,3446.04 2259.8,3458.58 R209.1@2259.8,3474.42 2259.8,3490.27 2272.2,3502.67 2272.2,3541.83 2267.86,3546.17 U21.22@2267.86,3563.98
  L12_Bottom Layer w6: C253.2@2058.74,1857.6 2080.49,1857.6 2094.99,1872.1 2112.65,1872.1 2125.78,1885.22 2129,1888.44 2129,1911.56 2125.78,1914.78 2069,1971.56 2069,2123.56 1969,2223.56 1969,2778 1930,2817 1930,2900.22 1938.28,2908.5 2088.28,2908.5 2103,2923.22 2103,2950.78 2088.28,2965.5 1938.28,2965.5 1930,2973.78 1930,3050.22 1938.28,3058.5 2088.28,3058.5 2103,3073.22 2103,3100.78 2088.28,3115.5 1938.28,3115.5 1930,3123.78 1930,3194 2019.93,3283.93 2053.16,3317.16 ; v1(2256.84,3310.39) 2272.34,3325.89 2272.34,3354.66 2250,3377 2184,3377 2175,3368 2154,3368 2145,3377 2113,3377 2097,3361 2097,3342 2083.47,3328.47 2064.47,3328.47 ; 2053.16,3317.16 2064.47,3328.47 ; 2053.16,3317.16 2064.47,3328.47
LMX2_CLKP: C252.2 R205.1 U21.23 | length 2877.7
  L1_Top Layer w6: U21.23@2287.55,3563.98 2287.55,3546.17 2283.2,3541.83 2283.2,3502.63 2295.89,3489.95 R205.1@2295.89,3474.1 2295.89,3458.26 2283.34,3445.72 2283.34,3325.89 v1(2298.84,3310.39)
  L12_Bottom Layer w6: C252.2@2058.74,1897.6 2080.49,1897.6 2094.99,1883.1 2108.1,1883.1 2118,1893 2118,1907 2058,1967 2058,2119 1958,2219 1958,2773.44 1919,2812.44 1919,2904.78 1933.72,2919.5 2083.72,2919.5 2092,2927.78 2092,2946.22 2083.72,2954.5 1933.72,2954.5 1919,2969.22 1919,3054.78 1933.72,3069.5 2083.72,3069.5 2092,3077.78 2092,3096.22 2083.72,3104.5 1933.72,3104.5 1919,3119.22 1919,3198.56 2108.44,3388 2254.56,3388 2283.34,3359.21 2283.34,3325.89 v1(2298.84,3310.39)
LMX2_CS: R454.1 U34.45 | length 180.5
  L1_Top Layer w11: R454.1@4935.38,9722.97 R454.1@4937.81,9722.97 ; R454.1@4937.81,9717 4951.96,9717 5030.35,9795.39 U34.45@5083.38,9795.39
LMX2_REFN: R244.1 R264.2 R265.1 R268.2 | length 1443.8
  L1_Top Layer w6: v2(2788.59,4845.83) 2803.54,4860.79 2888.31,4860.79 2911.19,4837.91 2929,4837.91 2929.5,4837.41 2930,4836.91 R265.1@2980,4836.91
  L4_Signal Layer 1 w4.9: v1(2248.66,4387.84) 2268.16,4407.34 2268.16,4848.13 2322.03,4902 2672.03,4902 2728.03,4958 2827,4958 2851,4934 2851,4881.61 2828.72,4859.33 2802.09,4859.33 v2(2788.59,4845.83)
LMX2_REFP: R226.2 R260.1 R262.2 R269.2 | length 1443.9
  L1_Top Layer w6: v2(2788.59,4884.83) 2801.63,4871.79 2888.31,4871.79 2911.19,4894.67 R269.2@2929,4894.67 2933,4890.67 R260.1@2981,4890.67
  L4_Signal Layer 1 w4.9: v1(2299.16,4387.35) 2280.16,4406.34 2280.16,4436 2291.16,4447 2291.16,4471 2280.16,4482 2280.16,4498 2292.16,4510 2292.16,4533 2280.16,4545 2280.16,4568 2292.16,4580 2292.16,4603 2280.16,4615 2280.16,4631 2291.16,4642 2291.16,4666 2280.16,4677 2280.16,4697 2292.16,4709 2292.16,4732 2280.16,4744 2280.16,4761 2292.16,4773 2292.16,4796 2280.16,4808 2280.16,4843.16 2327,4890 2677,4890 2733,4946 2822.03,4946 2839,4929.03 2839,4886.58 2823.75,4871.33 2802.09,4871.33 v2(2788.59,4884.83)
LMX2_SYNC: R219.2 R234.1 U22.7 | length 800.8
  L12_Bottom Layer w11: R219.2@2469.93,3813.45 2486.22,3797.16 2981.46,3797.16 3018.8,3834.5 U22.7@3018.8,3992.97 R234.1@3018.8,4064.21
LMX2_SYSREFREQ: R225.2 R239.2 U22.6 | length 934.1
  L12_Bottom Layer w11: R225.2@2455.3,3621.08 2467.49,3633.26 2870.96,3633.26 3068.8,3831.1 U22.6@3068.8,3992.97 3067.83,3993.94 R239.2@3067.83,4064.32
LMX_ADC1_SYSREF_M: C325.1 R180.1 U19.19 | length 2672
  L1_Top Layer w6: U19.19@2329.03,6208.71 2346.84,6208.71 2351.18,6204.37 2390.38,6204.37 2403.07,6217.06 R180.1@2418.91,6217.06 2434.75,6217.06 2447.3,6204.51 2545.3,6204.51 2650.1,6309.32 2701.66,6309.32 v1(2717.16,6324.82)
  L12_Bottom Layer w6: v1(2056.89,8077.19) 2037.89,8096.19 2017,8096.19 1979.97,8059.16 1979.97,7136.03 2545.93,6570.07 2567.14,6570.07 2579.16,6558.05 2579.16,6536.84 2590.47,6525.53 2611.69,6525.53 2623,6514.21 2623,6493 2641,6475 2641,6413 2656,6398 2656,6381 2641,6366 2641,6346.56 2678.24,6309.32 2701.66,6309.32 v1(2717.16,6324.82)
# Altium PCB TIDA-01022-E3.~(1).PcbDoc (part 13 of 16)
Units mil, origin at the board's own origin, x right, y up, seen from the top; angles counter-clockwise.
Board outline 6929.13 x 11614.17 mil, 12 copper layers (L1_Top Layer, L2_GND, L3_GND, L4_Signal Layer 1, L5_GND, L6_PWR, L7_GND/PWR, L8_PWR, L9_GND/PWR, L10_Signal Layer 2, L11_GND, L12_Bottom Layer), stack 64.6 mil thick; 1733 components, 993 nets, 5987 pads, 3555 vias.

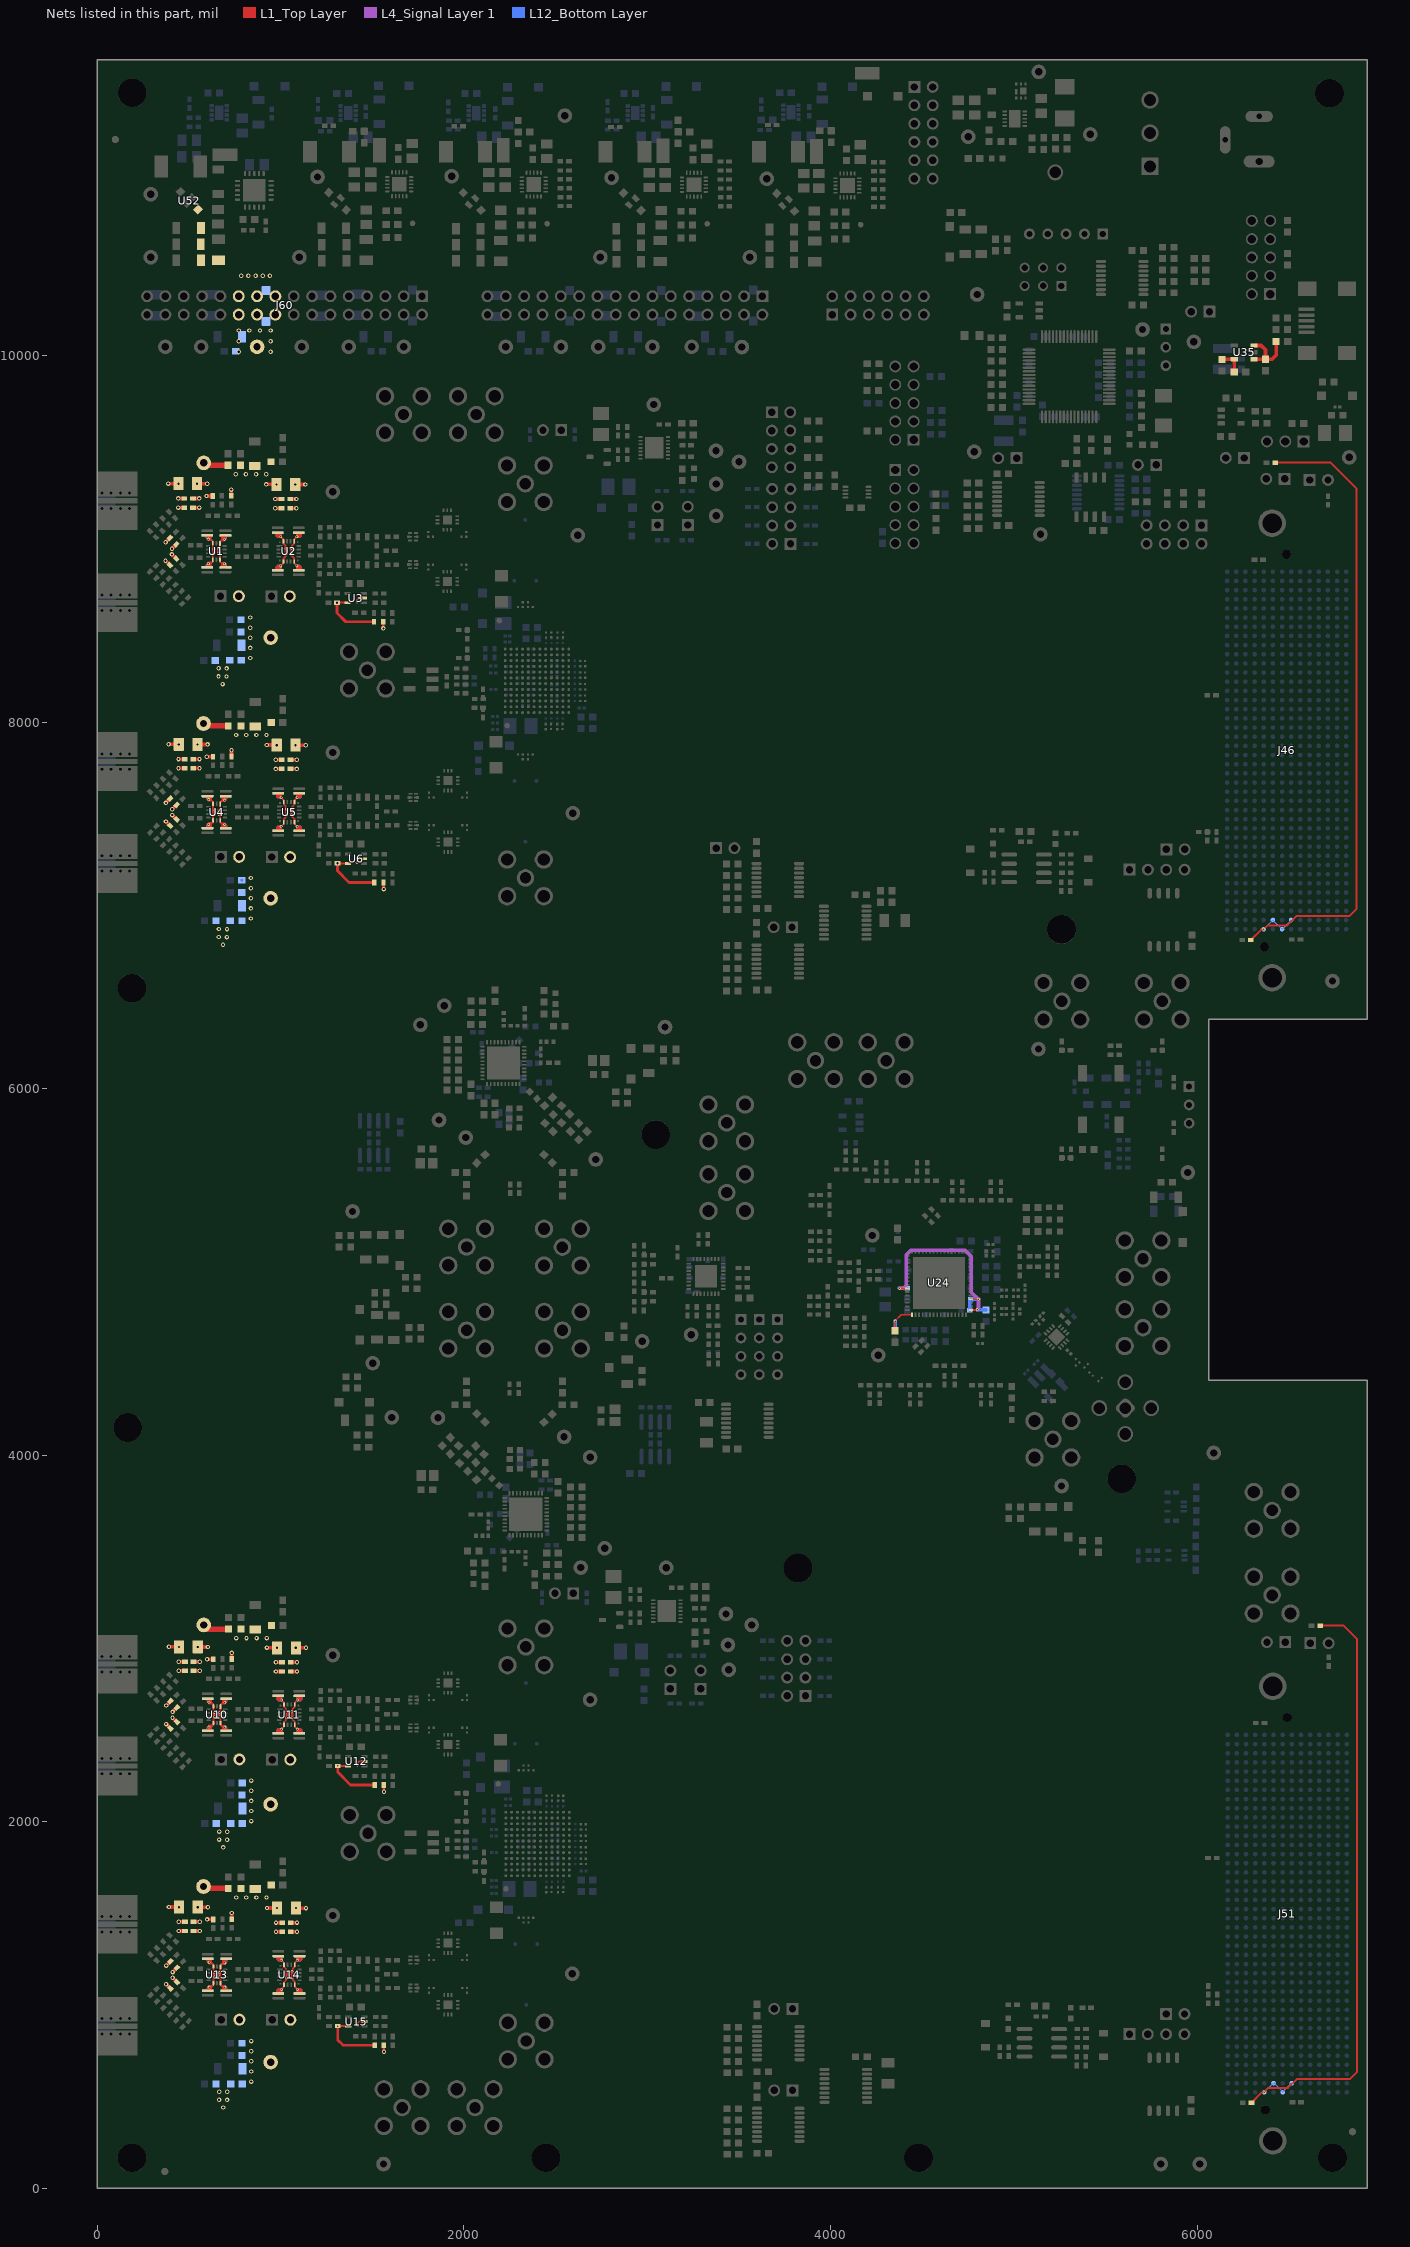
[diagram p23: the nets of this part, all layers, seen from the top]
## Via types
v1: diameter 16, hole 8, L1_Top Layer to L12_Bottom Layer, tented both sides, 1686 vias
v2: diameter 24, hole 12, L1_Top Layer to L12_Bottom Layer, tented both sides, 1590 vias
v3: diameter 20, hole 10, L1_Top Layer to L12_Bottom Layer, 279 vias

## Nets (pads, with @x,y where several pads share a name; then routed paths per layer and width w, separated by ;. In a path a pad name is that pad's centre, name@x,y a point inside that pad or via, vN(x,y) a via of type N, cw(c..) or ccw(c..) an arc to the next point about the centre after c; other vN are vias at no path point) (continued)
VA2P5_LMH5401_1: C3.2 C5.2 C7.1 C9.1 C18.1 C20.1 C22.2 C24.2 C25.2 C29.1 C30.1 C31.1 C32.1 C33.1 C34.1 C658.1 C663.2 C664.1 J64.2 J67.2 L52.2 R1.2 R5.2 R19.1 R556.2 TP46.1 U1.1 U1.10 U2.8 U2.13 U3.5 | length 2469.8
  L1_Top Layer w10: 674.32,8869.53 692.2,8869.53 v1@698.24,8863.48 ; 674.32,8990.48 692.2,8990.48 v1@698.24,8996.53 ; C24.2@1104.09,8829.05 C24.2@1092.94,8829.05 ; C5.2@1104.09,9033.46 C5.2@1099.09,9033.46 C5.2@1092.94,9033.46 ; C22.2@680.37,8843.79 C22.2@698.91,8843.79 ; C22.2@680.37,8843.79 685.32,8851.99 v1(692.26,8863.48) ; C22.2@680.37,8843.79 680.37,8863.48 ; 680.37,8863.48 v1(692.26,8863.48) ; 680.37,8863.48 680.19,8863.48 668.6,8875.08 U1.10@668.6,8885.71 U1.1@668.6,8974.3 668.6,8984.93 680.19,8996.53 680.37,8996.53 ; 680.37,8996.53 v1(692.26,8996.53) ; 680.37,8996.53 C3.2@680.37,9016.23 ; C3.2@680.37,9016.23 684.45,9009.46 685.32,9008.02 v1(692.26,8996.53) ; C3.2@680.37,9016.23 C3.2@698.91,9016.23 ; v1(692.26,8863.48) v1@698.24,8863.48 ; v1(692.26,8863.48) 692.26,8850.44 C22.2@698.91,8843.79 ; v1(692.26,8996.53) v1@698.24,8996.53 ; v1(692.26,8996.53) 692.26,9009.58 C3.2@698.91,9016.23 ; v1@698.24,8863.48 698.91,8862.81 C22.2@698.91,8843.79 ; v1@698.24,8996.53 698.91,8997.2 C3.2@698.91,9016.23 ; C24.2@1092.2,8827.82 C24.2@1092.94,8829.05 ; C24.2@1092.2,8827.82 C24.2@1092.2,8829.05 ; C24.2@1092.2,8827.82 C24.2@1110.74,8827.82 ; C24.2@1092.2,8829.05 C24.2@1092.94,8829.05 ; C24.2@1092.2,8829.05 1090.52,8829.05 1087.99,8831.58 v1(1087.99,8851.58) 1073.62,8865.95 U2.8@1073.62,8876.14 1073.62,8893.23 1062.54,8904.31 1062.54,8963.12 1073.62,8974.2 U2.13@1073.62,8986.38 1073.62,8996.56 v1(1087.99,9010.93) 1087.99,9030.93 1090.52,9033.46 C5.2@1092.2,9033.46 ; C24.2@1092.2,8829.05 v1@1092.2,8847.52 ; v1@1092.2,8847.52 1104.09,8847.52 ; v1@1092.2,8847.52 1086.15,8853.56 1104.03,8853.56 1110.07,8847.52 ; v1@1092.2,9015 C5.2@1092.2,9033.46 ; v1@1092.2,9015 1104.09,9015 ; v1@1092.2,9015 1086.15,9008.96 1104.03,9008.96 1110.07,9015 ; C5.2@1092.2,9033.46 C5.2@1092.94,9033.46 ; C5.2@1092.2,9033.46 C5.2@1092.2,9034.7 ; C5.2@1092.2,9034.7 C5.2@1092.94,9033.46 ; C5.2@1092.2,9034.7 C5.2@1110.74,9034.7 ; C24.2@1092.94,8829.05 1094.59,8831.77 1095.92,8833.99 1097.15,8836.02 1104.09,8847.52 ; C5.2@1092.94,9033.46 1094.59,9030.74 1095.92,9028.53 1097.15,9026.49 1104.09,9015 ; 1104.09,8847.52 1110.07,8847.52 ; 1104.09,8847.52 1104.09,8834.47 C24.2@1110.74,8827.82 ; 1104.09,9015 1110.07,9015 ; 1104.09,9015 1104.09,9028.05 C5.2@1110.74,9034.7 ; 1110.07,8847.52 1110.74,8846.85 C24.2@1110.74,8827.82 ; 1110.07,9015 1110.74,9015.67 C5.2@1110.74,9034.7
  L1_Top Layer w11: v2(1307.71,8651.26) 1364.21,8651.26 U3.5@1364.8,8650.67
  L1_Top Layer w15: v2(1307.71,8651.26) 1307.71,8594.29 1354.84,8547.16 R556.2@1508.91,8547.16
  L1_Top Layer w17: v1(661.62,8918.63) v1(661.62,8943.33) ; v1(1058.18,8948) 1058.18,8914.29 v1(1058.48,8914)
  L1_Top Layer w20: v2@407,8914.62 R19.1@430.22,8891.41 ; v2(407,8946) 407,8946.36 R5.2@430.22,8969.57 ; C32.1@521.53,9169.99 v2(555.25,9169.99) ; C31.1@521.53,9219.99 v2(555.25,9219.99) ; v2(544.09,9299.99) v2(599.34,9299.99) ; R1.2@729.91,9234.41 v2(729.91,9268.12) ; v2(921.66,9296.71) C30.1@976.91,9296.71 ; v2(970.75,9166.71) C34.1@1004.47,9166.71 ; v2(970.75,9216.71) C33.1@1004.47,9216.71
  L1_Top Layer w30: TP46.1@580,9414 592.71,9401.29 C664.1@711.91,9401.29
  L12_Bottom Layer w10: v1@688.01,8865.45 680.81,8858.25 680.81,8845.75 C18.1@698.91,8845.75 ; v1@688.01,8996.53 680.81,9003.73 680.81,9016.23 C7.1@698.91,9016.23 ; v1@690.77,8865.45 v1@692.26,8865.45 ; v1@690.77,8996.53 v1(692.26,8996.53) ; v1(1087.99,8851.58) 1087.99,8831.58 1090.52,8829.05 C20.1@1092.2,8829.05 ; v1(1087.99,9010.93) 1087.99,9030.93 1090.52,9033.46 C9.1@1092.2,9033.46 ; C20.1@1104.09,8829.05 C20.1@1099.09,8829.05 C20.1@1092.94,8829.05 ; C9.1@1104.09,9033.46 C9.1@1099.09,9033.46 C9.1@1092.94,9033.46 ; v1@692.26,8865.45 v1(692.26,8863.48) 692.26,8852.4 C18.1@698.91,8845.75 ; v1@692.26,8865.45 695.01,8865.45 702.21,8858.25 702.21,8849.06 C18.1@698.91,8845.75 ; v1(692.26,8996.53) 692.26,9009.58 C7.1@698.91,9016.23 ; v1(692.26,8996.53) 695.01,8996.53 702.21,9003.73 702.21,9012.92 C7.1@698.91,9016.23 ; C20.1@1092.2,8827.82 C20.1@1092.2,8829.05 ; C20.1@1092.2,8827.82 C20.1@1092.94,8829.05 ; C20.1@1092.2,8827.82 C20.1@1110.74,8827.82 ; C20.1@1092.2,8829.05 C20.1@1092.94,8829.05 ; C20.1@1092.2,8829.05 v1@1092.2,8847.52 ; v1@1092.2,8847.52 1104.09,8847.52 ; v1@1092.2,8847.52 1086.15,8853.56 1104.03,8853.56 1110.07,8847.52 ; v1@1092.2,9015 1104.09,9015 ; v1@1092.2,9015 C9.1@1092.2,9033.46 ; v1@1092.2,9015 1086.15,9008.96 1104.03,9008.96 1110.07,9015 ; C9.1@1092.2,9033.46 C9.1@1092.94,9033.46 ; C9.1@1092.2,9033.46 C9.1@1092.2,9034.7 ; C9.1@1092.2,9034.7 C9.1@1092.94,9033.46 ; C9.1@1092.2,9034.7 C9.1@1110.74,9034.7 ; C20.1@1092.94,8829.05 1094.59,8831.77 1095.92,8833.99 1097.15,8836.02 1104.09,8847.52 ; C9.1@1092.94,9033.46 1094.59,9030.74 1095.92,9028.53 1097.15,9026.49 1104.09,9015 ; 1104.09,8847.52 1104.09,8834.47 C20.1@1110.74,8827.82 ; 1104.09,8847.52 1110.07,8847.52 ; 1104.09,9015 1104.09,9028.05 C9.1@1110.74,9034.7 ; 1104.09,9015 1110.07,9015 ; 1110.07,8847.52 1110.74,8846.85 C20.1@1110.74,8827.82 ; 1110.07,9015 1110.74,9015.67 C9.1@1110.74,9034.7
  L12_Bottom Layer w14: v1@686.41,8858.25 692.26,8852.4 ; 686.41,9003.73 692.26,9009.58
  other v2: 406.64,8914.62 976.91,9295.77 755.05,9351.57 810.3,9351.57 865.55,9351.57 920.8,9351.57
VA2P5_LMH5401_2: C37.2 C39.2 C41.1 C43.1 C52.1 C54.1 C56.2 C58.2 C59.2 C63.1 C64.1 C65.1 C66.1 C67.1 C68.1 C670.1 C672.2 C673.1 J68.2 J78.2 L54.2 R25.2 R29.2 R43.1 R565.2 TP48.1 U4.1 U4.10 U5.8 U5.13 U6.5 | length 2462.6
  L1_Top Layer w10: 676.12,7447.4 693.99,7447.4 v1@700.04,7441.35 ; 676.12,7568.36 693.99,7568.36 v1@700.04,7574.4 ; C58.2@1105.89,7406.93 C58.2@1094.74,7406.93 ; C39.2@1105.89,7611.34 C39.2@1100.89,7611.34 C39.2@1094.74,7611.34 ; C56.2@682.16,7421.66 C56.2@700.71,7421.66 ; C56.2@682.16,7421.66 687.12,7429.86 v1(694.06,7441.35) ; C56.2@682.16,7421.66 682.16,7441.35 ; 682.16,7441.35 681.99,7441.35 670.39,7452.95 U4.10@670.39,7463.59 U4.1@670.39,7552.17 670.39,7562.8 681.99,7574.4 682.16,7574.4 ; 682.16,7441.35 v1(694.06,7441.35) ; 682.16,7574.4 v1(694.06,7574.4) ; 682.16,7574.4 C37.2@682.16,7594.1 ; C37.2@682.16,7594.1 686.25,7587.34 687.12,7585.89 v1(694.06,7574.4) ; C37.2@682.16,7594.1 C37.2@700.71,7594.1 ; v1(694.06,7441.35) 694.06,7428.31 C56.2@700.71,7421.66 ; v1(694.06,7441.35) v1@700.04,7441.35 ; v1(694.06,7574.4) 694.06,7587.45 C37.2@700.71,7594.1 ; v1(694.06,7574.4) v1@700.04,7574.4 ; v1@700.04,7441.35 700.71,7440.69 C56.2@700.71,7421.66 ; v1@700.04,7574.4 700.71,7575.07 C37.2@700.71,7594.1 ; C58.2@1094,7405.69 C58.2@1094,7406.93 ; C58.2@1094,7405.69 C58.2@1094.74,7406.93 ; C58.2@1094,7405.69 C58.2@1112.54,7405.69 ; C58.2@1094,7406.93 C58.2@1094.74,7406.93 ; C58.2@1094,7406.93 1092.32,7406.93 1089.79,7409.46 v1(1089.79,7429.46) 1075.42,7443.83 U5.8@1075.42,7454.01 1075.42,7471.11 1064.34,7482.19 1064.34,7541 1075.42,7552.08 U5.13@1075.42,7564.25 1075.42,7574.43 v1(1089.79,7588.8) 1089.79,7608.8 1092.32,7611.34 C39.2@1094,7611.34 ; C58.2@1094,7406.93 v1@1094,7425.39 ; v1@1094,7425.39 1105.89,7425.39 ; v1@1094,7425.39 1087.95,7431.43 1105.83,7431.43 1111.87,7425.39 ; v1@1094,7592.87 1105.89,7592.87 ; v1@1094,7592.87 C39.2@1094,7611.34 ; v1@1094,7592.87 1087.95,7586.83 1105.83,7586.83 1111.87,7592.87 ; C39.2@1094,7611.34 C39.2@1094.74,7611.34 ; C39.2@1094,7611.34 C39.2@1094,7612.57 ; C39.2@1094,7612.57 C39.2@1094.74,7611.34 ; C39.2@1094,7612.57 C39.2@1112.54,7612.57 ; C58.2@1094.74,7406.93 1096.38,7409.65 1097.72,7411.86 1098.95,7413.9 1105.89,7425.39 ; C39.2@1094.74,7611.34 1096.38,7608.61 1097.72,7606.4 1098.95,7604.36 1105.89,7592.87 ; 1105.89,7425.39 1105.89,7412.34 C58.2@1112.54,7405.69 ; 1105.89,7425.39 1111.87,7425.39 ; 1105.89,7592.87 1105.89,7605.92 C39.2@1112.54,7612.57 ; 1105.89,7592.87 1111.87,7592.87 ; 1111.87,7425.39 1112.54,7424.72 C58.2@1112.54,7405.69 ; 1111.87,7592.87 1112.54,7593.54 C39.2@1112.54,7612.57
  L1_Top Layer w11: v2(1309.51,7229.13) 1366.01,7229.13 U6.5@1366.6,7228.54
  L1_Top Layer w15: v2(1309.51,7229.13) 1309.51,7188.59 1373.06,7125.04 R565.2@1510.71,7125.04
  L1_Top Layer w17: v1(663.42,7496.5) v1(663.42,7521.2) ; v1(1059.98,7525.87) 1059.98,7492.17 v1(1060.28,7491.87)
  L1_Top Layer w20: v2@408.8,7492.5 R43.1@432.01,7469.28 ; v2@408.8,7524.23 R29.2@432.01,7547.45 ; C66.1@523.33,7747.86 v2(557.05,7747.86) ; C65.1@523.33,7797.86 v2(557.05,7797.86) ; v2(545.89,7877.86) v2(601.14,7877.86) ; R25.2@731.71,7812.28 v2(731.71,7846) ; v2(923.46,7874.58) C64.1@978.71,7874.58 ; v2(972.55,7744.58) C68.1@1006.27,7744.58 ; v2(972.55,7794.58) C67.1@1006.27,7794.58
  L1_Top Layer w30: TP48.1@579,7992 591.84,7979.16 C673.1@713.71,7979.16
  L12_Bottom Layer w10: v1@689.81,7443.32 682.61,7436.12 682.61,7423.63 C52.1@700.71,7423.63 ; v1@689.81,7574.4 682.61,7581.6 682.61,7594.1 C41.1@700.71,7594.1 ; v1@692.56,7443.32 v1@694.06,7443.32 ; v1@692.56,7574.4 v1(694.06,7574.4) ; v1(1089.79,7429.46) 1089.79,7409.46 1092.32,7406.93 C54.1@1094,7406.93 ; v1(1089.79,7588.8) 1089.79,7608.8 1092.32,7611.34 C43.1@1094,7611.34 ; C54.1@1105.89,7406.93 C54.1@1094.74,7406.93 ; C43.1@1105.89,7611.34 C43.1@1100.89,7611.34 C43.1@1094.74,7611.34 ; v1@694.06,7443.32 v1(694.06,7441.35) 694.06,7430.28 C52.1@700.71,7423.63 ; v1@694.06,7443.32 696.81,7443.32 704.01,7436.12 704.01,7426.93 C52.1@700.71,7423.63 ; v1(694.06,7574.4) 694.06,7587.45 C41.1@700.71,7594.1 ; v1(694.06,7574.4) 696.81,7574.4 704.01,7581.6 704.01,7590.8 C41.1@700.71,7594.1 ; C54.1@1094,7405.69 C54.1@1094,7406.93 ; C54.1@1094,7405.69 C54.1@1094.74,7406.93 ; C54.1@1094,7405.69 C54.1@1112.54,7405.69 ; C54.1@1094,7406.93 C54.1@1094.74,7406.93 ; C54.1@1094,7406.93 v1@1094,7425.39 ; v1@1094,7425.39 1105.89,7425.39 ; v1@1094,7425.39 1087.95,7431.43 1105.83,7431.43 1111.87,7425.39 ; v1@1094,7592.87 1105.89,7592.87 ; v1@1094,7592.87 C43.1@1094,7611.34 ; v1@1094,7592.87 1087.95,7586.83 1105.83,7586.83 1111.87,7592.87 ; C43.1@1094,7611.34 C43.1@1094.74,7611.34 ; C43.1@1094,7611.34 C43.1@1094,7612.57 ; C43.1@1094,7612.57 C43.1@1094.74,7611.34 ; C43.1@1094,7612.57 C43.1@1112.54,7612.57 ; C54.1@1094.74,7406.93 1096.38,7409.65 1097.72,7411.86 1098.95,7413.9 1105.89,7425.39 ; C43.1@1094.74,7611.34 1096.38,7608.61 1097.72,7606.4 1098.95,7604.36 1105.89,7592.87 ; 1105.89,7425.39 1105.89,7412.34 C54.1@1112.54,7405.69 ; 1105.89,7425.39 1111.87,7425.39 ; 1105.89,7592.87 1105.89,7605.92 C43.1@1112.54,7612.57 ; 1105.89,7592.87 1111.87,7592.87 ; 1111.87,7425.39 1112.54,7424.72 C54.1@1112.54,7405.69 ; 1111.87,7592.87 1112.54,7593.54 C43.1@1112.54,7612.57
  L12_Bottom Layer w14: v1@688.21,7436.12 694.06,7430.28 ; 688.21,7581.6 694.06,7587.45
  other v2: 408.44,7492.5 408.8,7523.87 978.71,7873.64 756.84,7929.44 812.1,7929.44 867.35,7929.44 922.6,7929.44
VA2P5_LMH5401_3: C163.2 C165.2 C167.1 C169.1 C178.1 C180.1 C182.2 C184.2 C185.2 C189.1 C190.1 C191.1 C192.1 C193.1 C194.1 C659.1 C665.2 C666.1 J79.2 J82.2 L53.2 R82.2 R86.2 R100.1 R574.2 TP47.1 U10.1 U10.10 U11.8 U11.13 U12.5 | length 2462.5
  L1_Top Layer w10: 677.64,2523.16 695.51,2523.16 v1@701.56,2517.12 ; 677.64,2644.12 695.51,2644.12 v1@701.56,2650.17 ; C184.2@1107.41,2482.69 C184.2@1096.26,2482.69 ; C165.2@1107.41,2687.1 C165.2@1102.41,2687.1 C165.2@1096.26,2687.1 ; C182.2@683.68,2497.42 C182.2@702.23,2497.42 ; C182.2@683.68,2497.42 688.64,2505.63 v1(695.58,2517.12) ; C182.2@683.68,2497.42 683.68,2517.12 ; 683.68,2517.12 v1(695.58,2517.12) ; 683.68,2517.12 683.51,2517.12 671.91,2528.72 U10.10@671.91,2539.35 U10.1@671.91,2627.94 671.91,2638.57 683.51,2650.17 683.68,2650.17 ; 683.68,2650.17 v1(695.58,2650.17) ; 683.68,2650.17 C163.2@683.68,2669.86 ; C163.2@683.68,2669.86 687.77,2663.1 688.64,2661.66 v1(695.58,2650.17) ; C163.2@683.68,2669.86 C163.2@702.23,2669.86 ; v1(695.58,2517.12) 695.58,2504.07 C182.2@702.23,2497.42 ; v1(695.58,2517.12) v1@701.56,2517.12 ; v1(695.58,2650.17) 695.58,2663.21 C163.2@702.23,2669.86 ; v1(695.58,2650.17) v1@701.56,2650.17 ; v1@701.56,2517.12 702.23,2516.45 C182.2@702.23,2497.42 ; v1@701.56,2650.17 702.23,2650.84 C163.2@702.23,2669.86 ; C184.2@1095.52,2481.46 C184.2@1096.26,2482.69 ; C184.2@1095.52,2481.46 C184.2@1095.52,2482.69 ; C184.2@1095.52,2481.46 C184.2@1114.06,2481.46 ; C184.2@1095.52,2482.69 C184.2@1096.26,2482.69 ; C184.2@1095.52,2482.69 1093.84,2482.69 1091.31,2485.22 v1(1091.31,2505.22) 1076.94,2519.59 U11.8@1076.94,2529.78 1076.94,2546.87 1065.86,2557.95 1065.86,2616.76 1076.94,2627.84 U11.13@1076.94,2640.01 1076.94,2650.2 v1(1091.31,2664.57) 1091.31,2684.57 1093.84,2687.1 C165.2@1095.52,2687.1 ; C184.2@1095.52,2482.69 v1@1095.52,2501.15 ; v1@1095.52,2501.15 1107.41,2501.15 ; v1@1095.52,2501.15 1089.47,2507.2 1107.35,2507.2 1113.39,2501.15 ; v1@1095.52,2668.64 C165.2@1095.52,2687.1 ; v1@1095.52,2668.64 1107.41,2668.64 ; v1@1095.52,2668.64 1089.47,2662.59 1107.35,2662.59 1113.39,2668.64 ; C165.2@1095.52,2687.1 C165.2@1096.26,2687.1 ; C165.2@1095.52,2687.1 C165.2@1095.52,2688.33 ; C165.2@1095.52,2688.33 C165.2@1096.26,2687.1 ; C165.2@1095.52,2688.33 C165.2@1114.06,2688.33 ; C184.2@1096.26,2482.69 1097.9,2485.41 1099.24,2487.62 1100.47,2489.66 1107.41,2501.15 ; C165.2@1096.26,2687.1 1097.9,2684.38 1099.24,2682.17 1100.47,2680.13 1107.41,2668.64 ; 1107.41,2501.15 1113.39,2501.15 ; 1107.41,2501.15 1107.41,2488.11 C184.2@1114.06,2481.46 ; 1107.41,2668.64 1113.39,2668.64 ; 1107.41,2668.64 1107.41,2681.68 C165.2@1114.06,2688.33 ; 1113.39,2501.15 1114.06,2500.48 C184.2@1114.06,2481.46 ; 1113.39,2668.64 1114.06,2669.31 C165.2@1114.06,2688.33
  L1_Top Layer w11: v1(1311.03,2304.9) 1367.53,2304.9 U12.5@1368.12,2304.31
  L1_Top Layer w15: v1(1311.03,2304.9) 1311.03,2271.35 1381.58,2200.8 R574.2@1512.23,2200.8
  L1_Top Layer w17: v1(664.94,2572.27) v1(664.94,2596.97) ; v1(1061.5,2601.64) 1061.5,2567.93 v1(1061.79,2567.64)
  L1_Top Layer w20: v2@410.32,2568.26 R100.1@433.53,2545.05 ; v2@410.32,2600 R86.2@433.53,2623.21 ; C192.1@524.85,2823.63 v2(558.57,2823.63) ; C191.1@524.85,2873.63 v2(558.57,2873.63) ; v2(547.41,2953.63) v2(602.66,2953.63) ; R82.2@733.23,2888.05 v2(733.23,2921.76) ; v2(924.98,2950.34) C190.1@980.23,2950.34 ; v2(974.07,2820.34) C194.1@1007.79,2820.34 ; v2(974.07,2870.34) C193.1@1007.79,2870.34
  L1_Top Layer w30: TP47.1@580,3074 602.14,3051.86 C666.1@714.81,3051.86
  L12_Bottom Layer w10: v1@691.33,2519.09 684.13,2511.89 684.13,2499.39 C178.1@702.23,2499.39 ; v1@691.33,2650.17 684.13,2657.37 684.13,2669.86 C167.1@702.23,2669.86 ; v1@694.08,2519.09 v1@695.58,2519.09 ; v1@694.08,2650.17 v1(695.58,2650.17) ; v1(1091.31,2505.22) 1091.31,2485.22 1093.84,2482.69 C180.1@1095.52,2482.69 ; v1(1091.31,2664.57) 1091.31,2684.57 1093.84,2687.1 C169.1@1095.52,2687.1 ; C180.1@1107.41,2482.69 C180.1@1096.26,2482.69 ; C169.1@1107.41,2687.1 C169.1@1102.41,2687.1 C169.1@1096.26,2687.1 ; v1@695.58,2519.09 v1(695.58,2517.12) 695.58,2506.04 C178.1@702.23,2499.39 ; v1@695.58,2519.09 698.33,2519.09 705.53,2511.89 705.53,2502.69 C178.1@702.23,2499.39 ; v1(695.58,2650.17) 695.58,2663.21 C167.1@702.23,2669.86 ; v1(695.58,2650.17) 698.33,2650.17 705.53,2657.37 705.53,2666.56 C167.1@702.23,2669.86 ; C180.1@1095.52,2481.46 C180.1@1095.52,2482.69 ; C180.1@1095.52,2481.46 C180.1@1096.26,2482.69 ; C180.1@1095.52,2481.46 C180.1@1114.06,2481.46 ; C180.1@1095.52,2482.69 C180.1@1096.26,2482.69 ; C180.1@1095.52,2482.69 v1@1095.52,2501.15 ; v1@1095.52,2501.15 1107.41,2501.15 ; v1@1095.52,2501.15 1089.47,2507.2 1107.35,2507.2 1113.39,2501.15 ; v1@1095.52,2668.64 1107.41,2668.64 ; v1@1095.52,2668.64 C169.1@1095.52,2687.1 ; v1@1095.52,2668.64 1089.47,2662.59 1107.35,2662.59 1113.39,2668.64 ; C169.1@1095.52,2687.1 C169.1@1096.26,2687.1 ; C169.1@1095.52,2687.1 C169.1@1095.52,2688.33 ; C169.1@1095.52,2688.33 C169.1@1096.26,2687.1 ; C169.1@1095.52,2688.33 C169.1@1114.06,2688.33 ; C180.1@1096.26,2482.69 1097.9,2485.41 1099.24,2487.62 1100.47,2489.66 1107.41,2501.15 ; C169.1@1096.26,2687.1 1097.9,2684.38 1099.24,2682.17 1100.47,2680.13 1107.41,2668.64 ; 1107.41,2501.15 1107.41,2488.11 C180.1@1114.06,2481.46 ; 1107.41,2501.15 1113.39,2501.15 ; 1107.41,2668.64 1107.41,2681.68 C169.1@1114.06,2688.33 ; 1107.41,2668.64 1113.39,2668.64 ; 1113.39,2501.15 1114.06,2500.48 C180.1@1114.06,2481.46 ; 1113.39,2668.64 1114.06,2669.31 C169.1@1114.06,2688.33
  L12_Bottom Layer w14: v1@689.73,2511.89 695.58,2506.04 ; 689.73,2657.37 695.58,2663.21
  other v2: 409.96,2568.26 410.32,2599.64 980.23,2949.4 757.94,3002.14 813.19,3002.14 868.45,3002.14 923.7,3002.14
VA2P5_LMH5401_4: C197.2 C199.2 C201.1 C203.1 C212.1 C214.1 C216.2 C218.2 C219.2 C223.1 C224.1 C225.1 C226.1 C227.1 C228.1 C671.1 C674.2 C675.1 J83.2 J84.2 L55.2 R106.2 R110.2 R124.1 R583.2 TP49.1 U13.1 U13.10 U14.8 U14.13 U15.5 | length 2482.5
  L1_Top Layer w10: 677.71,1103.83 695.59,1103.83 v1@701.63,1097.78 ; 677.71,1224.79 695.59,1224.79 v1@701.63,1230.83 ; C218.2@1107.48,1063.36 C218.2@1096.34,1063.36 ; C199.2@1107.48,1267.77 C199.2@1102.48,1267.77 C199.2@1096.34,1267.77 ; C216.2@683.76,1078.09 C216.2@702.3,1078.09 ; C216.2@683.76,1078.09 688.71,1086.29 v1(695.65,1097.78) ; C216.2@683.76,1078.09 683.76,1097.78 ; 683.76,1097.78 v1(695.65,1097.78) ; 683.76,1097.78 683.59,1097.78 671.99,1109.38 U13.10@671.99,1120.02 U13.1@671.99,1208.6 671.99,1219.23 683.59,1230.83 683.76,1230.83 ; 683.76,1230.83 v1(695.65,1230.83) ; 683.76,1230.83 C197.2@683.76,1250.53 ; C197.2@683.76,1250.53 687.84,1243.77 688.71,1242.32 v1(695.65,1230.83) ; C197.2@683.76,1250.53 C197.2@702.3,1250.53 ; v1(695.65,1097.78) 695.65,1084.74 C216.2@702.3,1078.09 ; v1(695.65,1097.78) v1@701.63,1097.78 ; v1(695.65,1230.83) 695.65,1243.88 C197.2@702.3,1250.53 ; v1(695.65,1230.83) v1@701.63,1230.83 ; v1@701.63,1097.78 702.3,1097.12 C216.2@702.3,1078.09 ; v1@701.63,1230.83 702.3,1231.5 C197.2@702.3,1250.53 ; C218.2@1095.59,1062.12 C218.2@1096.34,1063.36 ; C218.2@1095.59,1062.12 C218.2@1095.59,1063.36 ; C218.2@1095.59,1062.12 C218.2@1114.13,1062.12 ; C218.2@1095.59,1063.36 C218.2@1096.34,1063.36 ; C218.2@1095.59,1063.36 1093.91,1063.36 1091.38,1065.89 v1(1091.38,1085.89) 1077.01,1100.26 U14.8@1077.01,1110.44 1077.01,1127.54 1065.93,1138.62 1065.93,1197.43 1077.01,1208.51 U14.13@1077.01,1220.68 1077.01,1230.86 v1(1091.38,1245.23) 1091.38,1265.23 1093.91,1267.77 C199.2@1095.59,1267.77 ; C218.2@1095.59,1063.36 v1@1095.59,1081.82 ; v1@1095.59,1081.82 1107.48,1081.82 ; v1@1095.59,1081.82 1089.55,1087.86 1107.42,1087.86 1113.47,1081.82 ; v1@1095.59,1249.3 C199.2@1095.59,1267.77 ; v1@1095.59,1249.3 1107.48,1249.3 ; v1@1095.59,1249.3 1089.55,1243.26 1107.42,1243.26 1113.47,1249.3 ; C199.2@1095.59,1267.77 C199.2@1096.34,1267.77 ; C199.2@1095.59,1267.77 C199.2@1095.59,1269 ; C199.2@1095.59,1269 C199.2@1096.34,1267.77 ; C199.2@1095.59,1269 C199.2@1114.13,1269 ; C218.2@1096.34,1063.36 1097.98,1066.08 1099.31,1068.29 1100.55,1070.33 1107.48,1081.82 ; C199.2@1096.34,1267.77 1097.98,1265.04 1099.31,1262.83 1100.55,1260.79 1107.48,1249.3 ; 1107.48,1081.82 1113.47,1081.82 ; 1107.48,1081.82 1107.48,1068.77 C218.2@1114.13,1062.12 ; 1107.48,1249.3 1113.47,1249.3 ; 1107.48,1249.3 1107.48,1262.35 C199.2@1114.13,1269 ; 1113.47,1081.82 1114.13,1081.15 C218.2@1114.13,1062.12 ; 1113.47,1249.3 1114.13,1249.97 C199.2@1114.13,1269
  L1_Top Layer w11: v1(1311.11,885.56) 1367.6,885.56 U15.5@1368.19,884.97
  L1_Top Layer w15: v1(1311.11,885.56) 1311.11,809.67 1339.31,781.47 R583.2@1512.3,781.47
  L1_Top Layer w17: v1(665.01,1152.93) v1(665.01,1177.63) ; v1(1061.58,1182.3) 1061.58,1148.6 v1(1061.87,1148.3)
  L1_Top Layer w20: v2@410.39,1148.93 R124.1@433.61,1125.71 ; v2@410.39,1180.66 R110.2@433.61,1203.88 ; C226.1@524.92,1404.29 v2(558.64,1404.29) ; C225.1@524.92,1454.29 v2(558.64,1454.29) ; v2(547.48,1534.29) v2(602.74,1534.29) ; R106.2@733.3,1468.71 v2(733.3,1502.43) ; v2(925.05,1530.07) C224.1@980.3,1530.07 ; v2(974.15,1400.07) C228.1@1007.86,1400.07 ; v2(974.15,1450.07) C227.1@1007.86,1450.07
  L1_Top Layer w30: TP49.1@579,1647 589.41,1636.59 C675.1@713.88,1636.59
  L12_Bottom Layer w10: v1@691.4,1099.75 684.2,1092.55 684.2,1080.06 C212.1@702.3,1080.06 ; v1@691.4,1230.83 684.2,1238.03 684.2,1250.53 C201.1@702.3,1250.53 ; v1@694.16,1099.75 v1@695.65,1099.75 ; v1@694.16,1230.83 v1(695.65,1230.83) ; v1(1091.38,1085.89) 1091.38,1065.89 1093.91,1063.36 C214.1@1095.59,1063.36 ; v1(1091.38,1245.23) 1091.38,1265.23 1093.91,1267.77 C203.1@1095.59,1267.77 ; C214.1@1107.48,1063.36 C214.1@1096.34,1063.36 ; C203.1@1107.48,1267.77 C203.1@1102.48,1267.77 C203.1@1096.34,1267.77 ; v1@695.65,1099.75 v1(695.65,1097.78) 695.65,1086.71 C212.1@702.3,1080.06 ; v1@695.65,1099.75 698.41,1099.75 705.61,1092.55 705.61,1083.36 C212.1@702.3,1080.06 ; v1(695.65,1230.83) 698.41,1230.83 705.61,1238.03 705.61,1247.23 C201.1@702.3,1250.53 ; v1(695.65,1230.83) 695.65,1243.88 C201.1@702.3,1250.53 ; C214.1@1095.59,1062.12 C214.1@1096.34,1063.36 ; C214.1@1095.59,1062.12 C214.1@1095.59,1063.36 ; C214.1@1095.59,1062.12 C214.1@1114.13,1062.12 ; C214.1@1095.59,1063.36 C214.1@1096.34,1063.36 ; C214.1@1095.59,1063.36 v1@1095.59,1081.82 ; v1@1095.59,1081.82 1107.48,1081.82 ; v1@1095.59,1081.82 1089.55,1087.86 1107.42,1087.86 1113.47,1081.82 ; v1@1095.59,1249.3 C203.1@1095.59,1267.77 ; v1@1095.59,1249.3 1107.48,1249.3 ; v1@1095.59,1249.3 1089.55,1243.26 1107.42,1243.26 1113.47,1249.3 ; C203.1@1095.59,1267.77 C203.1@1096.34,1267.77 ; C203.1@1095.59,1267.77 C203.1@1095.59,1269 ; C203.1@1095.59,1269 C203.1@1096.34,1267.77 ; C203.1@1095.59,1269 C203.1@1114.13,1269 ; C214.1@1096.34,1063.36 1097.98,1066.08 1099.31,1068.29 1100.55,1070.33 1107.48,1081.82 ; C203.1@1096.34,1267.77 1097.98,1265.04 1099.31,1262.83 1100.55,1260.79 1107.48,1249.3 ; 1107.48,1081.82 1113.47,1081.82 ; 1107.48,1081.82 1107.48,1068.77 C214.1@1114.13,1062.12 ; 1107.48,1249.3 1113.47,1249.3 ; 1107.48,1249.3 1107.48,1262.35 C203.1@1114.13,1269 ; 1113.47,1081.82 1114.13,1081.15 C214.1@1114.13,1062.12 ; 1113.47,1249.3 1114.13,1249.97 C203.1@1114.13,1269
  L12_Bottom Layer w14: v1@689.81,1092.55 695.65,1086.71 ; 689.81,1238.03 695.65,1243.88
  other v2: 410.03,1148.93 410.39,1180.3 980.3,1529.13 757.02,1586.86 812.27,1586.86 867.52,1586.86 922.77,1586.86
VA_N2P5: C566.2 C567.2 C570.2 C572.2 C573.2 C574.2 J60.18 J60.20 J60.22 L61.1 L63.1 L65.1 L67.1 L86.1 TP58.1
  other v2: 686.59,441.43 707.83,483.09 664.04,483.64 708.38,526.88 664.59,527.43 686.21,1860.55 707.45,1902.21 663.66,1902.77 708,1946 664.21,1946.55 685,6785 662.45,6827.21 706.23,6826.66 663,6871 706.79,6870.45 683.2,8207.13 704.44,8248.79 660.65,8249.34 661.2,8293.13 704.99,8292.57 771,10020 945,10020 771,10078 945,10078 771,10136 829,10136 887,10136 945,10136
VA_N2P5_IN: C705.2 C706.2 C707.2 J60.17 J60.19 J60.21 L86.2 R630.2 U52.3
  other v2: 785,10435 824,10435 863,10435 902,10435 941,10435
VA_N2P5_LMH5401_1: C2.2 C4.2 C6.1 C8.1 C17.1 C19.1 C21.2 C23.2 C29.2 C30.2 C31.2 C32.2 C33.2 C34.2 C689.1 C693.2 C694.1 L61.2 R3.1 R553.2 R554.2 R557.1 TP55.1 U1.3 U1.8 U2.5 U2.16 U3.2 | length 2116.2
  L1_Top Layer w10: 617.63,8865.45 617.46,8865.45 ; 623.5,8871.5 605.62,8871.5 v1@599.58,8865.45 ; C23.2@984.09,8829.05 C23.2@995.24,8829.05 ; C4.2@984.09,9033.46 C4.2@995.24,9033.46 ; v1(1415.19,8655.93) 1415.19,8665.93 1425.52,8676.26 U3.2@1453.38,8676.26 ; C21.2@598.91,8845.75 C21.2@617.46,8845.75 ; C21.2@598.91,8845.75 605.56,8852.4 v1(605.56,8863.48) ; C21.2@598.91,8845.75 598.91,8864.78 v1@599.58,8865.45 ; C2.2@598.91,9018.19 C2.2@617.46,9018.19 ; C2.2@598.91,9018.19 605.56,9011.54 v1(605.56,8998.5) ; C2.2@598.91,9018.19 598.91,8999.17 v1@599.58,8998.5 ; v1@599.58,8865.45 v1@605.56,8865.45 ; v1@599.58,8998.5 v1(605.56,8998.5) ; v1@599.58,8998.5 605.62,8992.45 623.5,8992.45 ; v1(605.56,8863.48) v1@605.56,8865.45 ; v1(605.56,8863.48) v1@606.75,8863.48 ; v1@605.56,8865.45 617.46,8865.45 ; v1@605.56,8865.45 606.43,8864.01 v1@606.75,8863.48 ; v1(605.56,8998.5) 617.46,8998.5 ; v1(605.56,8998.5) 612.5,9009.99 C2.2@617.46,9018.19 ; v1@606.75,8863.48 617.46,8863.48 ; v1@606.75,8863.48 612.5,8853.96 613.37,8852.52 C21.2@617.46,8845.75 ; C21.2@617.46,8845.75 617.46,8863.48 ; 617.46,8863.48 617.46,8865.45 ; 617.46,8863.48 617.63,8863.48 629.23,8875.08 U1.8@629.23,8885.71 U1.3@629.23,8976.27 629.23,8986.73 623.5,8992.45 ; 617.46,8998.5 C2.2@617.46,9018.19 ; 617.46,8998.5 623.5,8992.45 ; C23.2@977.44,8827.82 C23.2@995.99,8827.82 ; C23.2@977.44,8827.82 984.09,8834.47 984.09,8847.52 ; C23.2@977.44,8827.82 977.44,8846.85 978.11,8847.52 ; C4.2@977.44,9034.7 C4.2@995.99,9034.7 ; C4.2@977.44,9034.7 984.09,9028.05 984.09,9015 ; C4.2@977.44,9034.7 977.44,9015.67 978.11,9015 ; 978.11,8847.52 984.09,8847.52 ; 978.11,8847.52 984.16,8853.56 1002.03,8853.56 v1@995.99,8847.52 ; 978.11,9015 984.16,9008.96 1002.03,9008.96 v1@995.99,9015 ; 978.11,9015 984.09,9015 ; 984.09,8847.52 v1@995.99,8847.52 ; 984.09,8847.52 991.03,8836.02 992.26,8833.99 C23.2@995.24,8829.05 ; 984.09,9015 991.03,9026.49 992.26,9028.53 C4.2@995.24,9033.46 ; 984.09,9015 v1@995.99,9015 ; C23.2@995.24,8829.05 C23.2@995.99,8827.82 ; C23.2@995.24,8829.05 C23.2@995.99,8829.05 ; C4.2@995.24,9033.46 C4.2@995.99,9034.7 ; C4.2@995.24,9033.46 C4.2@995.99,9033.46 ; C23.2@995.99,8827.82 C23.2@995.99,8829.05 ; C23.2@995.99,8829.05 v1@995.99,8847.52 ; C23.2@995.99,8829.05 997.66,8829.05 1000.19,8831.58 v1(1000.19,8851.58) 1014.56,8865.95 U2.5@1014.56,8876.14 1014.56,8890.64 1025.64,8901.72 1025.64,8963.12 1014.56,8974.2 U2.16@1014.56,8986.38 1014.56,8996.56 v1(1000.19,9010.93) 1000.19,9030.93 997.66,9033.46 C4.2@995.99,9033.46 ; v1@995.99,9015 C4.2@995.99,9033.46 ; C4.2@995.99,9033.46 C4.2@995.99,9034.7
  L1_Top Layer w15: R557.1@1558.91,8547.16 1558.91,8512.21 v2(1560.19,8510.93)
  L1_Top Layer w17: v1(636.2,8918.63) v1(636.2,8943.33) ; v1(1029.71,8914) 1030,8914.29 v1(1030,8948)
  L1_Top Layer w20: v2@372,8879.62 R554.2@395.22,8856.41 ; v2@372,8981.36 R553.2@395.22,9004.57 ; v2(386.48,9300.93) C29.2@441.73,9300.93 ; v2(440.57,9169.99) C32.2@474.29,9169.99 ; v2(440.57,9219.99) C31.2@474.29,9219.99 ; v2(595.19,9233.23) R3.1@628.91,9233.23 ; C34.2@1051.71,9166.71 v2(1085.43,9166.71) ; C33.2@1051.71,9216.71 v2(1085.43,9216.71) ; v2(1079.27,9295.77) v2(1134.53,9295.77)
  L12_Bottom Layer w10: v1@607.06,8863.48 v1(605.56,8863.48) ; v1@607.06,8998.5 v1(605.56,8998.5) ; v1@609.81,8863.48 617.01,8856.28 ; v1@609.81,8998.5 617.01,9005.7 ; C17.1@617.01,8847.09 617.01,8856.28 ; C6.1@617.01,9014.89 617.01,9005.7 ; C17.1@622.61,8843.79 C17.1@598.91,8843.79 ; C6.1@622.61,9018.19 C6.1@598.91,9018.19 ; C19.1@984.09,8829.05 C19.1@995.24,8829.05 ; C8.1@984.09,9033.46 C8.1@995.24,9033.46 ; v1(1000.19,8851.58) 1000.19,8831.58 997.66,8829.05 C19.1@995.99,8829.05 ; v1(1000.19,9010.93) 1000.19,9030.93 997.66,9033.46 C8.1@995.99,9033.46 ; C17.1@598.91,8843.79 C17.1@605.56,8850.44 ; C17.1@598.91,8843.79 595.61,8847.09 595.61,8856.28 602.81,8863.48 v1(605.56,8863.48) ; C6.1@598.91,9018.19 595.61,9014.89 595.61,9005.7 602.81,8998.5 v1(605.56,8998.5) ; C6.1@598.91,9018.19 C6.1@605.56,9011.54 ; C17.1@605.56,8850.44 v1(605.56,8863.48) ; C17.1@605.56,8850.44 611.41,8856.28 617.01,8856.28 ; v1(605.56,8998.5) C6.1@605.56,9011.54 ; C6.1@605.56,9011.54 611.41,9005.7 617.01,9005.7 ; C19.1@977.44,8827.82 C19.1@995.99,8827.82 ; C19.1@977.44,8827.82 984.09,8834.47 984.09,8847.52 ; C19.1@977.44,8827.82 977.44,8846.85 978.11,8847.52 ; C8.1@977.44,9034.7 984.09,9028.05 984.09,9015 ; C8.1@977.44,9034.7 C8.1@995.99,9034.7 ; C8.1@977.44,9034.7 977.44,9015.67 978.11,9015 ; 978.11,8847.52 984.16,8853.56 1002.03,8853.56 v1@995.99,8847.52 ; 978.11,8847.52 984.09,8847.52 ; 978.11,9015 984.16,9008.96 1002.03,9008.96 v1@995.99,9015 ; 978.11,9015 984.09,9015 ; 984.09,8847.52 991.03,8836.02 992.26,8833.99 C19.1@995.24,8829.05 ; 984.09,8847.52 v1@995.99,8847.52 ; 984.09,9015 991.03,9026.49 992.26,9028.53 C8.1@995.24,9033.46 ; 984.09,9015 v1@995.99,9015 ; C19.1@995.24,8829.05 C19.1@995.99,8827.82 ; C19.1@995.24,8829.05 C19.1@995.99,8829.05 ; C8.1@995.24,9033.46 C8.1@995.99,9034.7 ; C8.1@995.24,9033.46 C8.1@995.99,9033.46 ; C19.1@995.99,8827.82 C19.1@995.99,8829.05 ; C19.1@995.99,8829.05 v1@995.99,8847.52 ; v1@995.99,9015 C8.1@995.99,9033.46 ; C8.1@995.99,9033.46 C8.1@995.99,9034.7
  other v2: 833.83,8349.22 833.83,8404.47 833.83,8459.73 833.83,8514.98 833.83,8570.23 371.64,8879.62 372,8981 441.73,9299.99
VA_N2P5_LMH5401_2: C36.2 C38.2 C40.1 C42.1 C51.1 C53.1 C55.2 C57.2 C63.2 C64.2 C65.2 C66.2 C67.2 C68.2 C700.1 C703.2 C704.1 L63.2 R27.1 R562.2 R563.2 R566.1 TP57.1 U4.3 U4.8 U5.5 U5.16 U6.2 | length 2117.8
  L1_Top Layer w10: 619.42,7443.32 619.25,7443.32 ; 625.3,7449.37 607.42,7449.37 v1@601.38,7443.32 ; C57.2@985.89,7406.93 C57.2@997.04,7406.93 ; C38.2@985.89,7611.34 C38.2@997.04,7611.34 ; v1(1416.99,7233.8) 1416.99,7243.8 1427.32,7254.13 U6.2@1455.18,7254.13 ; C55.2@600.71,7423.63 607.36,7430.28 v1(607.36,7441.35) ; C55.2@600.71,7423.63 C55.2@619.25,7423.63 ; C55.2@600.71,7423.63 600.71,7442.65 v1@601.38,7443.32 ; C36.2@600.71,7596.07 600.71,7577.04 v1@601.38,7576.37 ; C36.2@600.71,7596.07 607.36,7589.42 v1(607.36,7576.37) ; C36.2@600.71,7596.07 C36.2@619.25,7596.07 ; v1@601.38,7443.32 v1@607.36,7443.32 ; v1@601.38,7576.37 v1(607.36,7576.37) ; v1@601.38,7576.37 607.42,7570.33 625.3,7570.33 ; v1(607.36,7441.35) v1@607.36,7443.32 ; v1(607.36,7441.35) v1@608.55,7441.35 ; v1@607.36,7443.32 619.25,7443.32 ; v1@607.36,7443.32 608.23,7441.88 v1@608.55,7441.35 ; v1(607.36,7576.37) 614.3,7587.86 C36.2@619.25,7596.07 ; v1(607.36,7576.37) 619.25,7576.37 ; v1@608.55,7441.35 619.25,7441.35 ; v1@608.55,7441.35 614.3,7431.83 615.17,7430.39 C55.2@619.25,7423.63 ; C55.2@619.25,7423.63 619.25,7441.35 ; 619.25,7441.35 619.42,7441.35 631.02,7452.95 U4.8@631.02,7463.59 U4.3@631.02,7554.14 631.02,7564.6 625.3,7570.33 ; 619.25,7441.35 619.25,7443.32 ; 619.25,7576.37 625.3,7570.33 ; 619.25,7576.37 C36.2@619.25,7596.07 ; C57.2@979.24,7405.69 985.89,7412.34 985.89,7425.39 ; C57.2@979.24,7405.69 C57.2@997.78,7405.69 ; C57.2@979.24,7405.69 979.24,7424.72 979.91,7425.39 ; C38.2@979.24,7612.57 985.89,7605.92 985.89,7592.87 ; C38.2@979.24,7612.57 979.24,7593.54 979.91,7592.87 ; C38.2@979.24,7612.57 C38.2@997.78,7612.57 ; 979.91,7425.39 985.95,7431.43 1003.83,7431.43 v1@997.78,7425.39 ; 979.91,7425.39 985.89,7425.39 ; 979.91,7592.87 985.89,7592.87 ; 979.91,7592.87 985.95,7586.83 1003.83,7586.83 v1@997.78,7592.87 ; 985.89,7425.39 992.83,7413.9 994.06,7411.86 C57.2@997.04,7406.93 ; 985.89,7425.39 v1@997.78,7425.39 ; 985.89,7592.87 v1@997.78,7592.87 ; 985.89,7592.87 992.83,7604.36 994.06,7606.4 C38.2@997.04,7611.34 ; C57.2@997.04,7406.93 C57.2@997.78,7406.93 ; C57.2@997.04,7406.93 C57.2@997.78,7405.69 ; C38.2@997.04,7611.34 C38.2@997.78,7612.57 ; C38.2@997.04,7611.34 C38.2@997.78,7611.34 ; C57.2@997.78,7405.69 C57.2@997.78,7406.93 ; C57.2@997.78,7406.93 999.46,7406.93 1001.99,7409.46 v1(1001.99,7429.46) 1016.36,7443.83 U5.5@1016.36,7454.01 1016.36,7468.52 1027.44,7479.6 1027.44,7541 1016.36,7552.08 U5.16@1016.36,7564.25 1016.36,7574.43 v1(1001.99,7588.8) 1001.99,7608.8 999.46,7611.34 C38.2@997.78,7611.34 ; C57.2@997.78,7406.93 v1@997.78,7425.39 ; v1@997.78,7592.87 C38.2@997.78,7611.34 ; C38.2@997.78,7611.34 C38.2@997.78,7612.57
  L1_Top Layer w15: R566.1@1560.71,7125.04 1560.71,7090.09 v2(1561.99,7088.8)
  L1_Top Layer w17: v1(638,7496.5) v1(638,7521.2) ; v1(1031.5,7491.87) 1031.8,7492.17 v1(1031.8,7525.87)
  L1_Top Layer w20: v2@373.8,7457.5 R563.2@397.01,7434.28 ; v2@373.8,7559.23 R562.2@397.01,7582.45 ; v2(388.28,7878.8) C63.2@443.53,7878.8 ; v2(442.37,7747.86) C66.2@476.09,7747.86 ; v2(442.37,7797.86) C65.2@476.09,7797.86 ; v2(596.99,7811.11) R27.1@630.71,7811.11 ; C68.2@1053.51,7744.58 v2(1087.23,7744.58) ; C67.2@1053.51,7794.58 v2(1087.23,7794.58) ; v2(1081.07,7873.64) v2(1136.32,7873.64)
  L12_Bottom Layer w10: v1@608.85,7441.35 v1(607.36,7441.35) ; v1@608.85,7576.37 v1(607.36,7576.37) ; v1@611.61,7441.35 618.81,7434.16 ; v1@611.61,7576.37 618.81,7583.57 ; C51.1@618.81,7424.96 618.81,7434.16 ; C40.1@618.81,7592.77 618.81,7583.57 ; C51.1@624.41,7421.66 C51.1@600.71,7421.66 ; C40.1@624.41,7596.07 C40.1@600.71,7596.07 ; C53.1@985.89,7406.93 C53.1@997.04,7406.93 ; C42.1@985.89,7611.34 C42.1@997.04,7611.34 ; v1(1001.99,7429.46) 1001.99,7409.46 999.46,7406.93 C53.1@997.78,7406.93 ; v1(1001.99,7588.8) 1001.99,7608.8 999.46,7611.34 C42.1@997.78,7611.34 ; C51.1@600.71,7421.66 C51.1@607.36,7428.31 ; C51.1@600.71,7421.66 597.41,7424.96 597.41,7434.16 604.61,7441.35 v1(607.36,7441.35) ; C40.1@600.71,7596.07 597.41,7592.77 597.41,7583.57 604.61,7576.37 v1(607.36,7576.37) ; C40.1@600.71,7596.07 C40.1@607.36,7589.42 ; C51.1@607.36,7428.31 v1(607.36,7441.35) ; C51.1@607.36,7428.31 613.21,7434.16 618.81,7434.16 ; v1(607.36,7576.37) C40.1@607.36,7589.42 ; C40.1@607.36,7589.42 613.21,7583.57 618.81,7583.57 ; C53.1@979.24,7405.69 C53.1@997.78,7405.69 ; C53.1@979.24,7405.69 985.89,7412.34 985.89,7425.39 ; C53.1@979.24,7405.69 979.24,7424.72 979.91,7425.39 ; C42.1@979.24,7612.57 C42.1@997.78,7612.57 ; C42.1@979.24,7612.57 979.24,7593.54 979.91,7592.87 ; C42.1@979.24,7612.57 985.89,7605.92 985.89,7592.87 ; 979.91,7425.39 985.95,7431.43 1003.83,7431.43 v1@997.78,7425.39 ; 979.91,7425.39 985.89,7425.39 ; 979.91,7592.87 985.95,7586.83 1003.83,7586.83 v1@997.78,7592.87 ; 979.91,7592.87 985.89,7592.87 ; 985.89,7425.39 992.83,7413.9 994.06,7411.86 C53.1@997.04,7406.93 ; 985.89,7425.39 v1@997.78,7425.39 ; 985.89,7592.87 992.83,7604.36 994.06,7606.4 C42.1@997.04,7611.34 ; 985.89,7592.87 v1@997.78,7592.87 ; C53.1@997.04,7406.93 C53.1@997.78,7406.93 ; C53.1@997.04,7406.93 C53.1@997.78,7405.69 ; C42.1@997.04,7611.34 C42.1@997.78,7611.34 ; C42.1@997.04,7611.34 C42.1@997.78,7612.57 ; C53.1@997.78,7405.69 C53.1@997.78,7406.93 ; C53.1@997.78,7406.93 v1@997.78,7425.39 ; v1@997.78,7592.87 C42.1@997.78,7611.34 ; C42.1@997.78,7611.34 C42.1@997.78,7612.57
  L12_Bottom Layer w15: C704.1@787.7,7136.86 C704.1@788.84,7138
  other v2: 837.42,6927.97 837.42,6983.22 837.42,7038.47 837.42,7093.72 837.42,7148.97 373.44,7457.5 373.8,7558.87 443.53,7877.86
VA_N2P5_LMH5401_3: C162.2 C164.2 C166.1 C168.1 C177.1 C179.1 C181.2 C183.2 C189.2 C190.2 C191.2 C192.2 C193.2 C194.2 C709.1 C712.2 C713.1 L65.2 R84.1 R571.2 R572.2 R575.1 TP61.1 U10.3 U10.8 U11.5 U11.16 U12.2 | length 2116.2
  L1_Top Layer w10: 620.94,2519.09 620.77,2519.09 ; 626.82,2525.13 608.94,2525.13 v1@602.9,2519.09 ; C183.2@987.41,2482.69 C183.2@998.56,2482.69 ; C164.2@987.41,2687.1 C164.2@998.56,2687.1 ; v1(1418.51,2309.57) 1418.51,2319.57 1428.84,2329.9 U12.2@1456.7,2329.9 ; C181.2@602.23,2499.39 608.88,2506.04 v1(608.88,2517.12) ; C181.2@602.23,2499.39 C181.2@620.77,2499.39 ; C181.2@602.23,2499.39 602.23,2518.42 v1@602.9,2519.09 ; C162.2@602.23,2671.83 602.23,2652.81 v1@602.9,2652.14 ; C162.2@602.23,2671.83 608.88,2665.18 v1(608.88,2652.14) ; C162.2@602.23,2671.83 C162.2@620.77,2671.83 ; v1@602.9,2519.09 v1@608.88,2519.09 ; v1@602.9,2652.14 v1(608.88,2652.14) ; v1@602.9,2652.14 608.94,2646.09 626.82,2646.09 ; v1(608.88,2517.12) v1@610.07,2517.12 ; v1(608.88,2517.12) v1@608.88,2519.09 ; v1@608.88,2519.09 609.75,2517.65 v1@610.07,2517.12 ; v1@608.88,2519.09 620.77,2519.09 ; v1(608.88,2652.14) 620.77,2652.14 ; v1(608.88,2652.14) 615.82,2663.63 C162.2@620.77,2671.83 ; v1@610.07,2517.12 620.77,2517.12 ; v1@610.07,2517.12 615.82,2507.6 616.69,2506.16 C181.2@620.77,2499.39 ; C181.2@620.77,2499.39 620.77,2517.12 ; 620.77,2517.12 620.94,2517.12 632.54,2528.72 U10.8@632.54,2539.35 U10.3@632.54,2629.9 632.54,2640.37 626.82,2646.09 ; 620.77,2517.12 620.77,2519.09 ; 620.77,2652.14 626.82,2646.09 ; 620.77,2652.14 C162.2@620.77,2671.83 ; C183.2@980.76,2481.46 987.41,2488.11 987.41,2501.15 ; C183.2@980.76,2481.46 980.76,2500.48 981.43,2501.15 ; C183.2@980.76,2481.46 C183.2@999.3,2481.46 ; C164.2@980.76,2688.33 C164.2@999.3,2688.33 ; C164.2@980.76,2688.33 980.76,2669.31 981.43,2668.64 ; C164.2@980.76,2688.33 987.41,2681.68 987.41,2668.64 ; 981.43,2501.15 987.41,2501.15 ; 981.43,2501.15 987.47,2507.2 1005.35,2507.2 v1@999.3,2501.15 ; 981.43,2668.64 987.47,2662.59 1005.35,2662.59 v1@999.3,2668.64 ; 981.43,2668.64 987.41,2668.64 ; 987.41,2501.15 v1@999.3,2501.15 ; 987.41,2501.15 994.35,2489.66 995.58,2487.62 C183.2@998.56,2482.69 ; 987.41,2668.64 994.35,2680.13 995.58,2682.17 C164.2@998.56,2687.1 ; 987.41,2668.64 v1@999.3,2668.64 ; C183.2@998.56,2482.69 C183.2@999.3,2481.46 ; C183.2@998.56,2482.69 C183.2@999.3,2482.69 ; C164.2@998.56,2687.1 C164.2@999.3,2688.33 ; C164.2@998.56,2687.1 C164.2@999.3,2687.1 ; C183.2@999.3,2481.46 C183.2@999.3,2482.69 ; C183.2@999.3,2482.69 1000.98,2482.69 1003.51,2485.22 v1(1003.51,2505.22) 1017.88,2519.59 U11.5@1017.88,2529.78 1017.88,2544.28 1028.96,2555.36 1028.96,2616.76 1017.88,2627.84 U11.16@1017.88,2640.01 1017.88,2650.2 v1(1003.51,2664.57) 1003.51,2684.57 1000.98,2687.1 C164.2@999.3,2687.1 ; C183.2@999.3,2482.69 v1@999.3,2501.15 ; v1@999.3,2668.64 C164.2@999.3,2687.1 ; C164.2@999.3,2687.1 C164.2@999.3,2688.33
  L1_Top Layer w15: R575.1@1562.23,2200.8 1562.23,2165.85 v2(1563.51,2164.57)
  L1_Top Layer w17: v1(639.52,2572.27) v1(639.52,2596.97) ; v1(1033.02,2567.64) 1033.32,2567.93 v1(1033.32,2601.64)
  L1_Top Layer w20: v2@375.32,2533.26 R572.2@398.53,2510.05 ; v2@375.32,2635 R571.2@398.53,2658.21 ; v2(389.79,2954.57) C189.2@445.05,2954.57 ; v2(443.89,2823.63) C192.2@477.61,2823.63 ; v2(443.89,2873.63) C191.2@477.61,2873.63 ; v2(598.51,2886.87) R84.1@632.23,2886.87 ; C194.2@1055.03,2820.34 v2(1088.75,2820.34) ; C193.2@1055.03,2870.34 v2(1088.75,2870.34) ; v2(1082.59,2949.4) v2(1137.84,2949.4)
  L12_Bottom Layer w10: v1@610.37,2517.12 v1(608.88,2517.12) ; v1@610.37,2652.14 v1(608.88,2652.14) ; v1@613.13,2517.12 620.33,2509.92 ; v1@613.13,2652.14 620.33,2659.34 ; C177.1@620.33,2500.73 620.33,2509.92 ; C166.1@620.33,2668.53 620.33,2659.34 ; C177.1@625.93,2497.42 C177.1@602.23,2497.42 ; C166.1@625.93,2671.83 C166.1@602.23,2671.83 ; C179.1@987.41,2482.69 C179.1@998.56,2482.69 ; C168.1@987.41,2687.1 C168.1@998.56,2687.1 ; v1(1003.51,2505.22) 1003.51,2485.22 1000.98,2482.69 C179.1@999.3,2482.69 ; v1(1003.51,2664.57) 1003.51,2684.57 1000.98,2687.1 C168.1@999.3,2687.1 ; C177.1@602.23,2497.42 C177.1@608.88,2504.07 ; C177.1@602.23,2497.42 598.93,2500.73 598.93,2509.92 606.12,2517.12 v1(608.88,2517.12) ; C166.1@602.23,2671.83 598.93,2668.53 598.93,2659.34 606.12,2652.14 v1(608.88,2652.14) ; C166.1@602.23,2671.83 C166.1@608.88,2665.18 ; C177.1@608.88,2504.07 v1(608.88,2517.12) ; C177.1@608.88,2504.07 614.73,2509.92 620.33,2509.92 ; v1(608.88,2652.14) C166.1@608.88,2665.18 ; C166.1@608.88,2665.18 614.73,2659.34 620.33,2659.34 ; C179.1@980.76,2481.46 980.76,2500.48 981.43,2501.15 ; C179.1@980.76,2481.46 C179.1@999.3,2481.46 ; C179.1@980.76,2481.46 987.41,2488.11 987.41,2501.15 ; C168.1@980.76,2688.33 C168.1@999.3,2688.33 ; C168.1@980.76,2688.33 980.76,2669.31 981.43,2668.64 ; C168.1@980.76,2688.33 987.41,2681.68 987.41,2668.64 ; 981.43,2501.15 987.47,2507.2 1005.35,2507.2 v1@999.3,2501.15 ; 981.43,2501.15 987.41,2501.15 ; 981.43,2668.64 987.47,2662.59 1005.35,2662.59 v1@999.3,2668.64 ; 981.43,2668.64 987.41,2668.64 ; 987.41,2501.15 994.35,2489.66 995.58,2487.62 C179.1@998.56,2482.69 ; 987.41,2501.15 v1@999.3,2501.15 ; 987.41,2668.64 994.35,2680.13 995.58,2682.17 C168.1@998.56,2687.1 ; 987.41,2668.64 v1@999.3,2668.64 ; C179.1@998.56,2482.69 C179.1@999.3,2481.46 ; C179.1@998.56,2482.69 C179.1@999.3,2482.69 ; C168.1@998.56,2687.1 C168.1@999.3,2688.33 ; C168.1@998.56,2687.1 C168.1@999.3,2687.1 ; C179.1@999.3,2481.46 C179.1@999.3,2482.69 ; C179.1@999.3,2482.69 v1@999.3,2501.15 ; v1@999.3,2668.64 C168.1@999.3,2687.1 ; C168.1@999.3,2687.1 C168.1@999.3,2688.33
  other v2: 839.74,2003.72 839.74,2058.97 839.74,2114.22 839.74,2169.47 839.74,2224.72 374.96,2533.26 375.32,2634.64 445.05,2953.63
VA_N2P5_LMH5401_4: C196.2 C198.2 C200.1 C202.1 C211.1 C213.1 C215.2 C217.2 C223.2 C224.2 C225.2 C226.2 C227.2 C228.2 C718.1 C721.2 C722.1 L67.2 R108.1 R580.2 R581.2 R584.1 TP63.1 U13.3 U13.8 U14.5 U14.16 U15.2 | length 2116.2
  L1_Top Layer w10: 621.02,1099.75 620.85,1099.75 ; 626.89,1105.8 609.02,1105.8 v1@602.97,1099.75 ; C217.2@987.48,1063.36 C217.2@998.63,1063.36 ; C198.2@987.48,1267.77 C198.2@998.63,1267.77 ; v1(1418.59,890.23) 1418.59,900.23 1428.91,910.56 U15.2@1456.78,910.56 ; C215.2@602.3,1080.06 608.95,1086.71 v1(608.95,1097.78) ; C215.2@602.3,1080.06 C215.2@620.85,1080.06 ; C215.2@602.3,1080.06 602.3,1099.08 v1@602.97,1099.75 ; C196.2@602.3,1252.5 602.3,1233.47 v1@602.97,1232.8 ; C196.2@602.3,1252.5 608.95,1245.85 v1(608.95,1232.8) ; C196.2@602.3,1252.5 C196.2@620.85,1252.5 ; v1@602.97,1099.75 v1@608.95,1099.75 ; v1@602.97,1232.8 v1(608.95,1232.8) ; v1@602.97,1232.8 609.02,1226.76 626.89,1226.76 ; v1(608.95,1097.78) v1@608.95,1099.75 ; v1(608.95,1097.78) v1@610.14,1097.78 ; v1@608.95,1099.75 620.85,1099.75 ; v1@608.95,1099.75 609.82,1098.31 v1@610.14,1097.78 ; v1(608.95,1232.8) 615.89,1244.29 C196.2@620.85,1252.5 ; v1(608.95,1232.8) 620.85,1232.8 ; v1@610.14,1097.78 615.89,1088.26 616.76,1086.82 C215.2@620.85,1080.06 ; v1@610.14,1097.78 620.85,1097.78 ; C215.2@620.85,1080.06 620.85,1097.78 ; 620.85,1097.78 621.02,1097.78 632.62,1109.38 U13.8@632.62,1120.02 U13.3@632.62,1210.57 632.62,1221.03 626.89,1226.76 ; 620.85,1097.78 620.85,1099.75 ; 620.85,1232.8 626.89,1226.76 ; 620.85,1232.8 C196.2@620.85,1252.5 ; C217.2@980.83,1062.12 980.83,1081.15 981.5,1081.82 ; C217.2@980.83,1062.12 987.48,1068.77 987.48,1081.82 ; C217.2@980.83,1062.12 C217.2@999.38,1062.12 ; C198.2@980.83,1269 980.83,1249.97 981.5,1249.3 ; C198.2@980.83,1269 987.48,1262.35 987.48,1249.3 ; C198.2@980.83,1269 C198.2@999.38,1269 ; 981.5,1081.82 987.48,1081.82 ; 981.5,1081.82 987.55,1087.86 1005.42,1087.86 v1@999.38,1081.82 ; 981.5,1249.3 987.55,1243.26 1005.42,1243.26 v1@999.38,1249.3 ; 981.5,1249.3 987.48,1249.3 ; 987.48,1081.82 v1@999.38,1081.82 ; 987.48,1081.82 994.42,1070.33 995.65,1068.29 C217.2@998.63,1063.36 ; 987.48,1249.3 994.42,1260.79 995.65,1262.83 C198.2@998.63,1267.77 ; 987.48,1249.3 v1@999.38,1249.3 ; C217.2@998.63,1063.36 C217.2@999.38,1062.12 ; C217.2@998.63,1063.36 C217.2@999.38,1063.36 ; C198.2@998.63,1267.77 C198.2@999.38,1269 ; C198.2@998.63,1267.77 C198.2@999.38,1267.77 ; C217.2@999.38,1062.12 C217.2@999.38,1063.36 ; C217.2@999.38,1063.36 1001.05,1063.36 1003.59,1065.89 v1(1003.59,1085.89) 1017.96,1100.26 U14.5@1017.96,1110.44 1017.96,1124.95 1029.04,1136.03 1029.04,1197.43 1017.96,1208.51 U14.16@1017.96,1220.68 1017.96,1230.86 v1(1003.59,1245.23) 1003.59,1265.23 1001.05,1267.77 C198.2@999.38,1267.77 ; C217.2@999.38,1063.36 v1@999.38,1081.82 ; v1@999.38,1249.3 C198.2@999.38,1267.77 ; C198.2@999.38,1267.77 C198.2@999.38,1269
  L1_Top Layer w15: R584.1@1562.3,781.47 1562.3,746.52 v2(1563.59,745.23)
  L1_Top Layer w17: v1(639.59,1152.93) v1(639.59,1177.63) ; v1(1033.1,1148.3) 1033.39,1148.6 v1(1033.39,1182.3)
  L1_Top Layer w20: v2@375.39,1113.93 R581.2@398.61,1090.71 ; v2@375.39,1215.66 R580.2@398.61,1238.88 ; v2(389.87,1535.23) C223.2@445.12,1535.23 ; v2(443.96,1404.29) C226.2@477.68,1404.29 ; v2(443.96,1454.29) C225.2@477.68,1454.29 ; v2(598.59,1467.54) R108.1@632.3,1467.54 ; C228.2@1055.11,1400.07 v2(1088.82,1400.07) ; C227.2@1055.11,1450.07 v2(1088.82,1450.07) ; v2(1082.66,1529.13) v2(1137.92,1529.13)
  L12_Bottom Layer w10: v1@610.45,1097.78 v1(608.95,1097.78) ; v1@610.45,1232.8 v1(608.95,1232.8) ; v1@613.2,1097.78 620.4,1090.59 ; v1@613.2,1232.8 620.4,1240 ; C211.1@620.4,1081.39 620.4,1090.59 ; C200.1@620.4,1249.19 620.4,1240 ; C211.1@626,1078.09 C211.1@602.3,1078.09 ; C200.1@626,1252.5 C200.1@602.3,1252.5 ; C213.1@987.48,1063.36 C213.1@998.63,1063.36 ; C202.1@987.48,1267.77 C202.1@998.63,1267.77 ; v1(1003.59,1085.89) 1003.59,1065.89 1001.05,1063.36 C213.1@999.38,1063.36 ; v1(1003.59,1245.23) 1003.59,1265.23 1001.05,1267.77 C202.1@999.38,1267.77 ; C211.1@602.3,1078.09 599,1081.39 599,1090.59 606.2,1097.78 v1(608.95,1097.78) ; C211.1@602.3,1078.09 C211.1@608.95,1084.74 ; C200.1@602.3,1252.5 C200.1@608.95,1245.85 ; C200.1@602.3,1252.5 599,1249.19 599,1240 606.2,1232.8 v1(608.95,1232.8) ; C211.1@608.95,1084.74 614.8,1090.59 620.4,1090.59 ; C211.1@608.95,1084.74 v1(608.95,1097.78) ; v1(608.95,1232.8) C200.1@608.95,1245.85 ; C200.1@608.95,1245.85 614.8,1240 620.4,1240 ; C213.1@980.83,1062.12 980.83,1081.15 981.5,1081.82 ; C213.1@980.83,1062.12 C213.1@999.38,1062.12 ; C213.1@980.83,1062.12 987.48,1068.77 987.48,1081.82 ; C202.1@980.83,1269 987.48,1262.35 987.48,1249.3 ; C202.1@980.83,1269 980.83,1249.97 981.5,1249.3 ; C202.1@980.83,1269 C202.1@999.38,1269 ; 981.5,1081.82 987.48,1081.82 ; 981.5,1081.82 987.55,1087.86 1005.42,1087.86 v1@999.38,1081.82 ; 981.5,1249.3 987.48,1249.3 ; 981.5,1249.3 987.55,1243.26 1005.42,1243.26 v1@999.38,1249.3 ; 987.48,1081.82 v1@999.38,1081.82 ; 987.48,1081.82 994.42,1070.33 995.65,1068.29 C213.1@998.63,1063.36 ; 987.48,1249.3 v1@999.38,1249.3 ; 987.48,1249.3 994.42,1260.79 995.65,1262.83 C202.1@998.63,1267.77 ; C213.1@998.63,1063.36 C213.1@999.38,1062.12 ; C213.1@998.63,1063.36 C213.1@999.38,1063.36 ; C202.1@998.63,1267.77 C202.1@999.38,1269 ; C202.1@998.63,1267.77 C202.1@999.38,1267.77 ; C213.1@999.38,1062.12 C213.1@999.38,1063.36 ; C213.1@999.38,1063.36 v1@999.38,1081.82 ; v1@999.38,1249.3 C202.1@999.38,1267.77 ; C202.1@999.38,1267.77 C202.1@999.38,1269
  other v2: 839.19,582.76 839.19,638.01 839.19,693.27 839.19,748.52 839.19,803.77 375.03,1113.93 375.39,1215.3 445.12,1534.29
VADJ_RX1: J46.E39 J46.F40 J46.G39 J46.H40 R473.2 R477.2 | length 3653
  L1_Top Layer w11: R477.2@6292.73,6811.01 6348.93,6867.21 v1@6362.8,6867.21 ; v1(6363.11,6870.01) 6384.3,6891.2 6491.36,6891.2 6541.36,6941.2 6830.68,6941.2 6868.68,6979.2 6868.68,9275.02 6728.16,9415.54 R473.2@6426.02,9415.54
  L12_Bottom Layer w5: v1(6363.11,6870.01) J46.G39@6413.11,6920.01 J46.F40@6463.11,6870.01 J46.E39@6513.11,6920.01
VADJ_RX2: J51.E39 J51.F40 J51.G39 J51.H40 R478.2 R482.2 | length 3448.2
  L1_Top Layer w11: R482.2@6296.37,467.81 6352.57,524.01 v1(6366.44,524.01) ; v1@6366.75,526.81 6387.94,548 6495,548 6545,598 6834.32,598 6872.32,636 6872.32,2996.49 6799.07,3069.74 R478.2@6671.22,3069.74
  L12_Bottom Layer w5: J51.H40@6366.75,526.81 6416.75,576.81 6466.75,526.81 J51.E39@6516.75,576.81
VBUS: C473.1 R470.2 U35.1 U35.3 | length 328.3
  L1_Top Layer w20: U35.1@6310.72,9979.87 6371.89,9979.87 C473.1@6372.57,9979.19 ; U35.3@6310.72,10054.67 6348.59,10054.67 6372.57,10030.69 C473.1@6372.57,9979.19 ; R470.2@6430.71,10077.06 6430.71,10001.66 6408.24,9979.19 C473.1@6372.57,9979.19
VBUSS: C470.1 L34.1 U35.5 | length 136.3
  L1_Top Layer w20: L34.1@6136.57,9981.38 6138.08,9979.87 U35.5@6202.46,9979.87 6202.46,9910.63 C470.1@6202.09,9910.27
VCC1_VCO: C420.1 C421.1 C422.1 L22.2 U24.10 U24.33 U24.36 | length 1207.9
  L1_Top Layer w9.84: U24.33@4764.49,4792.09 v1@4795,4792.09 ; U24.36@4764.49,4851.14 v1(4806.68,4851.14)
  L1_Top Layer w10: v1(4375.73,4910.2) U24.10@4418.03,4910.2
  L4_Signal Layer 1 w20: v1(4375.73,4910.2) 4396.2,4910.2 4413,4927 4413,5092 4439,5118 4734,5118 4768,5084 4768,4889.82 v1(4806.68,4851.14) 4806.68,4800.68 v1(4800,4794)
  L12_Bottom Layer w20: v1(4375.73,4910.2) C420.1@4418.03,4910.2 ; C422.1@4759.59,4791.02 4759.59,4846.24 C421.1@4764.49,4851.14 v1(4806.68,4851.14) ; v1(4800,4794) 4843.56,4794 4846.01,4791.55 L22.2@4846.97,4792.51
VCC2_CG1: C430.1 L23.2 U24.17 | length 212
  L1_Top Layer w8.6: L23.2@4350.97,4679.51 4352,4680.54 v1(4352,4732) 4352,4732.47 4386.03,4766.5 U24.17@4443.62,4766.5
  L12_Bottom Layer w20: C430.1@4350.97,4679.51 4352,4680.54 v1(4352,4732)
